VERSION 5.7 ;
  NOWIREEXTENSIONATPIN ON ;
  DIVIDERCHAR "/" ;
  BUSBITCHARS "[]" ;
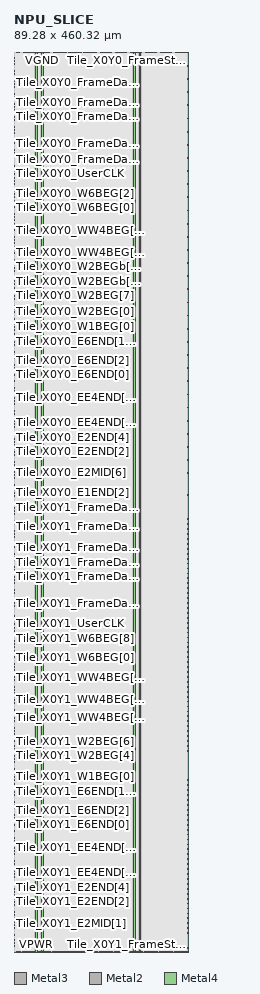
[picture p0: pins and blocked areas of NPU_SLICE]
MACRO NPU_SLICE
  CLASS BLOCK ;
  FOREIGN NPU_SLICE ;
  ORIGIN 0.000 0.000 ;
  SIZE 89.280 BY 460.320 ;
  PIN FAB_USER_CLK
    DIRECTION OUTPUT ;
    USE SIGNAL ;
    ANTENNADIFFAREA 2.724000 ;
    PORT
      LAYER Metal3 ;
        RECT 88.880 221.140 89.280 221.540 ;
    END
  END FAB_USER_CLK
  PIN NPU_ACT_ADDR0
    DIRECTION OUTPUT ;
    USE SIGNAL ;
    ANTENNADIFFAREA 2.647800 ;
    PORT
      LAYER Metal3 ;
        RECT 88.880 143.020 89.280 143.420 ;
    END
  END NPU_ACT_ADDR0
  PIN NPU_ACT_ADDR1
    DIRECTION OUTPUT ;
    USE SIGNAL ;
    ANTENNADIFFAREA 2.647800 ;
    PORT
      LAYER Metal3 ;
        RECT 88.880 145.540 89.280 145.940 ;
    END
  END NPU_ACT_ADDR1
  PIN NPU_ACT_ADDR2
    DIRECTION OUTPUT ;
    USE SIGNAL ;
    ANTENNADIFFAREA 2.647800 ;
    PORT
      LAYER Metal3 ;
        RECT 88.880 148.060 89.280 148.460 ;
    END
  END NPU_ACT_ADDR2
  PIN NPU_ACT_ADDR3
    DIRECTION OUTPUT ;
    USE SIGNAL ;
    ANTENNADIFFAREA 2.647800 ;
    PORT
      LAYER Metal3 ;
        RECT 88.880 150.580 89.280 150.980 ;
    END
  END NPU_ACT_ADDR3
  PIN NPU_ACT_ADDR4
    DIRECTION OUTPUT ;
    USE SIGNAL ;
    ANTENNADIFFAREA 2.647800 ;
    PORT
      LAYER Metal3 ;
        RECT 88.880 153.100 89.280 153.500 ;
    END
  END NPU_ACT_ADDR4
  PIN NPU_ACT_ADDR5
    DIRECTION OUTPUT ;
    USE SIGNAL ;
    ANTENNADIFFAREA 2.647800 ;
    PORT
      LAYER Metal3 ;
        RECT 88.880 155.620 89.280 156.020 ;
    END
  END NPU_ACT_ADDR5
  PIN NPU_ACT_ADDR6
    DIRECTION OUTPUT ;
    USE SIGNAL ;
    ANTENNADIFFAREA 2.647800 ;
    PORT
      LAYER Metal3 ;
        RECT 88.880 158.140 89.280 158.540 ;
    END
  END NPU_ACT_ADDR6
  PIN NPU_ACT_ADDR7
    DIRECTION OUTPUT ;
    USE SIGNAL ;
    ANTENNADIFFAREA 2.647800 ;
    PORT
      LAYER Metal3 ;
        RECT 88.880 160.660 89.280 161.060 ;
    END
  END NPU_ACT_ADDR7
  PIN NPU_ACT_ADDR8
    DIRECTION OUTPUT ;
    USE SIGNAL ;
    ANTENNADIFFAREA 2.647800 ;
    PORT
      LAYER Metal3 ;
        RECT 88.880 163.180 89.280 163.580 ;
    END
  END NPU_ACT_ADDR8
  PIN NPU_ACT_RDATA0
    DIRECTION INPUT ;
    USE SIGNAL ;
    ANTENNAGATEAREA 0.109200 ;
    ANTENNADIFFAREA 2.015400 ;
    PORT
      LAYER Metal3 ;
        RECT 88.880 102.700 89.280 103.100 ;
    END
  END NPU_ACT_RDATA0
  PIN NPU_ACT_RDATA1
    DIRECTION INPUT ;
    USE SIGNAL ;
    ANTENNAGATEAREA 0.109200 ;
    ANTENNADIFFAREA 2.015400 ;
    PORT
      LAYER Metal3 ;
        RECT 88.880 105.220 89.280 105.620 ;
    END
  END NPU_ACT_RDATA1
  PIN NPU_ACT_RDATA2
    DIRECTION INPUT ;
    USE SIGNAL ;
    ANTENNAGATEAREA 0.109200 ;
    ANTENNADIFFAREA 2.015400 ;
    PORT
      LAYER Metal3 ;
        RECT 88.880 107.740 89.280 108.140 ;
    END
  END NPU_ACT_RDATA2
  PIN NPU_ACT_RDATA3
    DIRECTION INPUT ;
    USE SIGNAL ;
    ANTENNAGATEAREA 0.109200 ;
    ANTENNADIFFAREA 2.015400 ;
    PORT
      LAYER Metal3 ;
        RECT 88.880 110.260 89.280 110.660 ;
    END
  END NPU_ACT_RDATA3
  PIN NPU_ACT_RDATA4
    DIRECTION INPUT ;
    USE SIGNAL ;
    ANTENNAGATEAREA 0.109200 ;
    ANTENNADIFFAREA 2.015400 ;
    PORT
      LAYER Metal3 ;
        RECT 88.880 112.780 89.280 113.180 ;
    END
  END NPU_ACT_RDATA4
  PIN NPU_ACT_RDATA5
    DIRECTION INPUT ;
    USE SIGNAL ;
    ANTENNAGATEAREA 0.109200 ;
    ANTENNADIFFAREA 2.015400 ;
    PORT
      LAYER Metal3 ;
        RECT 88.880 115.300 89.280 115.700 ;
    END
  END NPU_ACT_RDATA5
  PIN NPU_ACT_RDATA6
    DIRECTION INPUT ;
    USE SIGNAL ;
    ANTENNAGATEAREA 0.109200 ;
    ANTENNADIFFAREA 2.015400 ;
    PORT
      LAYER Metal3 ;
        RECT 88.880 117.820 89.280 118.220 ;
    END
  END NPU_ACT_RDATA6
  PIN NPU_ACT_RDATA7
    DIRECTION INPUT ;
    USE SIGNAL ;
    ANTENNAGATEAREA 0.109200 ;
    ANTENNADIFFAREA 2.015400 ;
    PORT
      LAYER Metal3 ;
        RECT 88.880 120.340 89.280 120.740 ;
    END
  END NPU_ACT_RDATA7
  PIN NPU_ACT_WDATA0
    DIRECTION OUTPUT ;
    USE SIGNAL ;
    ANTENNADIFFAREA 2.647800 ;
    PORT
      LAYER Metal3 ;
        RECT 88.880 165.700 89.280 166.100 ;
    END
  END NPU_ACT_WDATA0
  PIN NPU_ACT_WDATA1
    DIRECTION OUTPUT ;
    USE SIGNAL ;
    ANTENNADIFFAREA 2.647800 ;
    PORT
      LAYER Metal3 ;
        RECT 88.880 168.220 89.280 168.620 ;
    END
  END NPU_ACT_WDATA1
  PIN NPU_ACT_WDATA2
    DIRECTION OUTPUT ;
    USE SIGNAL ;
    ANTENNADIFFAREA 2.647800 ;
    PORT
      LAYER Metal3 ;
        RECT 88.880 170.740 89.280 171.140 ;
    END
  END NPU_ACT_WDATA2
  PIN NPU_ACT_WDATA3
    DIRECTION OUTPUT ;
    USE SIGNAL ;
    ANTENNADIFFAREA 2.647800 ;
    PORT
      LAYER Metal3 ;
        RECT 88.880 173.260 89.280 173.660 ;
    END
  END NPU_ACT_WDATA3
  PIN NPU_ACT_WDATA4
    DIRECTION OUTPUT ;
    USE SIGNAL ;
    ANTENNADIFFAREA 2.647800 ;
    PORT
      LAYER Metal3 ;
        RECT 88.880 175.780 89.280 176.180 ;
    END
  END NPU_ACT_WDATA4
  PIN NPU_ACT_WDATA5
    DIRECTION OUTPUT ;
    USE SIGNAL ;
    ANTENNADIFFAREA 2.647800 ;
    PORT
      LAYER Metal3 ;
        RECT 88.880 178.300 89.280 178.700 ;
    END
  END NPU_ACT_WDATA5
  PIN NPU_ACT_WDATA6
    DIRECTION OUTPUT ;
    USE SIGNAL ;
    ANTENNADIFFAREA 2.647800 ;
    PORT
      LAYER Metal3 ;
        RECT 88.880 180.820 89.280 181.220 ;
    END
  END NPU_ACT_WDATA6
  PIN NPU_ACT_WDATA7
    DIRECTION OUTPUT ;
    USE SIGNAL ;
    ANTENNADIFFAREA 2.647800 ;
    PORT
      LAYER Metal3 ;
        RECT 88.880 183.340 89.280 183.740 ;
    END
  END NPU_ACT_WDATA7
  PIN NPU_ACT_WE
    DIRECTION OUTPUT ;
    USE SIGNAL ;
    ANTENNADIFFAREA 2.647800 ;
    PORT
      LAYER Metal3 ;
        RECT 88.880 185.860 89.280 186.260 ;
    END
  END NPU_ACT_WE
  PIN NPU_OUT_ACT0
    DIRECTION INPUT ;
    USE SIGNAL ;
    ANTENNAGATEAREA 0.109200 ;
    ANTENNADIFFAREA 2.015400 ;
    PORT
      LAYER Metal3 ;
        RECT 88.880 122.860 89.280 123.260 ;
    END
  END NPU_OUT_ACT0
  PIN NPU_OUT_ACT1
    DIRECTION INPUT ;
    USE SIGNAL ;
    ANTENNAGATEAREA 0.109200 ;
    ANTENNADIFFAREA 2.015400 ;
    PORT
      LAYER Metal3 ;
        RECT 88.880 125.380 89.280 125.780 ;
    END
  END NPU_OUT_ACT1
  PIN NPU_OUT_ACT2
    DIRECTION INPUT ;
    USE SIGNAL ;
    ANTENNAGATEAREA 0.109200 ;
    ANTENNADIFFAREA 2.015400 ;
    PORT
      LAYER Metal3 ;
        RECT 88.880 127.900 89.280 128.300 ;
    END
  END NPU_OUT_ACT2
  PIN NPU_OUT_ACT3
    DIRECTION INPUT ;
    USE SIGNAL ;
    ANTENNAGATEAREA 0.109200 ;
    ANTENNADIFFAREA 2.015400 ;
    PORT
      LAYER Metal3 ;
        RECT 88.880 130.420 89.280 130.820 ;
    END
  END NPU_OUT_ACT3
  PIN NPU_OUT_ACT4
    DIRECTION INPUT ;
    USE SIGNAL ;
    ANTENNAGATEAREA 0.109200 ;
    ANTENNADIFFAREA 2.015400 ;
    PORT
      LAYER Metal3 ;
        RECT 88.880 132.940 89.280 133.340 ;
    END
  END NPU_OUT_ACT4
  PIN NPU_OUT_ACT5
    DIRECTION INPUT ;
    USE SIGNAL ;
    ANTENNAGATEAREA 0.109200 ;
    ANTENNADIFFAREA 2.015400 ;
    PORT
      LAYER Metal3 ;
        RECT 88.880 135.460 89.280 135.860 ;
    END
  END NPU_OUT_ACT5
  PIN NPU_OUT_ACT6
    DIRECTION INPUT ;
    USE SIGNAL ;
    ANTENNAGATEAREA 0.109200 ;
    ANTENNADIFFAREA 2.015400 ;
    PORT
      LAYER Metal3 ;
        RECT 88.880 137.980 89.280 138.380 ;
    END
  END NPU_OUT_ACT6
  PIN NPU_OUT_ACT7
    DIRECTION INPUT ;
    USE SIGNAL ;
    ANTENNAGATEAREA 0.109200 ;
    ANTENNADIFFAREA 2.015400 ;
    PORT
      LAYER Metal3 ;
        RECT 88.880 140.500 89.280 140.900 ;
    END
  END NPU_OUT_ACT7
  PIN NPU_WEIGHT_IN0
    DIRECTION OUTPUT ;
    USE SIGNAL ;
    ANTENNADIFFAREA 2.647800 ;
    PORT
      LAYER Metal3 ;
        RECT 88.880 188.380 89.280 188.780 ;
    END
  END NPU_WEIGHT_IN0
  PIN NPU_WEIGHT_IN1
    DIRECTION OUTPUT ;
    USE SIGNAL ;
    ANTENNADIFFAREA 2.647800 ;
    PORT
      LAYER Metal3 ;
        RECT 88.880 190.900 89.280 191.300 ;
    END
  END NPU_WEIGHT_IN1
  PIN NPU_WEIGHT_IN2
    DIRECTION OUTPUT ;
    USE SIGNAL ;
    ANTENNADIFFAREA 2.647800 ;
    PORT
      LAYER Metal3 ;
        RECT 88.880 193.420 89.280 193.820 ;
    END
  END NPU_WEIGHT_IN2
  PIN NPU_WEIGHT_IN3
    DIRECTION OUTPUT ;
    USE SIGNAL ;
    ANTENNADIFFAREA 2.647800 ;
    PORT
      LAYER Metal3 ;
        RECT 88.880 195.940 89.280 196.340 ;
    END
  END NPU_WEIGHT_IN3
  PIN NPU_WEIGHT_IN4
    DIRECTION OUTPUT ;
    USE SIGNAL ;
    ANTENNADIFFAREA 2.647800 ;
    PORT
      LAYER Metal3 ;
        RECT 88.880 198.460 89.280 198.860 ;
    END
  END NPU_WEIGHT_IN4
  PIN NPU_WEIGHT_IN5
    DIRECTION OUTPUT ;
    USE SIGNAL ;
    ANTENNADIFFAREA 2.647800 ;
    PORT
      LAYER Metal3 ;
        RECT 88.880 200.980 89.280 201.380 ;
    END
  END NPU_WEIGHT_IN5
  PIN NPU_WEIGHT_IN6
    DIRECTION OUTPUT ;
    USE SIGNAL ;
    ANTENNADIFFAREA 2.647800 ;
    PORT
      LAYER Metal3 ;
        RECT 88.880 203.500 89.280 203.900 ;
    END
  END NPU_WEIGHT_IN6
  PIN NPU_WEIGHT_IN7
    DIRECTION OUTPUT ;
    USE SIGNAL ;
    ANTENNADIFFAREA 2.647800 ;
    PORT
      LAYER Metal3 ;
        RECT 88.880 206.020 89.280 206.420 ;
    END
  END NPU_WEIGHT_IN7
  PIN NPU_WEIGHT_SHIFT_EN
    DIRECTION OUTPUT ;
    USE SIGNAL ;
    ANTENNADIFFAREA 2.647800 ;
    PORT
      LAYER Metal3 ;
        RECT 88.880 208.540 89.280 208.940 ;
    END
  END NPU_WEIGHT_SHIFT_EN
  PIN NPU_XBAR_SEL0
    DIRECTION OUTPUT ;
    USE SIGNAL ;
    ANTENNADIFFAREA 2.647800 ;
    PORT
      LAYER Metal3 ;
        RECT 88.880 211.060 89.280 211.460 ;
    END
  END NPU_XBAR_SEL0
  PIN NPU_XBAR_SEL1
    DIRECTION OUTPUT ;
    USE SIGNAL ;
    ANTENNADIFFAREA 2.647800 ;
    PORT
      LAYER Metal3 ;
        RECT 88.880 213.580 89.280 213.980 ;
    END
  END NPU_XBAR_SEL1
  PIN NPU_XBAR_SEL2
    DIRECTION OUTPUT ;
    USE SIGNAL ;
    ANTENNADIFFAREA 2.647800 ;
    PORT
      LAYER Metal3 ;
        RECT 88.880 216.100 89.280 216.500 ;
    END
  END NPU_XBAR_SEL2
  PIN NPU_XBAR_SEL3
    DIRECTION OUTPUT ;
    USE SIGNAL ;
    ANTENNADIFFAREA 2.647800 ;
    PORT
      LAYER Metal3 ;
        RECT 88.880 218.620 89.280 219.020 ;
    END
  END NPU_XBAR_SEL3
  PIN Tile_X0Y0_E1END[0]
    DIRECTION INPUT ;
    USE SIGNAL ;
    ANTENNAGATEAREA 1.279200 ;
    ANTENNADIFFAREA 12.092400 ;
    PORT
      LAYER Metal3 ;
        RECT 0.000 231.220 0.400 231.620 ;
    END
  END Tile_X0Y0_E1END[0]
  PIN Tile_X0Y0_E1END[1]
    DIRECTION INPUT ;
    USE SIGNAL ;
    ANTENNAGATEAREA 1.279200 ;
    ANTENNADIFFAREA 12.092400 ;
    PORT
      LAYER Metal3 ;
        RECT 0.000 232.900 0.400 233.300 ;
    END
  END Tile_X0Y0_E1END[1]
  PIN Tile_X0Y0_E1END[2]
    DIRECTION INPUT ;
    USE SIGNAL ;
    ANTENNAGATEAREA 1.279200 ;
    ANTENNADIFFAREA 12.092400 ;
    PORT
      LAYER Metal3 ;
        RECT 0.000 234.580 0.400 234.980 ;
    END
  END Tile_X0Y0_E1END[2]
  PIN Tile_X0Y0_E1END[3]
    DIRECTION INPUT ;
    USE SIGNAL ;
    ANTENNAGATEAREA 1.066000 ;
    ANTENNADIFFAREA 10.077000 ;
    PORT
      LAYER Metal3 ;
        RECT 0.000 236.260 0.400 236.660 ;
    END
  END Tile_X0Y0_E1END[3]
  PIN Tile_X0Y0_E2END[0]
    DIRECTION INPUT ;
    USE SIGNAL ;
    ANTENNAGATEAREA 0.639600 ;
    ANTENNADIFFAREA 6.046200 ;
    PORT
      LAYER Metal3 ;
        RECT 0.000 252.220 0.400 252.620 ;
    END
  END Tile_X0Y0_E2END[0]
  PIN Tile_X0Y0_E2END[1]
    DIRECTION INPUT ;
    USE SIGNAL ;
    ANTENNAGATEAREA 0.639600 ;
    ANTENNADIFFAREA 6.046200 ;
    PORT
      LAYER Metal3 ;
        RECT 0.000 253.900 0.400 254.300 ;
    END
  END Tile_X0Y0_E2END[1]
  PIN Tile_X0Y0_E2END[2]
    DIRECTION INPUT ;
    USE SIGNAL ;
    ANTENNAGATEAREA 0.639600 ;
    ANTENNADIFFAREA 6.046200 ;
    PORT
      LAYER Metal3 ;
        RECT 0.000 255.580 0.400 255.980 ;
    END
  END Tile_X0Y0_E2END[2]
  PIN Tile_X0Y0_E2END[3]
    DIRECTION INPUT ;
    USE SIGNAL ;
    ANTENNAGATEAREA 0.639600 ;
    ANTENNADIFFAREA 6.046200 ;
    PORT
      LAYER Metal3 ;
        RECT 0.000 257.260 0.400 257.660 ;
    END
  END Tile_X0Y0_E2END[3]
  PIN Tile_X0Y0_E2END[4]
    DIRECTION INPUT ;
    USE SIGNAL ;
    ANTENNAGATEAREA 0.639600 ;
    ANTENNADIFFAREA 6.046200 ;
    PORT
      LAYER Metal3 ;
        RECT 0.000 258.940 0.400 259.340 ;
    END
  END Tile_X0Y0_E2END[4]
  PIN Tile_X0Y0_E2END[5]
    DIRECTION INPUT ;
    USE SIGNAL ;
    ANTENNAGATEAREA 0.639600 ;
    ANTENNADIFFAREA 6.046200 ;
    PORT
      LAYER Metal3 ;
        RECT 0.000 260.620 0.400 261.020 ;
    END
  END Tile_X0Y0_E2END[5]
  PIN Tile_X0Y0_E2END[6]
    DIRECTION INPUT ;
    USE SIGNAL ;
    ANTENNAGATEAREA 0.639600 ;
    ANTENNADIFFAREA 6.046200 ;
    PORT
      LAYER Metal3 ;
        RECT 0.000 262.300 0.400 262.700 ;
    END
  END Tile_X0Y0_E2END[6]
  PIN Tile_X0Y0_E2END[7]
    DIRECTION INPUT ;
    USE SIGNAL ;
    ANTENNAGATEAREA 0.639600 ;
    ANTENNADIFFAREA 6.046200 ;
    PORT
      LAYER Metal3 ;
        RECT 0.000 263.980 0.400 264.380 ;
    END
  END Tile_X0Y0_E2END[7]
  PIN Tile_X0Y0_E2MID[0]
    DIRECTION INPUT ;
    USE SIGNAL ;
    ANTENNAGATEAREA 0.639600 ;
    ANTENNADIFFAREA 6.046200 ;
    PORT
      LAYER Metal3 ;
        RECT 0.000 238.780 0.400 239.180 ;
    END
  END Tile_X0Y0_E2MID[0]
  PIN Tile_X0Y0_E2MID[1]
    DIRECTION INPUT ;
    USE SIGNAL ;
    ANTENNAGATEAREA 0.639600 ;
    ANTENNADIFFAREA 6.046200 ;
    PORT
      LAYER Metal3 ;
        RECT 0.000 240.460 0.400 240.860 ;
    END
  END Tile_X0Y0_E2MID[1]
  PIN Tile_X0Y0_E2MID[2]
    DIRECTION INPUT ;
    USE SIGNAL ;
    ANTENNAGATEAREA 0.639600 ;
    ANTENNADIFFAREA 6.046200 ;
    PORT
      LAYER Metal3 ;
        RECT 0.000 242.140 0.400 242.540 ;
    END
  END Tile_X0Y0_E2MID[2]
  PIN Tile_X0Y0_E2MID[3]
    DIRECTION INPUT ;
    USE SIGNAL ;
    ANTENNAGATEAREA 0.639600 ;
    ANTENNADIFFAREA 6.046200 ;
    PORT
      LAYER Metal3 ;
        RECT 0.000 243.820 0.400 244.220 ;
    END
  END Tile_X0Y0_E2MID[3]
  PIN Tile_X0Y0_E2MID[4]
    DIRECTION INPUT ;
    USE SIGNAL ;
    ANTENNAGATEAREA 0.639600 ;
    ANTENNADIFFAREA 6.046200 ;
    PORT
      LAYER Metal3 ;
        RECT 0.000 245.500 0.400 245.900 ;
    END
  END Tile_X0Y0_E2MID[4]
  PIN Tile_X0Y0_E2MID[5]
    DIRECTION INPUT ;
    USE SIGNAL ;
    ANTENNAGATEAREA 0.639600 ;
    ANTENNADIFFAREA 6.046200 ;
    PORT
      LAYER Metal3 ;
        RECT 0.000 247.180 0.400 247.580 ;
    END
  END Tile_X0Y0_E2MID[5]
  PIN Tile_X0Y0_E2MID[6]
    DIRECTION INPUT ;
    USE SIGNAL ;
    ANTENNAGATEAREA 0.639600 ;
    ANTENNADIFFAREA 6.046200 ;
    PORT
      LAYER Metal3 ;
        RECT 0.000 248.860 0.400 249.260 ;
    END
  END Tile_X0Y0_E2MID[6]
  PIN Tile_X0Y0_E2MID[7]
    DIRECTION INPUT ;
    USE SIGNAL ;
    ANTENNAGATEAREA 0.639600 ;
    ANTENNADIFFAREA 6.046200 ;
    PORT
      LAYER Metal3 ;
        RECT 0.000 250.540 0.400 250.940 ;
    END
  END Tile_X0Y0_E2MID[7]
  PIN Tile_X0Y0_E6END[0]
    DIRECTION INPUT ;
    USE SIGNAL ;
    ANTENNAGATEAREA 0.852800 ;
    ANTENNADIFFAREA 8.061600 ;
    PORT
      LAYER Metal3 ;
        RECT 0.000 295.060 0.400 295.460 ;
    END
  END Tile_X0Y0_E6END[0]
  PIN Tile_X0Y0_E6END[10]
    DIRECTION INPUT ;
    USE SIGNAL ;
    ANTENNAGATEAREA 0.639600 ;
    ANTENNADIFFAREA 6.046200 ;
    PORT
      LAYER Metal3 ;
        RECT 0.000 311.860 0.400 312.260 ;
    END
  END Tile_X0Y0_E6END[10]
  PIN Tile_X0Y0_E6END[11]
    DIRECTION INPUT ;
    USE SIGNAL ;
    ANTENNAGATEAREA 0.639600 ;
    ANTENNADIFFAREA 6.046200 ;
    PORT
      LAYER Metal3 ;
        RECT 0.000 313.540 0.400 313.940 ;
    END
  END Tile_X0Y0_E6END[11]
  PIN Tile_X0Y0_E6END[1]
    DIRECTION INPUT ;
    USE SIGNAL ;
    ANTENNAGATEAREA 0.852800 ;
    ANTENNADIFFAREA 8.061600 ;
    PORT
      LAYER Metal3 ;
        RECT 0.000 296.740 0.400 297.140 ;
    END
  END Tile_X0Y0_E6END[1]
  PIN Tile_X0Y0_E6END[2]
    DIRECTION INPUT ;
    USE SIGNAL ;
    ANTENNAGATEAREA 0.852800 ;
    ANTENNADIFFAREA 8.061600 ;
    PORT
      LAYER Metal3 ;
        RECT 0.000 298.420 0.400 298.820 ;
    END
  END Tile_X0Y0_E6END[2]
  PIN Tile_X0Y0_E6END[3]
    DIRECTION INPUT ;
    USE SIGNAL ;
    ANTENNAGATEAREA 0.639600 ;
    ANTENNADIFFAREA 6.046200 ;
    PORT
      LAYER Metal3 ;
        RECT 0.000 300.100 0.400 300.500 ;
    END
  END Tile_X0Y0_E6END[3]
  PIN Tile_X0Y0_E6END[4]
    DIRECTION INPUT ;
    USE SIGNAL ;
    ANTENNAGATEAREA 0.639600 ;
    ANTENNADIFFAREA 6.046200 ;
    PORT
      LAYER Metal3 ;
        RECT 0.000 301.780 0.400 302.180 ;
    END
  END Tile_X0Y0_E6END[4]
  PIN Tile_X0Y0_E6END[5]
    DIRECTION INPUT ;
    USE SIGNAL ;
    ANTENNAGATEAREA 0.639600 ;
    ANTENNADIFFAREA 6.046200 ;
    PORT
      LAYER Metal3 ;
        RECT 0.000 303.460 0.400 303.860 ;
    END
  END Tile_X0Y0_E6END[5]
  PIN Tile_X0Y0_E6END[6]
    DIRECTION INPUT ;
    USE SIGNAL ;
    ANTENNAGATEAREA 0.639600 ;
    ANTENNADIFFAREA 6.046200 ;
    PORT
      LAYER Metal3 ;
        RECT 0.000 305.140 0.400 305.540 ;
    END
  END Tile_X0Y0_E6END[6]
  PIN Tile_X0Y0_E6END[7]
    DIRECTION INPUT ;
    USE SIGNAL ;
    ANTENNAGATEAREA 0.639600 ;
    ANTENNADIFFAREA 6.046200 ;
    PORT
      LAYER Metal3 ;
        RECT 0.000 306.820 0.400 307.220 ;
    END
  END Tile_X0Y0_E6END[7]
  PIN Tile_X0Y0_E6END[8]
    DIRECTION INPUT ;
    USE SIGNAL ;
    ANTENNAGATEAREA 0.639600 ;
    ANTENNADIFFAREA 6.046200 ;
    PORT
      LAYER Metal3 ;
        RECT 0.000 308.500 0.400 308.900 ;
    END
  END Tile_X0Y0_E6END[8]
  PIN Tile_X0Y0_E6END[9]
    DIRECTION INPUT ;
    USE SIGNAL ;
    ANTENNAGATEAREA 0.639600 ;
    ANTENNADIFFAREA 6.046200 ;
    PORT
      LAYER Metal3 ;
        RECT 0.000 310.180 0.400 310.580 ;
    END
  END Tile_X0Y0_E6END[9]
  PIN Tile_X0Y0_EE4END[0]
    DIRECTION INPUT ;
    USE SIGNAL ;
    ANTENNAGATEAREA 0.426400 ;
    ANTENNADIFFAREA 4.030800 ;
    PORT
      LAYER Metal3 ;
        RECT 0.000 266.500 0.400 266.900 ;
    END
  END Tile_X0Y0_EE4END[0]
  PIN Tile_X0Y0_EE4END[10]
    DIRECTION INPUT ;
    USE SIGNAL ;
    ANTENNAGATEAREA 0.426400 ;
    ANTENNADIFFAREA 4.030800 ;
    PORT
      LAYER Metal3 ;
        RECT 0.000 283.300 0.400 283.700 ;
    END
  END Tile_X0Y0_EE4END[10]
  PIN Tile_X0Y0_EE4END[11]
    DIRECTION INPUT ;
    USE SIGNAL ;
    ANTENNAGATEAREA 0.426400 ;
    ANTENNADIFFAREA 4.030800 ;
    PORT
      LAYER Metal3 ;
        RECT 0.000 284.980 0.400 285.380 ;
    END
  END Tile_X0Y0_EE4END[11]
  PIN Tile_X0Y0_EE4END[12]
    DIRECTION INPUT ;
    USE SIGNAL ;
    ANTENNAGATEAREA 0.426400 ;
    ANTENNADIFFAREA 4.030800 ;
    PORT
      LAYER Metal3 ;
        RECT 0.000 286.660 0.400 287.060 ;
    END
  END Tile_X0Y0_EE4END[12]
  PIN Tile_X0Y0_EE4END[13]
    DIRECTION INPUT ;
    USE SIGNAL ;
    ANTENNAGATEAREA 0.426400 ;
    ANTENNADIFFAREA 4.030800 ;
    PORT
      LAYER Metal3 ;
        RECT 0.000 288.340 0.400 288.740 ;
    END
  END Tile_X0Y0_EE4END[13]
  PIN Tile_X0Y0_EE4END[14]
    DIRECTION INPUT ;
    USE SIGNAL ;
    ANTENNAGATEAREA 0.426400 ;
    ANTENNADIFFAREA 4.030800 ;
    PORT
      LAYER Metal3 ;
        RECT 0.000 290.020 0.400 290.420 ;
    END
  END Tile_X0Y0_EE4END[14]
  PIN Tile_X0Y0_EE4END[15]
    DIRECTION INPUT ;
    USE SIGNAL ;
    ANTENNAGATEAREA 0.426400 ;
    ANTENNADIFFAREA 4.030800 ;
    PORT
      LAYER Metal3 ;
        RECT 0.000 291.700 0.400 292.100 ;
    END
  END Tile_X0Y0_EE4END[15]
  PIN Tile_X0Y0_EE4END[1]
    DIRECTION INPUT ;
    USE SIGNAL ;
    ANTENNAGATEAREA 0.426400 ;
    ANTENNADIFFAREA 4.030800 ;
    PORT
      LAYER Metal3 ;
        RECT 0.000 268.180 0.400 268.580 ;
    END
  END Tile_X0Y0_EE4END[1]
  PIN Tile_X0Y0_EE4END[2]
    DIRECTION INPUT ;
    USE SIGNAL ;
    ANTENNAGATEAREA 0.426400 ;
    ANTENNADIFFAREA 4.030800 ;
    PORT
      LAYER Metal3 ;
        RECT 0.000 269.860 0.400 270.260 ;
    END
  END Tile_X0Y0_EE4END[2]
  PIN Tile_X0Y0_EE4END[3]
    DIRECTION INPUT ;
    USE SIGNAL ;
    ANTENNAGATEAREA 0.426400 ;
    ANTENNADIFFAREA 4.030800 ;
    PORT
      LAYER Metal3 ;
        RECT 0.000 271.540 0.400 271.940 ;
    END
  END Tile_X0Y0_EE4END[3]
  PIN Tile_X0Y0_EE4END[4]
    DIRECTION INPUT ;
    USE SIGNAL ;
    ANTENNAGATEAREA 0.426400 ;
    ANTENNADIFFAREA 4.030800 ;
    PORT
      LAYER Metal3 ;
        RECT 0.000 273.220 0.400 273.620 ;
    END
  END Tile_X0Y0_EE4END[4]
  PIN Tile_X0Y0_EE4END[5]
    DIRECTION INPUT ;
    USE SIGNAL ;
    ANTENNAGATEAREA 0.426400 ;
    ANTENNADIFFAREA 4.030800 ;
    PORT
      LAYER Metal3 ;
        RECT 0.000 274.900 0.400 275.300 ;
    END
  END Tile_X0Y0_EE4END[5]
  PIN Tile_X0Y0_EE4END[6]
    DIRECTION INPUT ;
    USE SIGNAL ;
    ANTENNAGATEAREA 0.426400 ;
    ANTENNADIFFAREA 4.030800 ;
    PORT
      LAYER Metal3 ;
        RECT 0.000 276.580 0.400 276.980 ;
    END
  END Tile_X0Y0_EE4END[6]
  PIN Tile_X0Y0_EE4END[7]
    DIRECTION INPUT ;
    USE SIGNAL ;
    ANTENNAGATEAREA 0.426400 ;
    ANTENNADIFFAREA 4.030800 ;
    PORT
      LAYER Metal3 ;
        RECT 0.000 278.260 0.400 278.660 ;
    END
  END Tile_X0Y0_EE4END[7]
  PIN Tile_X0Y0_EE4END[8]
    DIRECTION INPUT ;
    USE SIGNAL ;
    ANTENNAGATEAREA 0.426400 ;
    ANTENNADIFFAREA 4.030800 ;
    PORT
      LAYER Metal3 ;
        RECT 0.000 279.940 0.400 280.340 ;
    END
  END Tile_X0Y0_EE4END[8]
  PIN Tile_X0Y0_EE4END[9]
    DIRECTION INPUT ;
    USE SIGNAL ;
    ANTENNAGATEAREA 0.426400 ;
    ANTENNADIFFAREA 4.030800 ;
    PORT
      LAYER Metal3 ;
        RECT 0.000 281.620 0.400 282.020 ;
    END
  END Tile_X0Y0_EE4END[9]
  PIN Tile_X0Y0_FrameData[0]
    DIRECTION INPUT ;
    USE SIGNAL ;
    ANTENNAGATEAREA 1.445600 ;
    ANTENNADIFFAREA 16.123199 ;
    PORT
      LAYER Metal3 ;
        RECT 0.000 405.100 0.400 405.500 ;
    END
  END Tile_X0Y0_FrameData[0]
  PIN Tile_X0Y0_FrameData[10]
    DIRECTION INPUT ;
    USE SIGNAL ;
    ANTENNAGATEAREA 1.626300 ;
    ANTENNADIFFAREA 18.138599 ;
    PORT
      LAYER Metal3 ;
        RECT 0.000 421.900 0.400 422.300 ;
    END
  END Tile_X0Y0_FrameData[10]
  PIN Tile_X0Y0_FrameData[11]
    DIRECTION INPUT ;
    USE SIGNAL ;
    ANTENNAGATEAREA 1.626300 ;
    ANTENNADIFFAREA 18.138599 ;
    PORT
      LAYER Metal3 ;
        RECT 0.000 423.580 0.400 423.980 ;
    END
  END Tile_X0Y0_FrameData[11]
  PIN Tile_X0Y0_FrameData[12]
    DIRECTION INPUT ;
    USE SIGNAL ;
    ANTENNAGATEAREA 1.626300 ;
    ANTENNADIFFAREA 18.138599 ;
    PORT
      LAYER Metal3 ;
        RECT 0.000 425.260 0.400 425.660 ;
    END
  END Tile_X0Y0_FrameData[12]
  PIN Tile_X0Y0_FrameData[13]
    DIRECTION INPUT ;
    USE SIGNAL ;
    ANTENNAGATEAREA 1.626300 ;
    ANTENNADIFFAREA 18.138599 ;
    PORT
      LAYER Metal3 ;
        RECT 0.000 426.940 0.400 427.340 ;
    END
  END Tile_X0Y0_FrameData[13]
  PIN Tile_X0Y0_FrameData[14]
    DIRECTION INPUT ;
    USE SIGNAL ;
    ANTENNAGATEAREA 1.626300 ;
    ANTENNADIFFAREA 18.138599 ;
    PORT
      LAYER Metal3 ;
        RECT 0.000 428.620 0.400 429.020 ;
    END
  END Tile_X0Y0_FrameData[14]
  PIN Tile_X0Y0_FrameData[15]
    DIRECTION INPUT ;
    USE SIGNAL ;
    ANTENNAGATEAREA 1.626300 ;
    ANTENNADIFFAREA 18.138599 ;
    PORT
      LAYER Metal3 ;
        RECT 0.000 430.300 0.400 430.700 ;
    END
  END Tile_X0Y0_FrameData[15]
  PIN Tile_X0Y0_FrameData[16]
    DIRECTION INPUT ;
    USE SIGNAL ;
    ANTENNAGATEAREA 1.626300 ;
    ANTENNADIFFAREA 18.138599 ;
    PORT
      LAYER Metal3 ;
        RECT 0.000 431.980 0.400 432.380 ;
    END
  END Tile_X0Y0_FrameData[16]
  PIN Tile_X0Y0_FrameData[17]
    DIRECTION INPUT ;
    USE SIGNAL ;
    ANTENNAGATEAREA 1.626300 ;
    ANTENNADIFFAREA 18.138599 ;
    PORT
      LAYER Metal3 ;
        RECT 0.000 433.660 0.400 434.060 ;
    END
  END Tile_X0Y0_FrameData[17]
  PIN Tile_X0Y0_FrameData[18]
    DIRECTION INPUT ;
    USE SIGNAL ;
    ANTENNAGATEAREA 1.626300 ;
    ANTENNADIFFAREA 18.138599 ;
    PORT
      LAYER Metal3 ;
        RECT 0.000 435.340 0.400 435.740 ;
    END
  END Tile_X0Y0_FrameData[18]
  PIN Tile_X0Y0_FrameData[19]
    DIRECTION INPUT ;
    USE SIGNAL ;
    ANTENNAGATEAREA 1.626300 ;
    ANTENNADIFFAREA 18.138599 ;
    PORT
      LAYER Metal3 ;
        RECT 0.000 437.020 0.400 437.420 ;
    END
  END Tile_X0Y0_FrameData[19]
  PIN Tile_X0Y0_FrameData[1]
    DIRECTION INPUT ;
    USE SIGNAL ;
    ANTENNAGATEAREA 1.445600 ;
    ANTENNADIFFAREA 16.123199 ;
    PORT
      LAYER Metal3 ;
        RECT 0.000 406.780 0.400 407.180 ;
    END
  END Tile_X0Y0_FrameData[1]
  PIN Tile_X0Y0_FrameData[20]
    DIRECTION INPUT ;
    USE SIGNAL ;
    ANTENNAGATEAREA 1.626300 ;
    ANTENNADIFFAREA 18.138599 ;
    PORT
      LAYER Metal3 ;
        RECT 0.000 438.700 0.400 439.100 ;
    END
  END Tile_X0Y0_FrameData[20]
  PIN Tile_X0Y0_FrameData[21]
    DIRECTION INPUT ;
    USE SIGNAL ;
    ANTENNAGATEAREA 1.626300 ;
    ANTENNADIFFAREA 18.138599 ;
    PORT
      LAYER Metal3 ;
        RECT 0.000 440.380 0.400 440.780 ;
    END
  END Tile_X0Y0_FrameData[21]
  PIN Tile_X0Y0_FrameData[22]
    DIRECTION INPUT ;
    USE SIGNAL ;
    ANTENNAGATEAREA 1.626300 ;
    ANTENNADIFFAREA 18.138599 ;
    PORT
      LAYER Metal3 ;
        RECT 0.000 442.060 0.400 442.460 ;
    END
  END Tile_X0Y0_FrameData[22]
  PIN Tile_X0Y0_FrameData[23]
    DIRECTION INPUT ;
    USE SIGNAL ;
    ANTENNAGATEAREA 1.626300 ;
    ANTENNADIFFAREA 18.138599 ;
    PORT
      LAYER Metal3 ;
        RECT 0.000 443.740 0.400 444.140 ;
    END
  END Tile_X0Y0_FrameData[23]
  PIN Tile_X0Y0_FrameData[24]
    DIRECTION INPUT ;
    USE SIGNAL ;
    ANTENNAGATEAREA 1.626300 ;
    ANTENNADIFFAREA 18.138599 ;
    PORT
      LAYER Metal3 ;
        RECT 0.000 445.420 0.400 445.820 ;
    END
  END Tile_X0Y0_FrameData[24]
  PIN Tile_X0Y0_FrameData[25]
    DIRECTION INPUT ;
    USE SIGNAL ;
    ANTENNAGATEAREA 1.626300 ;
    ANTENNADIFFAREA 18.138599 ;
    PORT
      LAYER Metal3 ;
        RECT 0.000 447.100 0.400 447.500 ;
    END
  END Tile_X0Y0_FrameData[25]
  PIN Tile_X0Y0_FrameData[26]
    DIRECTION INPUT ;
    USE SIGNAL ;
    ANTENNAGATEAREA 1.626300 ;
    ANTENNADIFFAREA 18.138599 ;
    PORT
      LAYER Metal3 ;
        RECT 0.000 448.780 0.400 449.180 ;
    END
  END Tile_X0Y0_FrameData[26]
  PIN Tile_X0Y0_FrameData[27]
    DIRECTION INPUT ;
    USE SIGNAL ;
    ANTENNAGATEAREA 1.626300 ;
    ANTENNADIFFAREA 18.138599 ;
    PORT
      LAYER Metal3 ;
        RECT 0.000 450.460 0.400 450.860 ;
    END
  END Tile_X0Y0_FrameData[27]
  PIN Tile_X0Y0_FrameData[28]
    DIRECTION INPUT ;
    USE SIGNAL ;
    ANTENNAGATEAREA 1.626300 ;
    ANTENNADIFFAREA 18.138599 ;
    PORT
      LAYER Metal3 ;
        RECT 0.000 452.140 0.400 452.540 ;
    END
  END Tile_X0Y0_FrameData[28]
  PIN Tile_X0Y0_FrameData[29]
    DIRECTION INPUT ;
    USE SIGNAL ;
    ANTENNAGATEAREA 1.626300 ;
    ANTENNADIFFAREA 18.138599 ;
    PORT
      LAYER Metal3 ;
        RECT 0.000 453.820 0.400 454.220 ;
    END
  END Tile_X0Y0_FrameData[29]
  PIN Tile_X0Y0_FrameData[2]
    DIRECTION INPUT ;
    USE SIGNAL ;
    ANTENNAGATEAREA 1.626300 ;
    ANTENNADIFFAREA 18.138599 ;
    PORT
      LAYER Metal3 ;
        RECT 0.000 408.460 0.400 408.860 ;
    END
  END Tile_X0Y0_FrameData[2]
  PIN Tile_X0Y0_FrameData[30]
    DIRECTION INPUT ;
    USE SIGNAL ;
    ANTENNAGATEAREA 1.626300 ;
    ANTENNADIFFAREA 18.138599 ;
    PORT
      LAYER Metal3 ;
        RECT 0.000 455.500 0.400 455.900 ;
    END
  END Tile_X0Y0_FrameData[30]
  PIN Tile_X0Y0_FrameData[31]
    DIRECTION INPUT ;
    USE SIGNAL ;
    ANTENNAGATEAREA 1.626300 ;
    ANTENNADIFFAREA 18.138599 ;
    PORT
      LAYER Metal3 ;
        RECT 0.000 457.180 0.400 457.580 ;
    END
  END Tile_X0Y0_FrameData[31]
  PIN Tile_X0Y0_FrameData[3]
    DIRECTION INPUT ;
    USE SIGNAL ;
    ANTENNAGATEAREA 1.626300 ;
    ANTENNADIFFAREA 18.138599 ;
    PORT
      LAYER Metal3 ;
        RECT 0.000 410.140 0.400 410.540 ;
    END
  END Tile_X0Y0_FrameData[3]
  PIN Tile_X0Y0_FrameData[4]
    DIRECTION INPUT ;
    USE SIGNAL ;
    ANTENNAGATEAREA 1.626300 ;
    ANTENNADIFFAREA 18.138599 ;
    PORT
      LAYER Metal3 ;
        RECT 0.000 411.820 0.400 412.220 ;
    END
  END Tile_X0Y0_FrameData[4]
  PIN Tile_X0Y0_FrameData[5]
    DIRECTION INPUT ;
    USE SIGNAL ;
    ANTENNAGATEAREA 1.626300 ;
    ANTENNADIFFAREA 18.138599 ;
    PORT
      LAYER Metal3 ;
        RECT 0.000 413.500 0.400 413.900 ;
    END
  END Tile_X0Y0_FrameData[5]
  PIN Tile_X0Y0_FrameData[6]
    DIRECTION INPUT ;
    USE SIGNAL ;
    ANTENNAGATEAREA 1.626300 ;
    ANTENNADIFFAREA 18.138599 ;
    PORT
      LAYER Metal3 ;
        RECT 0.000 415.180 0.400 415.580 ;
    END
  END Tile_X0Y0_FrameData[6]
  PIN Tile_X0Y0_FrameData[7]
    DIRECTION INPUT ;
    USE SIGNAL ;
    ANTENNAGATEAREA 1.626300 ;
    ANTENNADIFFAREA 18.138599 ;
    PORT
      LAYER Metal3 ;
        RECT 0.000 416.860 0.400 417.260 ;
    END
  END Tile_X0Y0_FrameData[7]
  PIN Tile_X0Y0_FrameData[8]
    DIRECTION INPUT ;
    USE SIGNAL ;
    ANTENNAGATEAREA 1.626300 ;
    ANTENNADIFFAREA 18.138599 ;
    PORT
      LAYER Metal3 ;
        RECT 0.000 418.540 0.400 418.940 ;
    END
  END Tile_X0Y0_FrameData[8]
  PIN Tile_X0Y0_FrameData[9]
    DIRECTION INPUT ;
    USE SIGNAL ;
    ANTENNAGATEAREA 1.626300 ;
    ANTENNADIFFAREA 18.138599 ;
    PORT
      LAYER Metal3 ;
        RECT 0.000 420.220 0.400 420.620 ;
    END
  END Tile_X0Y0_FrameData[9]
  PIN Tile_X0Y0_FrameData_O[0]
    DIRECTION OUTPUT ;
    USE SIGNAL ;
    ANTENNADIFFAREA 2.724000 ;
    PORT
      LAYER Metal3 ;
        RECT 88.880 244.660 89.280 245.060 ;
    END
  END Tile_X0Y0_FrameData_O[0]
  PIN Tile_X0Y0_FrameData_O[10]
    DIRECTION OUTPUT ;
    USE SIGNAL ;
    ANTENNADIFFAREA 2.724000 ;
    PORT
      LAYER Metal3 ;
        RECT 88.880 311.860 89.280 312.260 ;
    END
  END Tile_X0Y0_FrameData_O[10]
  PIN Tile_X0Y0_FrameData_O[11]
    DIRECTION OUTPUT ;
    USE SIGNAL ;
    ANTENNADIFFAREA 2.724000 ;
    PORT
      LAYER Metal3 ;
        RECT 88.880 318.580 89.280 318.980 ;
    END
  END Tile_X0Y0_FrameData_O[11]
  PIN Tile_X0Y0_FrameData_O[12]
    DIRECTION OUTPUT ;
    USE SIGNAL ;
    ANTENNADIFFAREA 2.724000 ;
    PORT
      LAYER Metal3 ;
        RECT 88.880 325.300 89.280 325.700 ;
    END
  END Tile_X0Y0_FrameData_O[12]
  PIN Tile_X0Y0_FrameData_O[13]
    DIRECTION OUTPUT ;
    USE SIGNAL ;
    ANTENNADIFFAREA 2.724000 ;
    PORT
      LAYER Metal3 ;
        RECT 88.880 332.020 89.280 332.420 ;
    END
  END Tile_X0Y0_FrameData_O[13]
  PIN Tile_X0Y0_FrameData_O[14]
    DIRECTION OUTPUT ;
    USE SIGNAL ;
    ANTENNADIFFAREA 2.724000 ;
    PORT
      LAYER Metal3 ;
        RECT 88.880 338.740 89.280 339.140 ;
    END
  END Tile_X0Y0_FrameData_O[14]
  PIN Tile_X0Y0_FrameData_O[15]
    DIRECTION OUTPUT ;
    USE SIGNAL ;
    ANTENNADIFFAREA 2.724000 ;
    PORT
      LAYER Metal3 ;
        RECT 88.880 345.460 89.280 345.860 ;
    END
  END Tile_X0Y0_FrameData_O[15]
  PIN Tile_X0Y0_FrameData_O[16]
    DIRECTION OUTPUT ;
    USE SIGNAL ;
    ANTENNADIFFAREA 2.724000 ;
    PORT
      LAYER Metal3 ;
        RECT 88.880 352.180 89.280 352.580 ;
    END
  END Tile_X0Y0_FrameData_O[16]
  PIN Tile_X0Y0_FrameData_O[17]
    DIRECTION OUTPUT ;
    USE SIGNAL ;
    ANTENNADIFFAREA 2.724000 ;
    PORT
      LAYER Metal3 ;
        RECT 88.880 358.900 89.280 359.300 ;
    END
  END Tile_X0Y0_FrameData_O[17]
  PIN Tile_X0Y0_FrameData_O[18]
    DIRECTION OUTPUT ;
    USE SIGNAL ;
    ANTENNADIFFAREA 2.724000 ;
    PORT
      LAYER Metal3 ;
        RECT 88.880 365.620 89.280 366.020 ;
    END
  END Tile_X0Y0_FrameData_O[18]
  PIN Tile_X0Y0_FrameData_O[19]
    DIRECTION OUTPUT ;
    USE SIGNAL ;
    ANTENNADIFFAREA 2.724000 ;
    PORT
      LAYER Metal3 ;
        RECT 88.880 372.340 89.280 372.740 ;
    END
  END Tile_X0Y0_FrameData_O[19]
  PIN Tile_X0Y0_FrameData_O[1]
    DIRECTION OUTPUT ;
    USE SIGNAL ;
    ANTENNADIFFAREA 2.724000 ;
    PORT
      LAYER Metal3 ;
        RECT 88.880 251.380 89.280 251.780 ;
    END
  END Tile_X0Y0_FrameData_O[1]
  PIN Tile_X0Y0_FrameData_O[20]
    DIRECTION OUTPUT ;
    USE SIGNAL ;
    ANTENNADIFFAREA 2.724000 ;
    PORT
      LAYER Metal3 ;
        RECT 88.880 379.060 89.280 379.460 ;
    END
  END Tile_X0Y0_FrameData_O[20]
  PIN Tile_X0Y0_FrameData_O[21]
    DIRECTION OUTPUT ;
    USE SIGNAL ;
    ANTENNADIFFAREA 2.724000 ;
    PORT
      LAYER Metal3 ;
        RECT 88.880 385.780 89.280 386.180 ;
    END
  END Tile_X0Y0_FrameData_O[21]
  PIN Tile_X0Y0_FrameData_O[22]
    DIRECTION OUTPUT ;
    USE SIGNAL ;
    ANTENNADIFFAREA 2.724000 ;
    PORT
      LAYER Metal3 ;
        RECT 88.880 392.500 89.280 392.900 ;
    END
  END Tile_X0Y0_FrameData_O[22]
  PIN Tile_X0Y0_FrameData_O[23]
    DIRECTION OUTPUT ;
    USE SIGNAL ;
    ANTENNADIFFAREA 2.724000 ;
    PORT
      LAYER Metal3 ;
        RECT 88.880 399.220 89.280 399.620 ;
    END
  END Tile_X0Y0_FrameData_O[23]
  PIN Tile_X0Y0_FrameData_O[24]
    DIRECTION OUTPUT ;
    USE SIGNAL ;
    ANTENNADIFFAREA 2.724000 ;
    PORT
      LAYER Metal3 ;
        RECT 88.880 405.940 89.280 406.340 ;
    END
  END Tile_X0Y0_FrameData_O[24]
  PIN Tile_X0Y0_FrameData_O[25]
    DIRECTION OUTPUT ;
    USE SIGNAL ;
    ANTENNADIFFAREA 2.724000 ;
    PORT
      LAYER Metal3 ;
        RECT 88.880 412.660 89.280 413.060 ;
    END
  END Tile_X0Y0_FrameData_O[25]
  PIN Tile_X0Y0_FrameData_O[26]
    DIRECTION OUTPUT ;
    USE SIGNAL ;
    ANTENNADIFFAREA 2.724000 ;
    PORT
      LAYER Metal3 ;
        RECT 88.880 419.380 89.280 419.780 ;
    END
  END Tile_X0Y0_FrameData_O[26]
  PIN Tile_X0Y0_FrameData_O[27]
    DIRECTION OUTPUT ;
    USE SIGNAL ;
    ANTENNADIFFAREA 2.724000 ;
    PORT
      LAYER Metal3 ;
        RECT 88.880 426.100 89.280 426.500 ;
    END
  END Tile_X0Y0_FrameData_O[27]
  PIN Tile_X0Y0_FrameData_O[28]
    DIRECTION OUTPUT ;
    USE SIGNAL ;
    ANTENNADIFFAREA 2.724000 ;
    PORT
      LAYER Metal3 ;
        RECT 88.880 432.820 89.280 433.220 ;
    END
  END Tile_X0Y0_FrameData_O[28]
  PIN Tile_X0Y0_FrameData_O[29]
    DIRECTION OUTPUT ;
    USE SIGNAL ;
    ANTENNADIFFAREA 2.724000 ;
    PORT
      LAYER Metal3 ;
        RECT 88.880 439.540 89.280 439.940 ;
    END
  END Tile_X0Y0_FrameData_O[29]
  PIN Tile_X0Y0_FrameData_O[2]
    DIRECTION OUTPUT ;
    USE SIGNAL ;
    ANTENNADIFFAREA 2.724000 ;
    PORT
      LAYER Metal3 ;
        RECT 88.880 258.100 89.280 258.500 ;
    END
  END Tile_X0Y0_FrameData_O[2]
  PIN Tile_X0Y0_FrameData_O[30]
    DIRECTION OUTPUT ;
    USE SIGNAL ;
    ANTENNADIFFAREA 2.724000 ;
    PORT
      LAYER Metal3 ;
        RECT 88.880 446.260 89.280 446.660 ;
    END
  END Tile_X0Y0_FrameData_O[30]
  PIN Tile_X0Y0_FrameData_O[31]
    DIRECTION OUTPUT ;
    USE SIGNAL ;
    ANTENNADIFFAREA 2.724000 ;
    PORT
      LAYER Metal3 ;
        RECT 88.880 452.980 89.280 453.380 ;
    END
  END Tile_X0Y0_FrameData_O[31]
  PIN Tile_X0Y0_FrameData_O[3]
    DIRECTION OUTPUT ;
    USE SIGNAL ;
    ANTENNADIFFAREA 2.724000 ;
    PORT
      LAYER Metal3 ;
        RECT 88.880 264.820 89.280 265.220 ;
    END
  END Tile_X0Y0_FrameData_O[3]
  PIN Tile_X0Y0_FrameData_O[4]
    DIRECTION OUTPUT ;
    USE SIGNAL ;
    ANTENNADIFFAREA 2.724000 ;
    PORT
      LAYER Metal3 ;
        RECT 88.880 271.540 89.280 271.940 ;
    END
  END Tile_X0Y0_FrameData_O[4]
  PIN Tile_X0Y0_FrameData_O[5]
    DIRECTION OUTPUT ;
    USE SIGNAL ;
    ANTENNADIFFAREA 2.724000 ;
    PORT
      LAYER Metal3 ;
        RECT 88.880 278.260 89.280 278.660 ;
    END
  END Tile_X0Y0_FrameData_O[5]
  PIN Tile_X0Y0_FrameData_O[6]
    DIRECTION OUTPUT ;
    USE SIGNAL ;
    ANTENNADIFFAREA 2.724000 ;
    PORT
      LAYER Metal3 ;
        RECT 88.880 284.980 89.280 285.380 ;
    END
  END Tile_X0Y0_FrameData_O[6]
  PIN Tile_X0Y0_FrameData_O[7]
    DIRECTION OUTPUT ;
    USE SIGNAL ;
    ANTENNADIFFAREA 2.724000 ;
    PORT
      LAYER Metal3 ;
        RECT 88.880 291.700 89.280 292.100 ;
    END
  END Tile_X0Y0_FrameData_O[7]
  PIN Tile_X0Y0_FrameData_O[8]
    DIRECTION OUTPUT ;
    USE SIGNAL ;
    ANTENNADIFFAREA 2.724000 ;
    PORT
      LAYER Metal3 ;
        RECT 88.880 298.420 89.280 298.820 ;
    END
  END Tile_X0Y0_FrameData_O[8]
  PIN Tile_X0Y0_FrameData_O[9]
    DIRECTION OUTPUT ;
    USE SIGNAL ;
    ANTENNADIFFAREA 2.724000 ;
    PORT
      LAYER Metal3 ;
        RECT 88.880 305.140 89.280 305.540 ;
    END
  END Tile_X0Y0_FrameData_O[9]
  PIN Tile_X0Y0_FrameStrobe_O[0]
    DIRECTION OUTPUT ;
    USE SIGNAL ;
    ANTENNADIFFAREA 2.724000 ;
    PORT
      LAYER Metal2 ;
        RECT 70.360 459.920 70.760 460.320 ;
    END
  END Tile_X0Y0_FrameStrobe_O[0]
  PIN Tile_X0Y0_FrameStrobe_O[10]
    DIRECTION OUTPUT ;
    USE SIGNAL ;
    ANTENNADIFFAREA 2.724000 ;
    PORT
      LAYER Metal2 ;
        RECT 79.960 459.920 80.360 460.320 ;
    END
  END Tile_X0Y0_FrameStrobe_O[10]
  PIN Tile_X0Y0_FrameStrobe_O[11]
    DIRECTION OUTPUT ;
    USE SIGNAL ;
    ANTENNADIFFAREA 2.724000 ;
    PORT
      LAYER Metal2 ;
        RECT 80.920 459.920 81.320 460.320 ;
    END
  END Tile_X0Y0_FrameStrobe_O[11]
  PIN Tile_X0Y0_FrameStrobe_O[12]
    DIRECTION OUTPUT ;
    USE SIGNAL ;
    ANTENNADIFFAREA 2.724000 ;
    PORT
      LAYER Metal2 ;
        RECT 81.880 459.920 82.280 460.320 ;
    END
  END Tile_X0Y0_FrameStrobe_O[12]
  PIN Tile_X0Y0_FrameStrobe_O[13]
    DIRECTION OUTPUT ;
    USE SIGNAL ;
    ANTENNADIFFAREA 2.724000 ;
    PORT
      LAYER Metal2 ;
        RECT 82.840 459.920 83.240 460.320 ;
    END
  END Tile_X0Y0_FrameStrobe_O[13]
  PIN Tile_X0Y0_FrameStrobe_O[14]
    DIRECTION OUTPUT ;
    USE SIGNAL ;
    ANTENNADIFFAREA 2.724000 ;
    PORT
      LAYER Metal2 ;
        RECT 83.800 459.920 84.200 460.320 ;
    END
  END Tile_X0Y0_FrameStrobe_O[14]
  PIN Tile_X0Y0_FrameStrobe_O[15]
    DIRECTION OUTPUT ;
    USE SIGNAL ;
    ANTENNADIFFAREA 2.724000 ;
    PORT
      LAYER Metal2 ;
        RECT 84.760 459.920 85.160 460.320 ;
    END
  END Tile_X0Y0_FrameStrobe_O[15]
  PIN Tile_X0Y0_FrameStrobe_O[16]
    DIRECTION OUTPUT ;
    USE SIGNAL ;
    ANTENNADIFFAREA 2.724000 ;
    PORT
      LAYER Metal2 ;
        RECT 85.720 459.920 86.120 460.320 ;
    END
  END Tile_X0Y0_FrameStrobe_O[16]
  PIN Tile_X0Y0_FrameStrobe_O[17]
    DIRECTION OUTPUT ;
    USE SIGNAL ;
    ANTENNADIFFAREA 2.724000 ;
    PORT
      LAYER Metal2 ;
        RECT 86.680 459.920 87.080 460.320 ;
    END
  END Tile_X0Y0_FrameStrobe_O[17]
  PIN Tile_X0Y0_FrameStrobe_O[18]
    DIRECTION OUTPUT ;
    USE SIGNAL ;
    ANTENNADIFFAREA 2.724000 ;
    PORT
      LAYER Metal2 ;
        RECT 87.640 459.920 88.040 460.320 ;
    END
  END Tile_X0Y0_FrameStrobe_O[18]
  PIN Tile_X0Y0_FrameStrobe_O[19]
    DIRECTION OUTPUT ;
    USE SIGNAL ;
    ANTENNADIFFAREA 2.724000 ;
    PORT
      LAYER Metal2 ;
        RECT 88.600 459.920 89.000 460.320 ;
    END
  END Tile_X0Y0_FrameStrobe_O[19]
  PIN Tile_X0Y0_FrameStrobe_O[1]
    DIRECTION OUTPUT ;
    USE SIGNAL ;
    ANTENNADIFFAREA 2.724000 ;
    PORT
      LAYER Metal2 ;
        RECT 71.320 459.920 71.720 460.320 ;
    END
  END Tile_X0Y0_FrameStrobe_O[1]
  PIN Tile_X0Y0_FrameStrobe_O[2]
    DIRECTION OUTPUT ;
    USE SIGNAL ;
    ANTENNADIFFAREA 2.724000 ;
    PORT
      LAYER Metal2 ;
        RECT 72.280 459.920 72.680 460.320 ;
    END
  END Tile_X0Y0_FrameStrobe_O[2]
  PIN Tile_X0Y0_FrameStrobe_O[3]
    DIRECTION OUTPUT ;
    USE SIGNAL ;
    ANTENNADIFFAREA 2.724000 ;
    PORT
      LAYER Metal2 ;
        RECT 73.240 459.920 73.640 460.320 ;
    END
  END Tile_X0Y0_FrameStrobe_O[3]
  PIN Tile_X0Y0_FrameStrobe_O[4]
    DIRECTION OUTPUT ;
    USE SIGNAL ;
    ANTENNADIFFAREA 2.724000 ;
    PORT
      LAYER Metal2 ;
        RECT 74.200 459.920 74.600 460.320 ;
    END
  END Tile_X0Y0_FrameStrobe_O[4]
  PIN Tile_X0Y0_FrameStrobe_O[5]
    DIRECTION OUTPUT ;
    USE SIGNAL ;
    ANTENNADIFFAREA 2.724000 ;
    PORT
      LAYER Metal2 ;
        RECT 75.160 459.920 75.560 460.320 ;
    END
  END Tile_X0Y0_FrameStrobe_O[5]
  PIN Tile_X0Y0_FrameStrobe_O[6]
    DIRECTION OUTPUT ;
    USE SIGNAL ;
    ANTENNADIFFAREA 2.724000 ;
    PORT
      LAYER Metal2 ;
        RECT 76.120 459.920 76.520 460.320 ;
    END
  END Tile_X0Y0_FrameStrobe_O[6]
  PIN Tile_X0Y0_FrameStrobe_O[7]
    DIRECTION OUTPUT ;
    USE SIGNAL ;
    ANTENNADIFFAREA 2.724000 ;
    PORT
      LAYER Metal2 ;
        RECT 77.080 459.920 77.480 460.320 ;
    END
  END Tile_X0Y0_FrameStrobe_O[7]
  PIN Tile_X0Y0_FrameStrobe_O[8]
    DIRECTION OUTPUT ;
    USE SIGNAL ;
    ANTENNADIFFAREA 2.724000 ;
    PORT
      LAYER Metal2 ;
        RECT 78.040 459.920 78.440 460.320 ;
    END
  END Tile_X0Y0_FrameStrobe_O[8]
  PIN Tile_X0Y0_FrameStrobe_O[9]
    DIRECTION OUTPUT ;
    USE SIGNAL ;
    ANTENNADIFFAREA 2.724000 ;
    PORT
      LAYER Metal2 ;
        RECT 79.000 459.920 79.400 460.320 ;
    END
  END Tile_X0Y0_FrameStrobe_O[9]
  PIN Tile_X0Y0_N1BEG[0]
    DIRECTION OUTPUT ;
    USE SIGNAL ;
    ANTENNADIFFAREA 2.724000 ;
    PORT
      LAYER Metal2 ;
        RECT 1.240 459.920 1.640 460.320 ;
    END
  END Tile_X0Y0_N1BEG[0]
  PIN Tile_X0Y0_N1BEG[1]
    DIRECTION OUTPUT ;
    USE SIGNAL ;
    ANTENNADIFFAREA 2.724000 ;
    PORT
      LAYER Metal2 ;
        RECT 2.200 459.920 2.600 460.320 ;
    END
  END Tile_X0Y0_N1BEG[1]
  PIN Tile_X0Y0_N1BEG[2]
    DIRECTION OUTPUT ;
    USE SIGNAL ;
    ANTENNADIFFAREA 2.724000 ;
    PORT
      LAYER Metal2 ;
        RECT 3.160 459.920 3.560 460.320 ;
    END
  END Tile_X0Y0_N1BEG[2]
  PIN Tile_X0Y0_N1BEG[3]
    DIRECTION OUTPUT ;
    USE SIGNAL ;
    ANTENNADIFFAREA 2.724000 ;
    PORT
      LAYER Metal2 ;
        RECT 4.120 459.920 4.520 460.320 ;
    END
  END Tile_X0Y0_N1BEG[3]
  PIN Tile_X0Y0_N2BEG[0]
    DIRECTION OUTPUT ;
    USE SIGNAL ;
    ANTENNADIFFAREA 2.724000 ;
    PORT
      LAYER Metal2 ;
        RECT 5.080 459.920 5.480 460.320 ;
    END
  END Tile_X0Y0_N2BEG[0]
  PIN Tile_X0Y0_N2BEG[1]
    DIRECTION OUTPUT ;
    USE SIGNAL ;
    ANTENNADIFFAREA 2.724000 ;
    PORT
      LAYER Metal2 ;
        RECT 6.040 459.920 6.440 460.320 ;
    END
  END Tile_X0Y0_N2BEG[1]
  PIN Tile_X0Y0_N2BEG[2]
    DIRECTION OUTPUT ;
    USE SIGNAL ;
    ANTENNADIFFAREA 2.724000 ;
    PORT
      LAYER Metal2 ;
        RECT 7.000 459.920 7.400 460.320 ;
    END
  END Tile_X0Y0_N2BEG[2]
  PIN Tile_X0Y0_N2BEG[3]
    DIRECTION OUTPUT ;
    USE SIGNAL ;
    ANTENNADIFFAREA 2.724000 ;
    PORT
      LAYER Metal2 ;
        RECT 7.960 459.920 8.360 460.320 ;
    END
  END Tile_X0Y0_N2BEG[3]
  PIN Tile_X0Y0_N2BEG[4]
    DIRECTION OUTPUT ;
    USE SIGNAL ;
    ANTENNADIFFAREA 2.724000 ;
    PORT
      LAYER Metal2 ;
        RECT 8.920 459.920 9.320 460.320 ;
    END
  END Tile_X0Y0_N2BEG[4]
  PIN Tile_X0Y0_N2BEG[5]
    DIRECTION OUTPUT ;
    USE SIGNAL ;
    ANTENNADIFFAREA 2.724000 ;
    PORT
      LAYER Metal2 ;
        RECT 9.880 459.920 10.280 460.320 ;
    END
  END Tile_X0Y0_N2BEG[5]
  PIN Tile_X0Y0_N2BEG[6]
    DIRECTION OUTPUT ;
    USE SIGNAL ;
    ANTENNADIFFAREA 2.724000 ;
    PORT
      LAYER Metal2 ;
        RECT 10.840 459.920 11.240 460.320 ;
    END
  END Tile_X0Y0_N2BEG[6]
  PIN Tile_X0Y0_N2BEG[7]
    DIRECTION OUTPUT ;
    USE SIGNAL ;
    ANTENNADIFFAREA 2.724000 ;
    PORT
      LAYER Metal2 ;
        RECT 11.800 459.920 12.200 460.320 ;
    END
  END Tile_X0Y0_N2BEG[7]
  PIN Tile_X0Y0_N2BEGb[0]
    DIRECTION OUTPUT ;
    USE SIGNAL ;
    ANTENNADIFFAREA 2.724000 ;
    PORT
      LAYER Metal2 ;
        RECT 12.760 459.920 13.160 460.320 ;
    END
  END Tile_X0Y0_N2BEGb[0]
  PIN Tile_X0Y0_N2BEGb[1]
    DIRECTION OUTPUT ;
    USE SIGNAL ;
    ANTENNADIFFAREA 2.724000 ;
    PORT
      LAYER Metal2 ;
        RECT 13.720 459.920 14.120 460.320 ;
    END
  END Tile_X0Y0_N2BEGb[1]
  PIN Tile_X0Y0_N2BEGb[2]
    DIRECTION OUTPUT ;
    USE SIGNAL ;
    ANTENNADIFFAREA 2.724000 ;
    PORT
      LAYER Metal2 ;
        RECT 14.680 459.920 15.080 460.320 ;
    END
  END Tile_X0Y0_N2BEGb[2]
  PIN Tile_X0Y0_N2BEGb[3]
    DIRECTION OUTPUT ;
    USE SIGNAL ;
    ANTENNADIFFAREA 2.724000 ;
    PORT
      LAYER Metal2 ;
        RECT 15.640 459.920 16.040 460.320 ;
    END
  END Tile_X0Y0_N2BEGb[3]
  PIN Tile_X0Y0_N2BEGb[4]
    DIRECTION OUTPUT ;
    USE SIGNAL ;
    ANTENNADIFFAREA 2.724000 ;
    PORT
      LAYER Metal2 ;
        RECT 16.600 459.920 17.000 460.320 ;
    END
  END Tile_X0Y0_N2BEGb[4]
  PIN Tile_X0Y0_N2BEGb[5]
    DIRECTION OUTPUT ;
    USE SIGNAL ;
    ANTENNADIFFAREA 2.724000 ;
    PORT
      LAYER Metal2 ;
        RECT 17.560 459.920 17.960 460.320 ;
    END
  END Tile_X0Y0_N2BEGb[5]
  PIN Tile_X0Y0_N2BEGb[6]
    DIRECTION OUTPUT ;
    USE SIGNAL ;
    ANTENNADIFFAREA 2.724000 ;
    PORT
      LAYER Metal2 ;
        RECT 18.520 459.920 18.920 460.320 ;
    END
  END Tile_X0Y0_N2BEGb[6]
  PIN Tile_X0Y0_N2BEGb[7]
    DIRECTION OUTPUT ;
    USE SIGNAL ;
    ANTENNADIFFAREA 2.724000 ;
    PORT
      LAYER Metal2 ;
        RECT 19.480 459.920 19.880 460.320 ;
    END
  END Tile_X0Y0_N2BEGb[7]
  PIN Tile_X0Y0_N4BEG[0]
    DIRECTION OUTPUT ;
    USE SIGNAL ;
    ANTENNADIFFAREA 2.724000 ;
    PORT
      LAYER Metal2 ;
        RECT 20.440 459.920 20.840 460.320 ;
    END
  END Tile_X0Y0_N4BEG[0]
  PIN Tile_X0Y0_N4BEG[10]
    DIRECTION OUTPUT ;
    USE SIGNAL ;
    ANTENNADIFFAREA 2.724000 ;
    PORT
      LAYER Metal2 ;
        RECT 30.040 459.920 30.440 460.320 ;
    END
  END Tile_X0Y0_N4BEG[10]
  PIN Tile_X0Y0_N4BEG[11]
    DIRECTION OUTPUT ;
    USE SIGNAL ;
    ANTENNADIFFAREA 2.724000 ;
    PORT
      LAYER Metal2 ;
        RECT 31.000 459.920 31.400 460.320 ;
    END
  END Tile_X0Y0_N4BEG[11]
  PIN Tile_X0Y0_N4BEG[12]
    DIRECTION OUTPUT ;
    USE SIGNAL ;
    ANTENNADIFFAREA 2.724000 ;
    PORT
      LAYER Metal2 ;
        RECT 31.960 459.920 32.360 460.320 ;
    END
  END Tile_X0Y0_N4BEG[12]
  PIN Tile_X0Y0_N4BEG[13]
    DIRECTION OUTPUT ;
    USE SIGNAL ;
    ANTENNADIFFAREA 2.724000 ;
    PORT
      LAYER Metal2 ;
        RECT 32.920 459.920 33.320 460.320 ;
    END
  END Tile_X0Y0_N4BEG[13]
  PIN Tile_X0Y0_N4BEG[14]
    DIRECTION OUTPUT ;
    USE SIGNAL ;
    ANTENNADIFFAREA 2.724000 ;
    PORT
      LAYER Metal2 ;
        RECT 33.880 459.920 34.280 460.320 ;
    END
  END Tile_X0Y0_N4BEG[14]
  PIN Tile_X0Y0_N4BEG[15]
    DIRECTION OUTPUT ;
    USE SIGNAL ;
    ANTENNADIFFAREA 2.724000 ;
    PORT
      LAYER Metal2 ;
        RECT 34.840 459.920 35.240 460.320 ;
    END
  END Tile_X0Y0_N4BEG[15]
  PIN Tile_X0Y0_N4BEG[1]
    DIRECTION OUTPUT ;
    USE SIGNAL ;
    ANTENNADIFFAREA 2.724000 ;
    PORT
      LAYER Metal2 ;
        RECT 21.400 459.920 21.800 460.320 ;
    END
  END Tile_X0Y0_N4BEG[1]
  PIN Tile_X0Y0_N4BEG[2]
    DIRECTION OUTPUT ;
    USE SIGNAL ;
    ANTENNADIFFAREA 2.724000 ;
    PORT
      LAYER Metal2 ;
        RECT 22.360 459.920 22.760 460.320 ;
    END
  END Tile_X0Y0_N4BEG[2]
  PIN Tile_X0Y0_N4BEG[3]
    DIRECTION OUTPUT ;
    USE SIGNAL ;
    ANTENNADIFFAREA 2.724000 ;
    PORT
      LAYER Metal2 ;
        RECT 23.320 459.920 23.720 460.320 ;
    END
  END Tile_X0Y0_N4BEG[3]
  PIN Tile_X0Y0_N4BEG[4]
    DIRECTION OUTPUT ;
    USE SIGNAL ;
    ANTENNADIFFAREA 2.724000 ;
    PORT
      LAYER Metal2 ;
        RECT 24.280 459.920 24.680 460.320 ;
    END
  END Tile_X0Y0_N4BEG[4]
  PIN Tile_X0Y0_N4BEG[5]
    DIRECTION OUTPUT ;
    USE SIGNAL ;
    ANTENNADIFFAREA 2.724000 ;
    PORT
      LAYER Metal2 ;
        RECT 25.240 459.920 25.640 460.320 ;
    END
  END Tile_X0Y0_N4BEG[5]
  PIN Tile_X0Y0_N4BEG[6]
    DIRECTION OUTPUT ;
    USE SIGNAL ;
    ANTENNADIFFAREA 2.724000 ;
    PORT
      LAYER Metal2 ;
        RECT 26.200 459.920 26.600 460.320 ;
    END
  END Tile_X0Y0_N4BEG[6]
  PIN Tile_X0Y0_N4BEG[7]
    DIRECTION OUTPUT ;
    USE SIGNAL ;
    ANTENNADIFFAREA 2.724000 ;
    PORT
      LAYER Metal2 ;
        RECT 27.160 459.920 27.560 460.320 ;
    END
  END Tile_X0Y0_N4BEG[7]
  PIN Tile_X0Y0_N4BEG[8]
    DIRECTION OUTPUT ;
    USE SIGNAL ;
    ANTENNADIFFAREA 2.724000 ;
    PORT
      LAYER Metal2 ;
        RECT 28.120 459.920 28.520 460.320 ;
    END
  END Tile_X0Y0_N4BEG[8]
  PIN Tile_X0Y0_N4BEG[9]
    DIRECTION OUTPUT ;
    USE SIGNAL ;
    ANTENNADIFFAREA 2.724000 ;
    PORT
      LAYER Metal2 ;
        RECT 29.080 459.920 29.480 460.320 ;
    END
  END Tile_X0Y0_N4BEG[9]
  PIN Tile_X0Y0_S1END[0]
    DIRECTION INPUT ;
    USE SIGNAL ;
    ANTENNAGATEAREA 1.279200 ;
    ANTENNADIFFAREA 12.092400 ;
    PORT
      LAYER Metal2 ;
        RECT 35.800 459.920 36.200 460.320 ;
    END
  END Tile_X0Y0_S1END[0]
  PIN Tile_X0Y0_S1END[1]
    DIRECTION INPUT ;
    USE SIGNAL ;
    ANTENNAGATEAREA 1.279200 ;
    ANTENNADIFFAREA 12.092400 ;
    PORT
      LAYER Metal2 ;
        RECT 36.760 459.920 37.160 460.320 ;
    END
  END Tile_X0Y0_S1END[1]
  PIN Tile_X0Y0_S1END[2]
    DIRECTION INPUT ;
    USE SIGNAL ;
    ANTENNAGATEAREA 1.279200 ;
    ANTENNADIFFAREA 12.092400 ;
    PORT
      LAYER Metal2 ;
        RECT 37.720 459.920 38.120 460.320 ;
    END
  END Tile_X0Y0_S1END[2]
  PIN Tile_X0Y0_S1END[3]
    DIRECTION INPUT ;
    USE SIGNAL ;
    ANTENNAGATEAREA 1.279200 ;
    ANTENNADIFFAREA 12.092400 ;
    PORT
      LAYER Metal2 ;
        RECT 38.680 459.920 39.080 460.320 ;
    END
  END Tile_X0Y0_S1END[3]
  PIN Tile_X0Y0_S2END[0]
    DIRECTION INPUT ;
    USE SIGNAL ;
    ANTENNAGATEAREA 0.213200 ;
    ANTENNADIFFAREA 2.015400 ;
    PORT
      LAYER Metal2 ;
        RECT 47.320 459.920 47.720 460.320 ;
    END
  END Tile_X0Y0_S2END[0]
  PIN Tile_X0Y0_S2END[1]
    DIRECTION INPUT ;
    USE SIGNAL ;
    ANTENNAGATEAREA 0.213200 ;
    ANTENNADIFFAREA 2.015400 ;
    PORT
      LAYER Metal2 ;
        RECT 48.280 459.920 48.680 460.320 ;
    END
  END Tile_X0Y0_S2END[1]
  PIN Tile_X0Y0_S2END[2]
    DIRECTION INPUT ;
    USE SIGNAL ;
    ANTENNAGATEAREA 0.213200 ;
    ANTENNADIFFAREA 2.015400 ;
    PORT
      LAYER Metal2 ;
        RECT 49.240 459.920 49.640 460.320 ;
    END
  END Tile_X0Y0_S2END[2]
  PIN Tile_X0Y0_S2END[3]
    DIRECTION INPUT ;
    USE SIGNAL ;
    ANTENNAGATEAREA 0.213200 ;
    ANTENNADIFFAREA 2.015400 ;
    PORT
      LAYER Metal2 ;
        RECT 50.200 459.920 50.600 460.320 ;
    END
  END Tile_X0Y0_S2END[3]
  PIN Tile_X0Y0_S2END[4]
    DIRECTION INPUT ;
    USE SIGNAL ;
    ANTENNAGATEAREA 0.213200 ;
    ANTENNADIFFAREA 2.015400 ;
    PORT
      LAYER Metal2 ;
        RECT 51.160 459.920 51.560 460.320 ;
    END
  END Tile_X0Y0_S2END[4]
  PIN Tile_X0Y0_S2END[5]
    DIRECTION INPUT ;
    USE SIGNAL ;
    ANTENNAGATEAREA 0.213200 ;
    ANTENNADIFFAREA 2.015400 ;
    PORT
      LAYER Metal2 ;
        RECT 52.120 459.920 52.520 460.320 ;
    END
  END Tile_X0Y0_S2END[5]
  PIN Tile_X0Y0_S2END[6]
    DIRECTION INPUT ;
    USE SIGNAL ;
    ANTENNAGATEAREA 0.213200 ;
    ANTENNADIFFAREA 2.015400 ;
    PORT
      LAYER Metal2 ;
        RECT 53.080 459.920 53.480 460.320 ;
    END
  END Tile_X0Y0_S2END[6]
  PIN Tile_X0Y0_S2END[7]
    DIRECTION INPUT ;
    USE SIGNAL ;
    ANTENNAGATEAREA 0.213200 ;
    ANTENNADIFFAREA 2.015400 ;
    PORT
      LAYER Metal2 ;
        RECT 54.040 459.920 54.440 460.320 ;
    END
  END Tile_X0Y0_S2END[7]
  PIN Tile_X0Y0_S2MID[0]
    DIRECTION INPUT ;
    USE SIGNAL ;
    ANTENNAGATEAREA 0.426400 ;
    ANTENNADIFFAREA 4.030800 ;
    PORT
      LAYER Metal2 ;
        RECT 39.640 459.920 40.040 460.320 ;
    END
  END Tile_X0Y0_S2MID[0]
  PIN Tile_X0Y0_S2MID[1]
    DIRECTION INPUT ;
    USE SIGNAL ;
    ANTENNAGATEAREA 0.426400 ;
    ANTENNADIFFAREA 4.030800 ;
    PORT
      LAYER Metal2 ;
        RECT 40.600 459.920 41.000 460.320 ;
    END
  END Tile_X0Y0_S2MID[1]
  PIN Tile_X0Y0_S2MID[2]
    DIRECTION INPUT ;
    USE SIGNAL ;
    ANTENNAGATEAREA 0.426400 ;
    ANTENNADIFFAREA 4.030800 ;
    PORT
      LAYER Metal2 ;
        RECT 41.560 459.920 41.960 460.320 ;
    END
  END Tile_X0Y0_S2MID[2]
  PIN Tile_X0Y0_S2MID[3]
    DIRECTION INPUT ;
    USE SIGNAL ;
    ANTENNAGATEAREA 0.426400 ;
    ANTENNADIFFAREA 4.030800 ;
    PORT
      LAYER Metal2 ;
        RECT 42.520 459.920 42.920 460.320 ;
    END
  END Tile_X0Y0_S2MID[3]
  PIN Tile_X0Y0_S2MID[4]
    DIRECTION INPUT ;
    USE SIGNAL ;
    ANTENNAGATEAREA 0.426400 ;
    ANTENNADIFFAREA 4.030800 ;
    PORT
      LAYER Metal2 ;
        RECT 43.480 459.920 43.880 460.320 ;
    END
  END Tile_X0Y0_S2MID[4]
  PIN Tile_X0Y0_S2MID[5]
    DIRECTION INPUT ;
    USE SIGNAL ;
    ANTENNAGATEAREA 0.426400 ;
    ANTENNADIFFAREA 4.030800 ;
    PORT
      LAYER Metal2 ;
        RECT 44.440 459.920 44.840 460.320 ;
    END
  END Tile_X0Y0_S2MID[5]
  PIN Tile_X0Y0_S2MID[6]
    DIRECTION INPUT ;
    USE SIGNAL ;
    ANTENNAGATEAREA 0.426400 ;
    ANTENNADIFFAREA 4.030800 ;
    PORT
      LAYER Metal2 ;
        RECT 45.400 459.920 45.800 460.320 ;
    END
  END Tile_X0Y0_S2MID[6]
  PIN Tile_X0Y0_S2MID[7]
    DIRECTION INPUT ;
    USE SIGNAL ;
    ANTENNAGATEAREA 0.426400 ;
    ANTENNADIFFAREA 4.030800 ;
    PORT
      LAYER Metal2 ;
        RECT 46.360 459.920 46.760 460.320 ;
    END
  END Tile_X0Y0_S2MID[7]
  PIN Tile_X0Y0_S4END[0]
    DIRECTION INPUT ;
    USE SIGNAL ;
    ANTENNAGATEAREA 1.066000 ;
    ANTENNADIFFAREA 10.077000 ;
    PORT
      LAYER Metal2 ;
        RECT 55.000 459.920 55.400 460.320 ;
    END
  END Tile_X0Y0_S4END[0]
  PIN Tile_X0Y0_S4END[10]
    DIRECTION INPUT ;
    USE SIGNAL ;
    ANTENNAGATEAREA 0.180700 ;
    ANTENNADIFFAREA 2.015400 ;
    PORT
      LAYER Metal2 ;
        RECT 64.600 459.920 65.000 460.320 ;
    END
  END Tile_X0Y0_S4END[10]
  PIN Tile_X0Y0_S4END[11]
    DIRECTION INPUT ;
    USE SIGNAL ;
    ANTENNAGATEAREA 0.180700 ;
    ANTENNADIFFAREA 2.015400 ;
    PORT
      LAYER Metal2 ;
        RECT 65.560 459.920 65.960 460.320 ;
    END
  END Tile_X0Y0_S4END[11]
  PIN Tile_X0Y0_S4END[12]
    DIRECTION INPUT ;
    USE SIGNAL ;
    ANTENNAGATEAREA 0.180700 ;
    ANTENNADIFFAREA 2.015400 ;
    PORT
      LAYER Metal2 ;
        RECT 66.520 459.920 66.920 460.320 ;
    END
  END Tile_X0Y0_S4END[12]
  PIN Tile_X0Y0_S4END[13]
    DIRECTION INPUT ;
    USE SIGNAL ;
    ANTENNAGATEAREA 0.180700 ;
    ANTENNADIFFAREA 2.015400 ;
    PORT
      LAYER Metal2 ;
        RECT 67.480 459.920 67.880 460.320 ;
    END
  END Tile_X0Y0_S4END[13]
  PIN Tile_X0Y0_S4END[14]
    DIRECTION INPUT ;
    USE SIGNAL ;
    ANTENNAGATEAREA 0.180700 ;
    ANTENNADIFFAREA 2.015400 ;
    PORT
      LAYER Metal2 ;
        RECT 68.440 459.920 68.840 460.320 ;
    END
  END Tile_X0Y0_S4END[14]
  PIN Tile_X0Y0_S4END[15]
    DIRECTION INPUT ;
    USE SIGNAL ;
    ANTENNAGATEAREA 0.180700 ;
    ANTENNADIFFAREA 2.015400 ;
    PORT
      LAYER Metal2 ;
        RECT 69.400 459.920 69.800 460.320 ;
    END
  END Tile_X0Y0_S4END[15]
  PIN Tile_X0Y0_S4END[1]
    DIRECTION INPUT ;
    USE SIGNAL ;
    ANTENNAGATEAREA 1.066000 ;
    ANTENNADIFFAREA 10.077000 ;
    PORT
      LAYER Metal2 ;
        RECT 55.960 459.920 56.360 460.320 ;
    END
  END Tile_X0Y0_S4END[1]
  PIN Tile_X0Y0_S4END[2]
    DIRECTION INPUT ;
    USE SIGNAL ;
    ANTENNAGATEAREA 1.066000 ;
    ANTENNADIFFAREA 10.077000 ;
    PORT
      LAYER Metal2 ;
        RECT 56.920 459.920 57.320 460.320 ;
    END
  END Tile_X0Y0_S4END[2]
  PIN Tile_X0Y0_S4END[3]
    DIRECTION INPUT ;
    USE SIGNAL ;
    ANTENNAGATEAREA 1.066000 ;
    ANTENNADIFFAREA 10.077000 ;
    PORT
      LAYER Metal2 ;
        RECT 57.880 459.920 58.280 460.320 ;
    END
  END Tile_X0Y0_S4END[3]
  PIN Tile_X0Y0_S4END[4]
    DIRECTION INPUT ;
    USE SIGNAL ;
    ANTENNAGATEAREA 1.066000 ;
    ANTENNADIFFAREA 10.077000 ;
    PORT
      LAYER Metal2 ;
        RECT 58.840 459.920 59.240 460.320 ;
    END
  END Tile_X0Y0_S4END[4]
  PIN Tile_X0Y0_S4END[5]
    DIRECTION INPUT ;
    USE SIGNAL ;
    ANTENNAGATEAREA 1.066000 ;
    ANTENNADIFFAREA 10.077000 ;
    PORT
      LAYER Metal2 ;
        RECT 59.800 459.920 60.200 460.320 ;
    END
  END Tile_X0Y0_S4END[5]
  PIN Tile_X0Y0_S4END[6]
    DIRECTION INPUT ;
    USE SIGNAL ;
    ANTENNAGATEAREA 1.066000 ;
    ANTENNADIFFAREA 10.077000 ;
    PORT
      LAYER Metal2 ;
        RECT 60.760 459.920 61.160 460.320 ;
    END
  END Tile_X0Y0_S4END[6]
  PIN Tile_X0Y0_S4END[7]
    DIRECTION INPUT ;
    USE SIGNAL ;
    ANTENNAGATEAREA 1.066000 ;
    ANTENNADIFFAREA 10.077000 ;
    PORT
      LAYER Metal2 ;
        RECT 61.720 459.920 62.120 460.320 ;
    END
  END Tile_X0Y0_S4END[7]
  PIN Tile_X0Y0_S4END[8]
    DIRECTION INPUT ;
    USE SIGNAL ;
    ANTENNAGATEAREA 0.180700 ;
    ANTENNADIFFAREA 2.015400 ;
    PORT
      LAYER Metal2 ;
        RECT 62.680 459.920 63.080 460.320 ;
    END
  END Tile_X0Y0_S4END[8]
  PIN Tile_X0Y0_S4END[9]
    DIRECTION INPUT ;
    USE SIGNAL ;
    ANTENNAGATEAREA 0.180700 ;
    ANTENNADIFFAREA 2.015400 ;
    PORT
      LAYER Metal2 ;
        RECT 63.640 459.920 64.040 460.320 ;
    END
  END Tile_X0Y0_S4END[9]
  PIN Tile_X0Y0_UserCLK
    DIRECTION INPUT ;
    USE SIGNAL ;
    ANTENNAGATEAREA 0.180700 ;
    ANTENNADIFFAREA 2.015400 ;
    PORT
      LAYER Metal3 ;
        RECT 0.000 401.740 0.400 402.140 ;
    END
  END Tile_X0Y0_UserCLK
  PIN Tile_X0Y0_UserCLKo
    DIRECTION OUTPUT ;
    USE SIGNAL ;
    ANTENNADIFFAREA 2.724000 ;
    PORT
      LAYER Metal3 ;
        RECT 88.880 233.740 89.280 234.140 ;
    END
  END Tile_X0Y0_UserCLKo
  PIN Tile_X0Y0_W1BEG[0]
    DIRECTION OUTPUT ;
    USE SIGNAL ;
    ANTENNADIFFAREA 2.724000 ;
    PORT
      LAYER Metal3 ;
        RECT 0.000 316.060 0.400 316.460 ;
    END
  END Tile_X0Y0_W1BEG[0]
  PIN Tile_X0Y0_W1BEG[1]
    DIRECTION OUTPUT ;
    USE SIGNAL ;
    ANTENNADIFFAREA 2.724000 ;
    PORT
      LAYER Metal3 ;
        RECT 0.000 317.740 0.400 318.140 ;
    END
  END Tile_X0Y0_W1BEG[1]
  PIN Tile_X0Y0_W1BEG[2]
    DIRECTION OUTPUT ;
    USE SIGNAL ;
    ANTENNADIFFAREA 2.724000 ;
    PORT
      LAYER Metal3 ;
        RECT 0.000 319.420 0.400 319.820 ;
    END
  END Tile_X0Y0_W1BEG[2]
  PIN Tile_X0Y0_W1BEG[3]
    DIRECTION OUTPUT ;
    USE SIGNAL ;
    ANTENNADIFFAREA 2.724000 ;
    PORT
      LAYER Metal3 ;
        RECT 0.000 321.100 0.400 321.500 ;
    END
  END Tile_X0Y0_W1BEG[3]
  PIN Tile_X0Y0_W2BEG[0]
    DIRECTION OUTPUT ;
    USE SIGNAL ;
    ANTENNADIFFAREA 2.724000 ;
    PORT
      LAYER Metal3 ;
        RECT 0.000 323.620 0.400 324.020 ;
    END
  END Tile_X0Y0_W2BEG[0]
  PIN Tile_X0Y0_W2BEG[1]
    DIRECTION OUTPUT ;
    USE SIGNAL ;
    ANTENNADIFFAREA 2.724000 ;
    PORT
      LAYER Metal3 ;
        RECT 0.000 325.300 0.400 325.700 ;
    END
  END Tile_X0Y0_W2BEG[1]
  PIN Tile_X0Y0_W2BEG[2]
    DIRECTION OUTPUT ;
    USE SIGNAL ;
    ANTENNADIFFAREA 2.724000 ;
    PORT
      LAYER Metal3 ;
        RECT 0.000 326.980 0.400 327.380 ;
    END
  END Tile_X0Y0_W2BEG[2]
  PIN Tile_X0Y0_W2BEG[3]
    DIRECTION OUTPUT ;
    USE SIGNAL ;
    ANTENNADIFFAREA 2.724000 ;
    PORT
      LAYER Metal3 ;
        RECT 0.000 328.660 0.400 329.060 ;
    END
  END Tile_X0Y0_W2BEG[3]
  PIN Tile_X0Y0_W2BEG[4]
    DIRECTION OUTPUT ;
    USE SIGNAL ;
    ANTENNADIFFAREA 2.724000 ;
    PORT
      LAYER Metal3 ;
        RECT 0.000 330.340 0.400 330.740 ;
    END
  END Tile_X0Y0_W2BEG[4]
  PIN Tile_X0Y0_W2BEG[5]
    DIRECTION OUTPUT ;
    USE SIGNAL ;
    ANTENNADIFFAREA 2.724000 ;
    PORT
      LAYER Metal3 ;
        RECT 0.000 332.020 0.400 332.420 ;
    END
  END Tile_X0Y0_W2BEG[5]
  PIN Tile_X0Y0_W2BEG[6]
    DIRECTION OUTPUT ;
    USE SIGNAL ;
    ANTENNADIFFAREA 2.724000 ;
    PORT
      LAYER Metal3 ;
        RECT 0.000 333.700 0.400 334.100 ;
    END
  END Tile_X0Y0_W2BEG[6]
  PIN Tile_X0Y0_W2BEG[7]
    DIRECTION OUTPUT ;
    USE SIGNAL ;
    ANTENNADIFFAREA 2.724000 ;
    PORT
      LAYER Metal3 ;
        RECT 0.000 335.380 0.400 335.780 ;
    END
  END Tile_X0Y0_W2BEG[7]
  PIN Tile_X0Y0_W2BEGb[0]
    DIRECTION OUTPUT ;
    USE SIGNAL ;
    ANTENNADIFFAREA 2.724000 ;
    PORT
      LAYER Metal3 ;
        RECT 0.000 337.900 0.400 338.300 ;
    END
  END Tile_X0Y0_W2BEGb[0]
  PIN Tile_X0Y0_W2BEGb[1]
    DIRECTION OUTPUT ;
    USE SIGNAL ;
    ANTENNADIFFAREA 2.724000 ;
    PORT
      LAYER Metal3 ;
        RECT 0.000 339.580 0.400 339.980 ;
    END
  END Tile_X0Y0_W2BEGb[1]
  PIN Tile_X0Y0_W2BEGb[2]
    DIRECTION OUTPUT ;
    USE SIGNAL ;
    ANTENNADIFFAREA 2.724000 ;
    PORT
      LAYER Metal3 ;
        RECT 0.000 341.260 0.400 341.660 ;
    END
  END Tile_X0Y0_W2BEGb[2]
  PIN Tile_X0Y0_W2BEGb[3]
    DIRECTION OUTPUT ;
    USE SIGNAL ;
    ANTENNADIFFAREA 2.724000 ;
    PORT
      LAYER Metal3 ;
        RECT 0.000 342.940 0.400 343.340 ;
    END
  END Tile_X0Y0_W2BEGb[3]
  PIN Tile_X0Y0_W2BEGb[4]
    DIRECTION OUTPUT ;
    USE SIGNAL ;
    ANTENNADIFFAREA 2.724000 ;
    PORT
      LAYER Metal3 ;
        RECT 0.000 344.620 0.400 345.020 ;
    END
  END Tile_X0Y0_W2BEGb[4]
  PIN Tile_X0Y0_W2BEGb[5]
    DIRECTION OUTPUT ;
    USE SIGNAL ;
    ANTENNADIFFAREA 2.724000 ;
    PORT
      LAYER Metal3 ;
        RECT 0.000 346.300 0.400 346.700 ;
    END
  END Tile_X0Y0_W2BEGb[5]
  PIN Tile_X0Y0_W2BEGb[6]
    DIRECTION OUTPUT ;
    USE SIGNAL ;
    ANTENNADIFFAREA 2.724000 ;
    PORT
      LAYER Metal3 ;
        RECT 0.000 347.980 0.400 348.380 ;
    END
  END Tile_X0Y0_W2BEGb[6]
  PIN Tile_X0Y0_W2BEGb[7]
    DIRECTION OUTPUT ;
    USE SIGNAL ;
    ANTENNADIFFAREA 2.724000 ;
    PORT
      LAYER Metal3 ;
        RECT 0.000 349.660 0.400 350.060 ;
    END
  END Tile_X0Y0_W2BEGb[7]
  PIN Tile_X0Y0_W6BEG[0]
    DIRECTION OUTPUT ;
    USE SIGNAL ;
    ANTENNADIFFAREA 2.724000 ;
    PORT
      LAYER Metal3 ;
        RECT 0.000 380.740 0.400 381.140 ;
    END
  END Tile_X0Y0_W6BEG[0]
  PIN Tile_X0Y0_W6BEG[10]
    DIRECTION OUTPUT ;
    USE SIGNAL ;
    ANTENNADIFFAREA 2.724000 ;
    PORT
      LAYER Metal3 ;
        RECT 0.000 397.540 0.400 397.940 ;
    END
  END Tile_X0Y0_W6BEG[10]
  PIN Tile_X0Y0_W6BEG[11]
    DIRECTION OUTPUT ;
    USE SIGNAL ;
    ANTENNADIFFAREA 2.724000 ;
    PORT
      LAYER Metal3 ;
        RECT 0.000 399.220 0.400 399.620 ;
    END
  END Tile_X0Y0_W6BEG[11]
  PIN Tile_X0Y0_W6BEG[1]
    DIRECTION OUTPUT ;
    USE SIGNAL ;
    ANTENNADIFFAREA 2.724000 ;
    PORT
      LAYER Metal3 ;
        RECT 0.000 382.420 0.400 382.820 ;
    END
  END Tile_X0Y0_W6BEG[1]
  PIN Tile_X0Y0_W6BEG[2]
    DIRECTION OUTPUT ;
    USE SIGNAL ;
    ANTENNADIFFAREA 2.724000 ;
    PORT
      LAYER Metal3 ;
        RECT 0.000 384.100 0.400 384.500 ;
    END
  END Tile_X0Y0_W6BEG[2]
  PIN Tile_X0Y0_W6BEG[3]
    DIRECTION OUTPUT ;
    USE SIGNAL ;
    ANTENNADIFFAREA 2.724000 ;
    PORT
      LAYER Metal3 ;
        RECT 0.000 385.780 0.400 386.180 ;
    END
  END Tile_X0Y0_W6BEG[3]
  PIN Tile_X0Y0_W6BEG[4]
    DIRECTION OUTPUT ;
    USE SIGNAL ;
    ANTENNADIFFAREA 2.724000 ;
    PORT
      LAYER Metal3 ;
        RECT 0.000 387.460 0.400 387.860 ;
    END
  END Tile_X0Y0_W6BEG[4]
  PIN Tile_X0Y0_W6BEG[5]
    DIRECTION OUTPUT ;
    USE SIGNAL ;
    ANTENNADIFFAREA 2.724000 ;
    PORT
      LAYER Metal3 ;
        RECT 0.000 389.140 0.400 389.540 ;
    END
  END Tile_X0Y0_W6BEG[5]
  PIN Tile_X0Y0_W6BEG[6]
    DIRECTION OUTPUT ;
    USE SIGNAL ;
    ANTENNADIFFAREA 2.724000 ;
    PORT
      LAYER Metal3 ;
        RECT 0.000 390.820 0.400 391.220 ;
    END
  END Tile_X0Y0_W6BEG[6]
  PIN Tile_X0Y0_W6BEG[7]
    DIRECTION OUTPUT ;
    USE SIGNAL ;
    ANTENNADIFFAREA 2.724000 ;
    PORT
      LAYER Metal3 ;
        RECT 0.000 392.500 0.400 392.900 ;
    END
  END Tile_X0Y0_W6BEG[7]
  PIN Tile_X0Y0_W6BEG[8]
    DIRECTION OUTPUT ;
    USE SIGNAL ;
    ANTENNADIFFAREA 2.724000 ;
    PORT
      LAYER Metal3 ;
        RECT 0.000 394.180 0.400 394.580 ;
    END
  END Tile_X0Y0_W6BEG[8]
  PIN Tile_X0Y0_W6BEG[9]
    DIRECTION OUTPUT ;
    USE SIGNAL ;
    ANTENNADIFFAREA 2.724000 ;
    PORT
      LAYER Metal3 ;
        RECT 0.000 395.860 0.400 396.260 ;
    END
  END Tile_X0Y0_W6BEG[9]
  PIN Tile_X0Y0_WW4BEG[0]
    DIRECTION OUTPUT ;
    USE SIGNAL ;
    ANTENNADIFFAREA 2.724000 ;
    PORT
      LAYER Metal3 ;
        RECT 0.000 352.180 0.400 352.580 ;
    END
  END Tile_X0Y0_WW4BEG[0]
  PIN Tile_X0Y0_WW4BEG[10]
    DIRECTION OUTPUT ;
    USE SIGNAL ;
    ANTENNADIFFAREA 2.724000 ;
    PORT
      LAYER Metal3 ;
        RECT 0.000 368.980 0.400 369.380 ;
    END
  END Tile_X0Y0_WW4BEG[10]
  PIN Tile_X0Y0_WW4BEG[11]
    DIRECTION OUTPUT ;
    USE SIGNAL ;
    ANTENNADIFFAREA 2.724000 ;
    PORT
      LAYER Metal3 ;
        RECT 0.000 370.660 0.400 371.060 ;
    END
  END Tile_X0Y0_WW4BEG[11]
  PIN Tile_X0Y0_WW4BEG[12]
    DIRECTION OUTPUT ;
    USE SIGNAL ;
    ANTENNADIFFAREA 2.724000 ;
    PORT
      LAYER Metal3 ;
        RECT 0.000 372.340 0.400 372.740 ;
    END
  END Tile_X0Y0_WW4BEG[12]
  PIN Tile_X0Y0_WW4BEG[13]
    DIRECTION OUTPUT ;
    USE SIGNAL ;
    ANTENNADIFFAREA 2.724000 ;
    PORT
      LAYER Metal3 ;
        RECT 0.000 374.020 0.400 374.420 ;
    END
  END Tile_X0Y0_WW4BEG[13]
  PIN Tile_X0Y0_WW4BEG[14]
    DIRECTION OUTPUT ;
    USE SIGNAL ;
    ANTENNADIFFAREA 2.724000 ;
    PORT
      LAYER Metal3 ;
        RECT 0.000 375.700 0.400 376.100 ;
    END
  END Tile_X0Y0_WW4BEG[14]
  PIN Tile_X0Y0_WW4BEG[15]
    DIRECTION OUTPUT ;
    USE SIGNAL ;
    ANTENNADIFFAREA 2.724000 ;
    PORT
      LAYER Metal3 ;
        RECT 0.000 377.380 0.400 377.780 ;
    END
  END Tile_X0Y0_WW4BEG[15]
  PIN Tile_X0Y0_WW4BEG[1]
    DIRECTION OUTPUT ;
    USE SIGNAL ;
    ANTENNADIFFAREA 2.724000 ;
    PORT
      LAYER Metal3 ;
        RECT 0.000 353.860 0.400 354.260 ;
    END
  END Tile_X0Y0_WW4BEG[1]
  PIN Tile_X0Y0_WW4BEG[2]
    DIRECTION OUTPUT ;
    USE SIGNAL ;
    ANTENNADIFFAREA 2.724000 ;
    PORT
      LAYER Metal3 ;
        RECT 0.000 355.540 0.400 355.940 ;
    END
  END Tile_X0Y0_WW4BEG[2]
  PIN Tile_X0Y0_WW4BEG[3]
    DIRECTION OUTPUT ;
    USE SIGNAL ;
    ANTENNADIFFAREA 2.724000 ;
    PORT
      LAYER Metal3 ;
        RECT 0.000 357.220 0.400 357.620 ;
    END
  END Tile_X0Y0_WW4BEG[3]
  PIN Tile_X0Y0_WW4BEG[4]
    DIRECTION OUTPUT ;
    USE SIGNAL ;
    ANTENNADIFFAREA 2.724000 ;
    PORT
      LAYER Metal3 ;
        RECT 0.000 358.900 0.400 359.300 ;
    END
  END Tile_X0Y0_WW4BEG[4]
  PIN Tile_X0Y0_WW4BEG[5]
    DIRECTION OUTPUT ;
    USE SIGNAL ;
    ANTENNADIFFAREA 2.724000 ;
    PORT
      LAYER Metal3 ;
        RECT 0.000 360.580 0.400 360.980 ;
    END
  END Tile_X0Y0_WW4BEG[5]
  PIN Tile_X0Y0_WW4BEG[6]
    DIRECTION OUTPUT ;
    USE SIGNAL ;
    ANTENNADIFFAREA 2.724000 ;
    PORT
      LAYER Metal3 ;
        RECT 0.000 362.260 0.400 362.660 ;
    END
  END Tile_X0Y0_WW4BEG[6]
  PIN Tile_X0Y0_WW4BEG[7]
    DIRECTION OUTPUT ;
    USE SIGNAL ;
    ANTENNADIFFAREA 2.724000 ;
    PORT
      LAYER Metal3 ;
        RECT 0.000 363.940 0.400 364.340 ;
    END
  END Tile_X0Y0_WW4BEG[7]
  PIN Tile_X0Y0_WW4BEG[8]
    DIRECTION OUTPUT ;
    USE SIGNAL ;
    ANTENNADIFFAREA 2.724000 ;
    PORT
      LAYER Metal3 ;
        RECT 0.000 365.620 0.400 366.020 ;
    END
  END Tile_X0Y0_WW4BEG[8]
  PIN Tile_X0Y0_WW4BEG[9]
    DIRECTION OUTPUT ;
    USE SIGNAL ;
    ANTENNADIFFAREA 2.724000 ;
    PORT
      LAYER Metal3 ;
        RECT 0.000 367.300 0.400 367.700 ;
    END
  END Tile_X0Y0_WW4BEG[9]
  PIN Tile_X0Y1_E1END[0]
    DIRECTION INPUT ;
    USE SIGNAL ;
    ANTENNAGATEAREA 1.279200 ;
    ANTENNADIFFAREA 12.092400 ;
    PORT
      LAYER Metal3 ;
        RECT 0.000 1.060 0.400 1.460 ;
    END
  END Tile_X0Y1_E1END[0]
  PIN Tile_X0Y1_E1END[1]
    DIRECTION INPUT ;
    USE SIGNAL ;
    ANTENNAGATEAREA 1.279200 ;
    ANTENNADIFFAREA 12.092400 ;
    PORT
      LAYER Metal3 ;
        RECT 0.000 2.740 0.400 3.140 ;
    END
  END Tile_X0Y1_E1END[1]
  PIN Tile_X0Y1_E1END[2]
    DIRECTION INPUT ;
    USE SIGNAL ;
    ANTENNAGATEAREA 1.279200 ;
    ANTENNADIFFAREA 12.092400 ;
    PORT
      LAYER Metal3 ;
        RECT 0.000 4.420 0.400 4.820 ;
    END
  END Tile_X0Y1_E1END[2]
  PIN Tile_X0Y1_E1END[3]
    DIRECTION INPUT ;
    USE SIGNAL ;
    ANTENNAGATEAREA 1.279200 ;
    ANTENNADIFFAREA 12.092400 ;
    PORT
      LAYER Metal3 ;
        RECT 0.000 6.100 0.400 6.500 ;
    END
  END Tile_X0Y1_E1END[3]
  PIN Tile_X0Y1_E2END[0]
    DIRECTION INPUT ;
    USE SIGNAL ;
    ANTENNAGATEAREA 0.426400 ;
    ANTENNADIFFAREA 4.030800 ;
    PORT
      LAYER Metal3 ;
        RECT 0.000 22.060 0.400 22.460 ;
    END
  END Tile_X0Y1_E2END[0]
  PIN Tile_X0Y1_E2END[1]
    DIRECTION INPUT ;
    USE SIGNAL ;
    ANTENNAGATEAREA 0.426400 ;
    ANTENNADIFFAREA 4.030800 ;
    PORT
      LAYER Metal3 ;
        RECT 0.000 23.740 0.400 24.140 ;
    END
  END Tile_X0Y1_E2END[1]
  PIN Tile_X0Y1_E2END[2]
    DIRECTION INPUT ;
    USE SIGNAL ;
    ANTENNAGATEAREA 0.639600 ;
    ANTENNADIFFAREA 6.046200 ;
    PORT
      LAYER Metal3 ;
        RECT 0.000 25.420 0.400 25.820 ;
    END
  END Tile_X0Y1_E2END[2]
  PIN Tile_X0Y1_E2END[3]
    DIRECTION INPUT ;
    USE SIGNAL ;
    ANTENNAGATEAREA 0.639600 ;
    ANTENNADIFFAREA 6.046200 ;
    PORT
      LAYER Metal3 ;
        RECT 0.000 27.100 0.400 27.500 ;
    END
  END Tile_X0Y1_E2END[3]
  PIN Tile_X0Y1_E2END[4]
    DIRECTION INPUT ;
    USE SIGNAL ;
    ANTENNAGATEAREA 0.426400 ;
    ANTENNADIFFAREA 4.030800 ;
    PORT
      LAYER Metal3 ;
        RECT 0.000 28.780 0.400 29.180 ;
    END
  END Tile_X0Y1_E2END[4]
  PIN Tile_X0Y1_E2END[5]
    DIRECTION INPUT ;
    USE SIGNAL ;
    ANTENNAGATEAREA 0.426400 ;
    ANTENNADIFFAREA 4.030800 ;
    PORT
      LAYER Metal3 ;
        RECT 0.000 30.460 0.400 30.860 ;
    END
  END Tile_X0Y1_E2END[5]
  PIN Tile_X0Y1_E2END[6]
    DIRECTION INPUT ;
    USE SIGNAL ;
    ANTENNAGATEAREA 0.426400 ;
    ANTENNADIFFAREA 4.030800 ;
    PORT
      LAYER Metal3 ;
        RECT 0.000 32.140 0.400 32.540 ;
    END
  END Tile_X0Y1_E2END[6]
  PIN Tile_X0Y1_E2END[7]
    DIRECTION INPUT ;
    USE SIGNAL ;
    ANTENNAGATEAREA 0.426400 ;
    ANTENNADIFFAREA 4.030800 ;
    PORT
      LAYER Metal3 ;
        RECT 0.000 33.820 0.400 34.220 ;
    END
  END Tile_X0Y1_E2END[7]
  PIN Tile_X0Y1_E2MID[0]
    DIRECTION INPUT ;
    USE SIGNAL ;
    ANTENNAGATEAREA 0.639600 ;
    ANTENNADIFFAREA 6.046200 ;
    PORT
      LAYER Metal3 ;
        RECT 0.000 8.620 0.400 9.020 ;
    END
  END Tile_X0Y1_E2MID[0]
  PIN Tile_X0Y1_E2MID[1]
    DIRECTION INPUT ;
    USE SIGNAL ;
    ANTENNAGATEAREA 0.639600 ;
    ANTENNADIFFAREA 6.046200 ;
    PORT
      LAYER Metal3 ;
        RECT 0.000 10.300 0.400 10.700 ;
    END
  END Tile_X0Y1_E2MID[1]
  PIN Tile_X0Y1_E2MID[2]
    DIRECTION INPUT ;
    USE SIGNAL ;
    ANTENNAGATEAREA 0.639600 ;
    ANTENNADIFFAREA 6.046200 ;
    PORT
      LAYER Metal3 ;
        RECT 0.000 11.980 0.400 12.380 ;
    END
  END Tile_X0Y1_E2MID[2]
  PIN Tile_X0Y1_E2MID[3]
    DIRECTION INPUT ;
    USE SIGNAL ;
    ANTENNAGATEAREA 0.639600 ;
    ANTENNADIFFAREA 6.046200 ;
    PORT
      LAYER Metal3 ;
        RECT 0.000 13.660 0.400 14.060 ;
    END
  END Tile_X0Y1_E2MID[3]
  PIN Tile_X0Y1_E2MID[4]
    DIRECTION INPUT ;
    USE SIGNAL ;
    ANTENNAGATEAREA 0.639600 ;
    ANTENNADIFFAREA 6.046200 ;
    PORT
      LAYER Metal3 ;
        RECT 0.000 15.340 0.400 15.740 ;
    END
  END Tile_X0Y1_E2MID[4]
  PIN Tile_X0Y1_E2MID[5]
    DIRECTION INPUT ;
    USE SIGNAL ;
    ANTENNAGATEAREA 0.639600 ;
    ANTENNADIFFAREA 6.046200 ;
    PORT
      LAYER Metal3 ;
        RECT 0.000 17.020 0.400 17.420 ;
    END
  END Tile_X0Y1_E2MID[5]
  PIN Tile_X0Y1_E2MID[6]
    DIRECTION INPUT ;
    USE SIGNAL ;
    ANTENNAGATEAREA 0.426400 ;
    ANTENNADIFFAREA 4.030800 ;
    PORT
      LAYER Metal3 ;
        RECT 0.000 18.700 0.400 19.100 ;
    END
  END Tile_X0Y1_E2MID[6]
  PIN Tile_X0Y1_E2MID[7]
    DIRECTION INPUT ;
    USE SIGNAL ;
    ANTENNAGATEAREA 0.426400 ;
    ANTENNADIFFAREA 4.030800 ;
    PORT
      LAYER Metal3 ;
        RECT 0.000 20.380 0.400 20.780 ;
    END
  END Tile_X0Y1_E2MID[7]
  PIN Tile_X0Y1_E6END[0]
    DIRECTION INPUT ;
    USE SIGNAL ;
    ANTENNAGATEAREA 0.639600 ;
    ANTENNADIFFAREA 6.046200 ;
    PORT
      LAYER Metal3 ;
        RECT 0.000 64.900 0.400 65.300 ;
    END
  END Tile_X0Y1_E6END[0]
  PIN Tile_X0Y1_E6END[10]
    DIRECTION INPUT ;
    USE SIGNAL ;
    ANTENNAGATEAREA 0.852800 ;
    ANTENNADIFFAREA 8.061600 ;
    PORT
      LAYER Metal3 ;
        RECT 0.000 81.700 0.400 82.100 ;
    END
  END Tile_X0Y1_E6END[10]
  PIN Tile_X0Y1_E6END[11]
    DIRECTION INPUT ;
    USE SIGNAL ;
    ANTENNAGATEAREA 0.852800 ;
    ANTENNADIFFAREA 8.061600 ;
    PORT
      LAYER Metal3 ;
        RECT 0.000 83.380 0.400 83.780 ;
    END
  END Tile_X0Y1_E6END[11]
  PIN Tile_X0Y1_E6END[1]
    DIRECTION INPUT ;
    USE SIGNAL ;
    ANTENNAGATEAREA 0.639600 ;
    ANTENNADIFFAREA 6.046200 ;
    PORT
      LAYER Metal3 ;
        RECT 0.000 66.580 0.400 66.980 ;
    END
  END Tile_X0Y1_E6END[1]
  PIN Tile_X0Y1_E6END[2]
    DIRECTION INPUT ;
    USE SIGNAL ;
    ANTENNAGATEAREA 0.639600 ;
    ANTENNADIFFAREA 6.046200 ;
    PORT
      LAYER Metal3 ;
        RECT 0.000 68.260 0.400 68.660 ;
    END
  END Tile_X0Y1_E6END[2]
  PIN Tile_X0Y1_E6END[3]
    DIRECTION INPUT ;
    USE SIGNAL ;
    ANTENNAGATEAREA 0.639600 ;
    ANTENNADIFFAREA 6.046200 ;
    PORT
      LAYER Metal3 ;
        RECT 0.000 69.940 0.400 70.340 ;
    END
  END Tile_X0Y1_E6END[3]
  PIN Tile_X0Y1_E6END[4]
    DIRECTION INPUT ;
    USE SIGNAL ;
    ANTENNAGATEAREA 0.852800 ;
    ANTENNADIFFAREA 8.061600 ;
    PORT
      LAYER Metal3 ;
        RECT 0.000 71.620 0.400 72.020 ;
    END
  END Tile_X0Y1_E6END[4]
  PIN Tile_X0Y1_E6END[5]
    DIRECTION INPUT ;
    USE SIGNAL ;
    ANTENNAGATEAREA 0.852800 ;
    ANTENNADIFFAREA 8.061600 ;
    PORT
      LAYER Metal3 ;
        RECT 0.000 73.300 0.400 73.700 ;
    END
  END Tile_X0Y1_E6END[5]
  PIN Tile_X0Y1_E6END[6]
    DIRECTION INPUT ;
    USE SIGNAL ;
    ANTENNAGATEAREA 0.852800 ;
    ANTENNADIFFAREA 8.061600 ;
    PORT
      LAYER Metal3 ;
        RECT 0.000 74.980 0.400 75.380 ;
    END
  END Tile_X0Y1_E6END[6]
  PIN Tile_X0Y1_E6END[7]
    DIRECTION INPUT ;
    USE SIGNAL ;
    ANTENNAGATEAREA 0.852800 ;
    ANTENNADIFFAREA 8.061600 ;
    PORT
      LAYER Metal3 ;
        RECT 0.000 76.660 0.400 77.060 ;
    END
  END Tile_X0Y1_E6END[7]
  PIN Tile_X0Y1_E6END[8]
    DIRECTION INPUT ;
    USE SIGNAL ;
    ANTENNAGATEAREA 0.852800 ;
    ANTENNADIFFAREA 8.061600 ;
    PORT
      LAYER Metal3 ;
        RECT 0.000 78.340 0.400 78.740 ;
    END
  END Tile_X0Y1_E6END[8]
  PIN Tile_X0Y1_E6END[9]
    DIRECTION INPUT ;
    USE SIGNAL ;
    ANTENNAGATEAREA 0.852800 ;
    ANTENNADIFFAREA 8.061600 ;
    PORT
      LAYER Metal3 ;
        RECT 0.000 80.020 0.400 80.420 ;
    END
  END Tile_X0Y1_E6END[9]
  PIN Tile_X0Y1_EE4END[0]
    DIRECTION INPUT ;
    USE SIGNAL ;
    ANTENNAGATEAREA 0.639600 ;
    ANTENNADIFFAREA 6.046200 ;
    PORT
      LAYER Metal3 ;
        RECT 0.000 36.340 0.400 36.740 ;
    END
  END Tile_X0Y1_EE4END[0]
  PIN Tile_X0Y1_EE4END[10]
    DIRECTION INPUT ;
    USE SIGNAL ;
    ANTENNAGATEAREA 0.426400 ;
    ANTENNADIFFAREA 4.030800 ;
    PORT
      LAYER Metal3 ;
        RECT 0.000 53.140 0.400 53.540 ;
    END
  END Tile_X0Y1_EE4END[10]
  PIN Tile_X0Y1_EE4END[11]
    DIRECTION INPUT ;
    USE SIGNAL ;
    ANTENNAGATEAREA 0.426400 ;
    ANTENNADIFFAREA 4.030800 ;
    PORT
      LAYER Metal3 ;
        RECT 0.000 54.820 0.400 55.220 ;
    END
  END Tile_X0Y1_EE4END[11]
  PIN Tile_X0Y1_EE4END[12]
    DIRECTION INPUT ;
    USE SIGNAL ;
    ANTENNAGATEAREA 0.639600 ;
    ANTENNADIFFAREA 6.046200 ;
    PORT
      LAYER Metal3 ;
        RECT 0.000 56.500 0.400 56.900 ;
    END
  END Tile_X0Y1_EE4END[12]
  PIN Tile_X0Y1_EE4END[13]
    DIRECTION INPUT ;
    USE SIGNAL ;
    ANTENNAGATEAREA 0.639600 ;
    ANTENNADIFFAREA 6.046200 ;
    PORT
      LAYER Metal3 ;
        RECT 0.000 58.180 0.400 58.580 ;
    END
  END Tile_X0Y1_EE4END[13]
  PIN Tile_X0Y1_EE4END[14]
    DIRECTION INPUT ;
    USE SIGNAL ;
    ANTENNAGATEAREA 0.639600 ;
    ANTENNADIFFAREA 6.046200 ;
    PORT
      LAYER Metal3 ;
        RECT 0.000 59.860 0.400 60.260 ;
    END
  END Tile_X0Y1_EE4END[14]
  PIN Tile_X0Y1_EE4END[15]
    DIRECTION INPUT ;
    USE SIGNAL ;
    ANTENNAGATEAREA 0.639600 ;
    ANTENNADIFFAREA 6.046200 ;
    PORT
      LAYER Metal3 ;
        RECT 0.000 61.540 0.400 61.940 ;
    END
  END Tile_X0Y1_EE4END[15]
  PIN Tile_X0Y1_EE4END[1]
    DIRECTION INPUT ;
    USE SIGNAL ;
    ANTENNAGATEAREA 0.639600 ;
    ANTENNADIFFAREA 6.046200 ;
    PORT
      LAYER Metal3 ;
        RECT 0.000 38.020 0.400 38.420 ;
    END
  END Tile_X0Y1_EE4END[1]
  PIN Tile_X0Y1_EE4END[2]
    DIRECTION INPUT ;
    USE SIGNAL ;
    ANTENNAGATEAREA 0.639600 ;
    ANTENNADIFFAREA 6.046200 ;
    PORT
      LAYER Metal3 ;
        RECT 0.000 39.700 0.400 40.100 ;
    END
  END Tile_X0Y1_EE4END[2]
  PIN Tile_X0Y1_EE4END[3]
    DIRECTION INPUT ;
    USE SIGNAL ;
    ANTENNAGATEAREA 0.639600 ;
    ANTENNADIFFAREA 6.046200 ;
    PORT
      LAYER Metal3 ;
        RECT 0.000 41.380 0.400 41.780 ;
    END
  END Tile_X0Y1_EE4END[3]
  PIN Tile_X0Y1_EE4END[4]
    DIRECTION INPUT ;
    USE SIGNAL ;
    ANTENNAGATEAREA 0.639600 ;
    ANTENNADIFFAREA 6.046200 ;
    PORT
      LAYER Metal3 ;
        RECT 0.000 43.060 0.400 43.460 ;
    END
  END Tile_X0Y1_EE4END[4]
  PIN Tile_X0Y1_EE4END[5]
    DIRECTION INPUT ;
    USE SIGNAL ;
    ANTENNAGATEAREA 0.639600 ;
    ANTENNADIFFAREA 6.046200 ;
    PORT
      LAYER Metal3 ;
        RECT 0.000 44.740 0.400 45.140 ;
    END
  END Tile_X0Y1_EE4END[5]
  PIN Tile_X0Y1_EE4END[6]
    DIRECTION INPUT ;
    USE SIGNAL ;
    ANTENNAGATEAREA 0.426400 ;
    ANTENNADIFFAREA 4.030800 ;
    PORT
      LAYER Metal3 ;
        RECT 0.000 46.420 0.400 46.820 ;
    END
  END Tile_X0Y1_EE4END[6]
  PIN Tile_X0Y1_EE4END[7]
    DIRECTION INPUT ;
    USE SIGNAL ;
    ANTENNAGATEAREA 0.426400 ;
    ANTENNADIFFAREA 4.030800 ;
    PORT
      LAYER Metal3 ;
        RECT 0.000 48.100 0.400 48.500 ;
    END
  END Tile_X0Y1_EE4END[7]
  PIN Tile_X0Y1_EE4END[8]
    DIRECTION INPUT ;
    USE SIGNAL ;
    ANTENNAGATEAREA 0.639600 ;
    ANTENNADIFFAREA 6.046200 ;
    PORT
      LAYER Metal3 ;
        RECT 0.000 49.780 0.400 50.180 ;
    END
  END Tile_X0Y1_EE4END[8]
  PIN Tile_X0Y1_EE4END[9]
    DIRECTION INPUT ;
    USE SIGNAL ;
    ANTENNAGATEAREA 0.639600 ;
    ANTENNADIFFAREA 6.046200 ;
    PORT
      LAYER Metal3 ;
        RECT 0.000 51.460 0.400 51.860 ;
    END
  END Tile_X0Y1_EE4END[9]
  PIN Tile_X0Y1_FrameData[0]
    DIRECTION INPUT ;
    USE SIGNAL ;
    ANTENNAGATEAREA 1.626300 ;
    ANTENNADIFFAREA 18.138599 ;
    PORT
      LAYER Metal3 ;
        RECT 0.000 174.940 0.400 175.340 ;
    END
  END Tile_X0Y1_FrameData[0]
  PIN Tile_X0Y1_FrameData[10]
    DIRECTION INPUT ;
    USE SIGNAL ;
    ANTENNAGATEAREA 1.626300 ;
    ANTENNADIFFAREA 18.138599 ;
    PORT
      LAYER Metal3 ;
        RECT 0.000 191.740 0.400 192.140 ;
    END
  END Tile_X0Y1_FrameData[10]
  PIN Tile_X0Y1_FrameData[11]
    DIRECTION INPUT ;
    USE SIGNAL ;
    ANTENNAGATEAREA 1.626300 ;
    ANTENNADIFFAREA 18.138599 ;
    PORT
      LAYER Metal3 ;
        RECT 0.000 193.420 0.400 193.820 ;
    END
  END Tile_X0Y1_FrameData[11]
  PIN Tile_X0Y1_FrameData[12]
    DIRECTION INPUT ;
    USE SIGNAL ;
    ANTENNAGATEAREA 1.626300 ;
    ANTENNADIFFAREA 18.138599 ;
    PORT
      LAYER Metal3 ;
        RECT 0.000 195.100 0.400 195.500 ;
    END
  END Tile_X0Y1_FrameData[12]
  PIN Tile_X0Y1_FrameData[13]
    DIRECTION INPUT ;
    USE SIGNAL ;
    ANTENNAGATEAREA 1.626300 ;
    ANTENNADIFFAREA 18.138599 ;
    PORT
      LAYER Metal3 ;
        RECT 0.000 196.780 0.400 197.180 ;
    END
  END Tile_X0Y1_FrameData[13]
  PIN Tile_X0Y1_FrameData[14]
    DIRECTION INPUT ;
    USE SIGNAL ;
    ANTENNAGATEAREA 1.626300 ;
    ANTENNADIFFAREA 18.138599 ;
    PORT
      LAYER Metal3 ;
        RECT 0.000 198.460 0.400 198.860 ;
    END
  END Tile_X0Y1_FrameData[14]
  PIN Tile_X0Y1_FrameData[15]
    DIRECTION INPUT ;
    USE SIGNAL ;
    ANTENNAGATEAREA 1.626300 ;
    ANTENNADIFFAREA 18.138599 ;
    PORT
      LAYER Metal3 ;
        RECT 0.000 200.140 0.400 200.540 ;
    END
  END Tile_X0Y1_FrameData[15]
  PIN Tile_X0Y1_FrameData[16]
    DIRECTION INPUT ;
    USE SIGNAL ;
    ANTENNAGATEAREA 1.626300 ;
    ANTENNADIFFAREA 18.138599 ;
    PORT
      LAYER Metal3 ;
        RECT 0.000 201.820 0.400 202.220 ;
    END
  END Tile_X0Y1_FrameData[16]
  PIN Tile_X0Y1_FrameData[17]
    DIRECTION INPUT ;
    USE SIGNAL ;
    ANTENNAGATEAREA 1.626300 ;
    ANTENNADIFFAREA 18.138599 ;
    PORT
      LAYER Metal3 ;
        RECT 0.000 203.500 0.400 203.900 ;
    END
  END Tile_X0Y1_FrameData[17]
  PIN Tile_X0Y1_FrameData[18]
    DIRECTION INPUT ;
    USE SIGNAL ;
    ANTENNAGATEAREA 1.626300 ;
    ANTENNADIFFAREA 18.138599 ;
    PORT
      LAYER Metal3 ;
        RECT 0.000 205.180 0.400 205.580 ;
    END
  END Tile_X0Y1_FrameData[18]
  PIN Tile_X0Y1_FrameData[19]
    DIRECTION INPUT ;
    USE SIGNAL ;
    ANTENNAGATEAREA 1.626300 ;
    ANTENNADIFFAREA 18.138599 ;
    PORT
      LAYER Metal3 ;
        RECT 0.000 206.860 0.400 207.260 ;
    END
  END Tile_X0Y1_FrameData[19]
  PIN Tile_X0Y1_FrameData[1]
    DIRECTION INPUT ;
    USE SIGNAL ;
    ANTENNAGATEAREA 1.626300 ;
    ANTENNADIFFAREA 18.138599 ;
    PORT
      LAYER Metal3 ;
        RECT 0.000 176.620 0.400 177.020 ;
    END
  END Tile_X0Y1_FrameData[1]
  PIN Tile_X0Y1_FrameData[20]
    DIRECTION INPUT ;
    USE SIGNAL ;
    ANTENNAGATEAREA 1.626300 ;
    ANTENNADIFFAREA 18.138599 ;
    PORT
      LAYER Metal3 ;
        RECT 0.000 208.540 0.400 208.940 ;
    END
  END Tile_X0Y1_FrameData[20]
  PIN Tile_X0Y1_FrameData[21]
    DIRECTION INPUT ;
    USE SIGNAL ;
    ANTENNAGATEAREA 1.626300 ;
    ANTENNADIFFAREA 18.138599 ;
    PORT
      LAYER Metal3 ;
        RECT 0.000 210.220 0.400 210.620 ;
    END
  END Tile_X0Y1_FrameData[21]
  PIN Tile_X0Y1_FrameData[22]
    DIRECTION INPUT ;
    USE SIGNAL ;
    ANTENNAGATEAREA 1.626300 ;
    ANTENNADIFFAREA 18.138599 ;
    PORT
      LAYER Metal3 ;
        RECT 0.000 211.900 0.400 212.300 ;
    END
  END Tile_X0Y1_FrameData[22]
  PIN Tile_X0Y1_FrameData[23]
    DIRECTION INPUT ;
    USE SIGNAL ;
    ANTENNAGATEAREA 1.626300 ;
    ANTENNADIFFAREA 18.138599 ;
    PORT
      LAYER Metal3 ;
        RECT 0.000 213.580 0.400 213.980 ;
    END
  END Tile_X0Y1_FrameData[23]
  PIN Tile_X0Y1_FrameData[24]
    DIRECTION INPUT ;
    USE SIGNAL ;
    ANTENNAGATEAREA 1.626300 ;
    ANTENNADIFFAREA 18.138599 ;
    PORT
      LAYER Metal3 ;
        RECT 0.000 215.260 0.400 215.660 ;
    END
  END Tile_X0Y1_FrameData[24]
  PIN Tile_X0Y1_FrameData[25]
    DIRECTION INPUT ;
    USE SIGNAL ;
    ANTENNAGATEAREA 1.626300 ;
    ANTENNADIFFAREA 18.138599 ;
    PORT
      LAYER Metal3 ;
        RECT 0.000 216.940 0.400 217.340 ;
    END
  END Tile_X0Y1_FrameData[25]
  PIN Tile_X0Y1_FrameData[26]
    DIRECTION INPUT ;
    USE SIGNAL ;
    ANTENNAGATEAREA 1.807000 ;
    ANTENNADIFFAREA 20.153999 ;
    PORT
      LAYER Metal3 ;
        RECT 0.000 218.620 0.400 219.020 ;
    END
  END Tile_X0Y1_FrameData[26]
  PIN Tile_X0Y1_FrameData[27]
    DIRECTION INPUT ;
    USE SIGNAL ;
    ANTENNAGATEAREA 1.807000 ;
    ANTENNADIFFAREA 20.153999 ;
    PORT
      LAYER Metal3 ;
        RECT 0.000 220.300 0.400 220.700 ;
    END
  END Tile_X0Y1_FrameData[27]
  PIN Tile_X0Y1_FrameData[28]
    DIRECTION INPUT ;
    USE SIGNAL ;
    ANTENNAGATEAREA 1.807000 ;
    ANTENNADIFFAREA 20.153999 ;
    PORT
      LAYER Metal3 ;
        RECT 0.000 221.980 0.400 222.380 ;
    END
  END Tile_X0Y1_FrameData[28]
  PIN Tile_X0Y1_FrameData[29]
    DIRECTION INPUT ;
    USE SIGNAL ;
    ANTENNAGATEAREA 1.807000 ;
    ANTENNADIFFAREA 20.153999 ;
    PORT
      LAYER Metal3 ;
        RECT 0.000 223.660 0.400 224.060 ;
    END
  END Tile_X0Y1_FrameData[29]
  PIN Tile_X0Y1_FrameData[2]
    DIRECTION INPUT ;
    USE SIGNAL ;
    ANTENNAGATEAREA 1.626300 ;
    ANTENNADIFFAREA 18.138599 ;
    PORT
      LAYER Metal3 ;
        RECT 0.000 178.300 0.400 178.700 ;
    END
  END Tile_X0Y1_FrameData[2]
  PIN Tile_X0Y1_FrameData[30]
    DIRECTION INPUT ;
    USE SIGNAL ;
    ANTENNAGATEAREA 1.807000 ;
    ANTENNADIFFAREA 20.153999 ;
    PORT
      LAYER Metal3 ;
        RECT 0.000 225.340 0.400 225.740 ;
    END
  END Tile_X0Y1_FrameData[30]
  PIN Tile_X0Y1_FrameData[31]
    DIRECTION INPUT ;
    USE SIGNAL ;
    ANTENNAGATEAREA 1.807000 ;
    ANTENNADIFFAREA 20.153999 ;
    PORT
      LAYER Metal3 ;
        RECT 0.000 227.020 0.400 227.420 ;
    END
  END Tile_X0Y1_FrameData[31]
  PIN Tile_X0Y1_FrameData[3]
    DIRECTION INPUT ;
    USE SIGNAL ;
    ANTENNAGATEAREA 1.626300 ;
    ANTENNADIFFAREA 18.138599 ;
    PORT
      LAYER Metal3 ;
        RECT 0.000 179.980 0.400 180.380 ;
    END
  END Tile_X0Y1_FrameData[3]
  PIN Tile_X0Y1_FrameData[4]
    DIRECTION INPUT ;
    USE SIGNAL ;
    ANTENNAGATEAREA 1.626300 ;
    ANTENNADIFFAREA 18.138599 ;
    PORT
      LAYER Metal3 ;
        RECT 0.000 181.660 0.400 182.060 ;
    END
  END Tile_X0Y1_FrameData[4]
  PIN Tile_X0Y1_FrameData[5]
    DIRECTION INPUT ;
    USE SIGNAL ;
    ANTENNAGATEAREA 1.626300 ;
    ANTENNADIFFAREA 18.138599 ;
    PORT
      LAYER Metal3 ;
        RECT 0.000 183.340 0.400 183.740 ;
    END
  END Tile_X0Y1_FrameData[5]
  PIN Tile_X0Y1_FrameData[6]
    DIRECTION INPUT ;
    USE SIGNAL ;
    ANTENNAGATEAREA 1.626300 ;
    ANTENNADIFFAREA 18.138599 ;
    PORT
      LAYER Metal3 ;
        RECT 0.000 185.020 0.400 185.420 ;
    END
  END Tile_X0Y1_FrameData[6]
  PIN Tile_X0Y1_FrameData[7]
    DIRECTION INPUT ;
    USE SIGNAL ;
    ANTENNAGATEAREA 1.626300 ;
    ANTENNADIFFAREA 18.138599 ;
    PORT
      LAYER Metal3 ;
        RECT 0.000 186.700 0.400 187.100 ;
    END
  END Tile_X0Y1_FrameData[7]
  PIN Tile_X0Y1_FrameData[8]
    DIRECTION INPUT ;
    USE SIGNAL ;
    ANTENNAGATEAREA 1.626300 ;
    ANTENNADIFFAREA 18.138599 ;
    PORT
      LAYER Metal3 ;
        RECT 0.000 188.380 0.400 188.780 ;
    END
  END Tile_X0Y1_FrameData[8]
  PIN Tile_X0Y1_FrameData[9]
    DIRECTION INPUT ;
    USE SIGNAL ;
    ANTENNAGATEAREA 1.626300 ;
    ANTENNADIFFAREA 18.138599 ;
    PORT
      LAYER Metal3 ;
        RECT 0.000 190.060 0.400 190.460 ;
    END
  END Tile_X0Y1_FrameData[9]
  PIN Tile_X0Y1_FrameData_O[0]
    DIRECTION OUTPUT ;
    USE SIGNAL ;
    ANTENNADIFFAREA 2.724000 ;
    PORT
      LAYER Metal3 ;
        RECT 88.880 9.460 89.280 9.860 ;
    END
  END Tile_X0Y1_FrameData_O[0]
  PIN Tile_X0Y1_FrameData_O[10]
    DIRECTION OUTPUT ;
    USE SIGNAL ;
    ANTENNADIFFAREA 2.724000 ;
    PORT
      LAYER Metal3 ;
        RECT 88.880 34.660 89.280 35.060 ;
    END
  END Tile_X0Y1_FrameData_O[10]
  PIN Tile_X0Y1_FrameData_O[11]
    DIRECTION OUTPUT ;
    USE SIGNAL ;
    ANTENNADIFFAREA 2.724000 ;
    PORT
      LAYER Metal3 ;
        RECT 88.880 37.180 89.280 37.580 ;
    END
  END Tile_X0Y1_FrameData_O[11]
  PIN Tile_X0Y1_FrameData_O[12]
    DIRECTION OUTPUT ;
    USE SIGNAL ;
    ANTENNADIFFAREA 2.724000 ;
    PORT
      LAYER Metal3 ;
        RECT 88.880 39.700 89.280 40.100 ;
    END
  END Tile_X0Y1_FrameData_O[12]
  PIN Tile_X0Y1_FrameData_O[13]
    DIRECTION OUTPUT ;
    USE SIGNAL ;
    ANTENNADIFFAREA 2.724000 ;
    PORT
      LAYER Metal3 ;
        RECT 88.880 42.220 89.280 42.620 ;
    END
  END Tile_X0Y1_FrameData_O[13]
  PIN Tile_X0Y1_FrameData_O[14]
    DIRECTION OUTPUT ;
    USE SIGNAL ;
    ANTENNADIFFAREA 2.724000 ;
    PORT
      LAYER Metal3 ;
        RECT 88.880 44.740 89.280 45.140 ;
    END
  END Tile_X0Y1_FrameData_O[14]
  PIN Tile_X0Y1_FrameData_O[15]
    DIRECTION OUTPUT ;
    USE SIGNAL ;
    ANTENNADIFFAREA 2.724000 ;
    PORT
      LAYER Metal3 ;
        RECT 88.880 47.260 89.280 47.660 ;
    END
  END Tile_X0Y1_FrameData_O[15]
  PIN Tile_X0Y1_FrameData_O[16]
    DIRECTION OUTPUT ;
    USE SIGNAL ;
    ANTENNADIFFAREA 2.724000 ;
    PORT
      LAYER Metal3 ;
        RECT 88.880 49.780 89.280 50.180 ;
    END
  END Tile_X0Y1_FrameData_O[16]
  PIN Tile_X0Y1_FrameData_O[17]
    DIRECTION OUTPUT ;
    USE SIGNAL ;
    ANTENNADIFFAREA 2.724000 ;
    PORT
      LAYER Metal3 ;
        RECT 88.880 52.300 89.280 52.700 ;
    END
  END Tile_X0Y1_FrameData_O[17]
  PIN Tile_X0Y1_FrameData_O[18]
    DIRECTION OUTPUT ;
    USE SIGNAL ;
    ANTENNADIFFAREA 2.724000 ;
    PORT
      LAYER Metal3 ;
        RECT 88.880 54.820 89.280 55.220 ;
    END
  END Tile_X0Y1_FrameData_O[18]
  PIN Tile_X0Y1_FrameData_O[19]
    DIRECTION OUTPUT ;
    USE SIGNAL ;
    ANTENNADIFFAREA 2.724000 ;
    PORT
      LAYER Metal3 ;
        RECT 88.880 57.340 89.280 57.740 ;
    END
  END Tile_X0Y1_FrameData_O[19]
  PIN Tile_X0Y1_FrameData_O[1]
    DIRECTION OUTPUT ;
    USE SIGNAL ;
    ANTENNADIFFAREA 2.724000 ;
    PORT
      LAYER Metal3 ;
        RECT 88.880 11.980 89.280 12.380 ;
    END
  END Tile_X0Y1_FrameData_O[1]
  PIN Tile_X0Y1_FrameData_O[20]
    DIRECTION OUTPUT ;
    USE SIGNAL ;
    ANTENNADIFFAREA 2.724000 ;
    PORT
      LAYER Metal3 ;
        RECT 88.880 59.860 89.280 60.260 ;
    END
  END Tile_X0Y1_FrameData_O[20]
  PIN Tile_X0Y1_FrameData_O[21]
    DIRECTION OUTPUT ;
    USE SIGNAL ;
    ANTENNADIFFAREA 2.724000 ;
    PORT
      LAYER Metal3 ;
        RECT 88.880 62.380 89.280 62.780 ;
    END
  END Tile_X0Y1_FrameData_O[21]
  PIN Tile_X0Y1_FrameData_O[22]
    DIRECTION OUTPUT ;
    USE SIGNAL ;
    ANTENNADIFFAREA 2.724000 ;
    PORT
      LAYER Metal3 ;
        RECT 88.880 64.900 89.280 65.300 ;
    END
  END Tile_X0Y1_FrameData_O[22]
  PIN Tile_X0Y1_FrameData_O[23]
    DIRECTION OUTPUT ;
    USE SIGNAL ;
    ANTENNADIFFAREA 2.724000 ;
    PORT
      LAYER Metal3 ;
        RECT 88.880 67.420 89.280 67.820 ;
    END
  END Tile_X0Y1_FrameData_O[23]
  PIN Tile_X0Y1_FrameData_O[24]
    DIRECTION OUTPUT ;
    USE SIGNAL ;
    ANTENNADIFFAREA 2.724000 ;
    PORT
      LAYER Metal3 ;
        RECT 88.880 69.940 89.280 70.340 ;
    END
  END Tile_X0Y1_FrameData_O[24]
  PIN Tile_X0Y1_FrameData_O[25]
    DIRECTION OUTPUT ;
    USE SIGNAL ;
    ANTENNADIFFAREA 2.724000 ;
    PORT
      LAYER Metal3 ;
        RECT 88.880 72.460 89.280 72.860 ;
    END
  END Tile_X0Y1_FrameData_O[25]
  PIN Tile_X0Y1_FrameData_O[26]
    DIRECTION OUTPUT ;
    USE SIGNAL ;
    ANTENNADIFFAREA 2.724000 ;
    PORT
      LAYER Metal3 ;
        RECT 88.880 74.980 89.280 75.380 ;
    END
  END Tile_X0Y1_FrameData_O[26]
  PIN Tile_X0Y1_FrameData_O[27]
    DIRECTION OUTPUT ;
    USE SIGNAL ;
    ANTENNADIFFAREA 2.724000 ;
    PORT
      LAYER Metal3 ;
        RECT 88.880 77.500 89.280 77.900 ;
    END
  END Tile_X0Y1_FrameData_O[27]
  PIN Tile_X0Y1_FrameData_O[28]
    DIRECTION OUTPUT ;
    USE SIGNAL ;
    ANTENNADIFFAREA 2.724000 ;
    PORT
      LAYER Metal3 ;
        RECT 88.880 80.020 89.280 80.420 ;
    END
  END Tile_X0Y1_FrameData_O[28]
  PIN Tile_X0Y1_FrameData_O[29]
    DIRECTION OUTPUT ;
    USE SIGNAL ;
    ANTENNADIFFAREA 2.724000 ;
    PORT
      LAYER Metal3 ;
        RECT 88.880 82.540 89.280 82.940 ;
    END
  END Tile_X0Y1_FrameData_O[29]
  PIN Tile_X0Y1_FrameData_O[2]
    DIRECTION OUTPUT ;
    USE SIGNAL ;
    ANTENNADIFFAREA 2.724000 ;
    PORT
      LAYER Metal3 ;
        RECT 88.880 14.500 89.280 14.900 ;
    END
  END Tile_X0Y1_FrameData_O[2]
  PIN Tile_X0Y1_FrameData_O[30]
    DIRECTION OUTPUT ;
    USE SIGNAL ;
    ANTENNADIFFAREA 2.724000 ;
    PORT
      LAYER Metal3 ;
        RECT 88.880 85.060 89.280 85.460 ;
    END
  END Tile_X0Y1_FrameData_O[30]
  PIN Tile_X0Y1_FrameData_O[31]
    DIRECTION OUTPUT ;
    USE SIGNAL ;
    ANTENNADIFFAREA 2.724000 ;
    PORT
      LAYER Metal3 ;
        RECT 88.880 87.580 89.280 87.980 ;
    END
  END Tile_X0Y1_FrameData_O[31]
  PIN Tile_X0Y1_FrameData_O[3]
    DIRECTION OUTPUT ;
    USE SIGNAL ;
    ANTENNADIFFAREA 2.724000 ;
    PORT
      LAYER Metal3 ;
        RECT 88.880 17.020 89.280 17.420 ;
    END
  END Tile_X0Y1_FrameData_O[3]
  PIN Tile_X0Y1_FrameData_O[4]
    DIRECTION OUTPUT ;
    USE SIGNAL ;
    ANTENNADIFFAREA 2.724000 ;
    PORT
      LAYER Metal3 ;
        RECT 88.880 19.540 89.280 19.940 ;
    END
  END Tile_X0Y1_FrameData_O[4]
  PIN Tile_X0Y1_FrameData_O[5]
    DIRECTION OUTPUT ;
    USE SIGNAL ;
    ANTENNADIFFAREA 2.724000 ;
    PORT
      LAYER Metal3 ;
        RECT 88.880 22.060 89.280 22.460 ;
    END
  END Tile_X0Y1_FrameData_O[5]
  PIN Tile_X0Y1_FrameData_O[6]
    DIRECTION OUTPUT ;
    USE SIGNAL ;
    ANTENNADIFFAREA 2.724000 ;
    PORT
      LAYER Metal3 ;
        RECT 88.880 24.580 89.280 24.980 ;
    END
  END Tile_X0Y1_FrameData_O[6]
  PIN Tile_X0Y1_FrameData_O[7]
    DIRECTION OUTPUT ;
    USE SIGNAL ;
    ANTENNADIFFAREA 2.724000 ;
    PORT
      LAYER Metal3 ;
        RECT 88.880 27.100 89.280 27.500 ;
    END
  END Tile_X0Y1_FrameData_O[7]
  PIN Tile_X0Y1_FrameData_O[8]
    DIRECTION OUTPUT ;
    USE SIGNAL ;
    ANTENNADIFFAREA 2.724000 ;
    PORT
      LAYER Metal3 ;
        RECT 88.880 29.620 89.280 30.020 ;
    END
  END Tile_X0Y1_FrameData_O[8]
  PIN Tile_X0Y1_FrameData_O[9]
    DIRECTION OUTPUT ;
    USE SIGNAL ;
    ANTENNADIFFAREA 2.724000 ;
    PORT
      LAYER Metal3 ;
        RECT 88.880 32.140 89.280 32.540 ;
    END
  END Tile_X0Y1_FrameData_O[9]
  PIN Tile_X0Y1_FrameStrobe[0]
    DIRECTION INPUT ;
    USE SIGNAL ;
    ANTENNAGATEAREA 23.310299 ;
    ANTENNADIFFAREA 131.000992 ;
    PORT
      LAYER Metal2 ;
        RECT 70.360 0.000 70.760 0.400 ;
    END
  END Tile_X0Y1_FrameStrobe[0]
  PIN Tile_X0Y1_FrameStrobe[10]
    DIRECTION INPUT ;
    USE SIGNAL ;
    ANTENNAGATEAREA 0.180700 ;
    ANTENNADIFFAREA 2.015400 ;
    PORT
      LAYER Metal2 ;
        RECT 79.960 0.000 80.360 0.400 ;
    END
  END Tile_X0Y1_FrameStrobe[10]
  PIN Tile_X0Y1_FrameStrobe[11]
    DIRECTION INPUT ;
    USE SIGNAL ;
    ANTENNAGATEAREA 0.180700 ;
    ANTENNADIFFAREA 4.030800 ;
    PORT
      LAYER Metal2 ;
        RECT 80.920 0.000 81.320 0.400 ;
    END
  END Tile_X0Y1_FrameStrobe[11]
  PIN Tile_X0Y1_FrameStrobe[12]
    DIRECTION INPUT ;
    USE SIGNAL ;
    ANTENNAGATEAREA 0.180700 ;
    ANTENNADIFFAREA 2.015400 ;
    PORT
      LAYER Metal2 ;
        RECT 81.880 0.000 82.280 0.400 ;
    END
  END Tile_X0Y1_FrameStrobe[12]
  PIN Tile_X0Y1_FrameStrobe[13]
    DIRECTION INPUT ;
    USE SIGNAL ;
    ANTENNAGATEAREA 0.180700 ;
    ANTENNADIFFAREA 2.015400 ;
    PORT
      LAYER Metal2 ;
        RECT 82.840 0.000 83.240 0.400 ;
    END
  END Tile_X0Y1_FrameStrobe[13]
  PIN Tile_X0Y1_FrameStrobe[14]
    DIRECTION INPUT ;
    USE SIGNAL ;
    ANTENNAGATEAREA 0.180700 ;
    ANTENNADIFFAREA 4.030800 ;
    PORT
      LAYER Metal2 ;
        RECT 83.800 0.000 84.200 0.400 ;
    END
  END Tile_X0Y1_FrameStrobe[14]
  PIN Tile_X0Y1_FrameStrobe[15]
    DIRECTION INPUT ;
    USE SIGNAL ;
    ANTENNAGATEAREA 0.180700 ;
    ANTENNADIFFAREA 2.015400 ;
    PORT
      LAYER Metal2 ;
        RECT 84.760 0.000 85.160 0.400 ;
    END
  END Tile_X0Y1_FrameStrobe[15]
  PIN Tile_X0Y1_FrameStrobe[16]
    DIRECTION INPUT ;
    USE SIGNAL ;
    ANTENNAGATEAREA 0.180700 ;
    ANTENNADIFFAREA 2.015400 ;
    PORT
      LAYER Metal2 ;
        RECT 85.720 0.000 86.120 0.400 ;
    END
  END Tile_X0Y1_FrameStrobe[16]
  PIN Tile_X0Y1_FrameStrobe[17]
    DIRECTION INPUT ;
    USE SIGNAL ;
    ANTENNAGATEAREA 0.180700 ;
    ANTENNADIFFAREA 2.015400 ;
    PORT
      LAYER Metal2 ;
        RECT 86.680 0.000 87.080 0.400 ;
    END
  END Tile_X0Y1_FrameStrobe[17]
  PIN Tile_X0Y1_FrameStrobe[18]
    DIRECTION INPUT ;
    USE SIGNAL ;
    ANTENNAGATEAREA 0.180700 ;
    ANTENNADIFFAREA 4.030800 ;
    PORT
      LAYER Metal2 ;
        RECT 87.640 0.000 88.040 0.400 ;
    END
  END Tile_X0Y1_FrameStrobe[18]
  PIN Tile_X0Y1_FrameStrobe[19]
    DIRECTION INPUT ;
    USE SIGNAL ;
    ANTENNAGATEAREA 0.180700 ;
    ANTENNADIFFAREA 2.015400 ;
    PORT
      LAYER Metal2 ;
        RECT 88.600 0.000 89.000 0.400 ;
    END
  END Tile_X0Y1_FrameStrobe[19]
  PIN Tile_X0Y1_FrameStrobe[1]
    DIRECTION INPUT ;
    USE SIGNAL ;
    ANTENNAGATEAREA 23.310299 ;
    ANTENNADIFFAREA 131.000992 ;
    PORT
      LAYER Metal2 ;
        RECT 71.320 0.000 71.720 0.400 ;
    END
  END Tile_X0Y1_FrameStrobe[1]
  PIN Tile_X0Y1_FrameStrobe[2]
    DIRECTION INPUT ;
    USE SIGNAL ;
    ANTENNAGATEAREA 23.310299 ;
    ANTENNADIFFAREA 131.000992 ;
    PORT
      LAYER Metal2 ;
        RECT 72.280 0.000 72.680 0.400 ;
    END
  END Tile_X0Y1_FrameStrobe[2]
  PIN Tile_X0Y1_FrameStrobe[3]
    DIRECTION INPUT ;
    USE SIGNAL ;
    ANTENNAGATEAREA 23.310299 ;
    ANTENNADIFFAREA 131.000992 ;
    PORT
      LAYER Metal2 ;
        RECT 73.240 0.000 73.640 0.400 ;
    END
  END Tile_X0Y1_FrameStrobe[3]
  PIN Tile_X0Y1_FrameStrobe[4]
    DIRECTION INPUT ;
    USE SIGNAL ;
    ANTENNAGATEAREA 23.310299 ;
    ANTENNADIFFAREA 131.000992 ;
    PORT
      LAYER Metal2 ;
        RECT 74.200 0.000 74.600 0.400 ;
    END
  END Tile_X0Y1_FrameStrobe[4]
  PIN Tile_X0Y1_FrameStrobe[5]
    DIRECTION INPUT ;
    USE SIGNAL ;
    ANTENNAGATEAREA 23.310299 ;
    ANTENNADIFFAREA 131.000992 ;
    PORT
      LAYER Metal2 ;
        RECT 75.160 0.000 75.560 0.400 ;
    END
  END Tile_X0Y1_FrameStrobe[5]
  PIN Tile_X0Y1_FrameStrobe[6]
    DIRECTION INPUT ;
    USE SIGNAL ;
    ANTENNAGATEAREA 23.310299 ;
    ANTENNADIFFAREA 131.000992 ;
    PORT
      LAYER Metal2 ;
        RECT 76.120 0.000 76.520 0.400 ;
    END
  END Tile_X0Y1_FrameStrobe[6]
  PIN Tile_X0Y1_FrameStrobe[7]
    DIRECTION INPUT ;
    USE SIGNAL ;
    ANTENNAGATEAREA 22.587500 ;
    ANTENNADIFFAREA 126.970200 ;
    PORT
      LAYER Metal2 ;
        RECT 77.080 0.000 77.480 0.400 ;
    END
  END Tile_X0Y1_FrameStrobe[7]
  PIN Tile_X0Y1_FrameStrobe[8]
    DIRECTION INPUT ;
    USE SIGNAL ;
    ANTENNAGATEAREA 2.349100 ;
    ANTENNADIFFAREA 14.107800 ;
    PORT
      LAYER Metal2 ;
        RECT 78.040 0.000 78.440 0.400 ;
    END
  END Tile_X0Y1_FrameStrobe[8]
  PIN Tile_X0Y1_FrameStrobe[9]
    DIRECTION INPUT ;
    USE SIGNAL ;
    ANTENNAGATEAREA 0.180700 ;
    ANTENNADIFFAREA 2.015400 ;
    PORT
      LAYER Metal2 ;
        RECT 79.000 0.000 79.400 0.400 ;
    END
  END Tile_X0Y1_FrameStrobe[9]
  PIN Tile_X0Y1_N1END[0]
    DIRECTION INPUT ;
    USE SIGNAL ;
    ANTENNAGATEAREA 1.279200 ;
    ANTENNADIFFAREA 12.092400 ;
    PORT
      LAYER Metal2 ;
        RECT 1.240 0.000 1.640 0.400 ;
    END
  END Tile_X0Y1_N1END[0]
  PIN Tile_X0Y1_N1END[1]
    DIRECTION INPUT ;
    USE SIGNAL ;
    ANTENNAGATEAREA 1.279200 ;
    ANTENNADIFFAREA 12.092400 ;
    PORT
      LAYER Metal2 ;
        RECT 2.200 0.000 2.600 0.400 ;
    END
  END Tile_X0Y1_N1END[1]
  PIN Tile_X0Y1_N1END[2]
    DIRECTION INPUT ;
    USE SIGNAL ;
    ANTENNAGATEAREA 1.279200 ;
    ANTENNADIFFAREA 12.092400 ;
    PORT
      LAYER Metal2 ;
        RECT 3.160 0.000 3.560 0.400 ;
    END
  END Tile_X0Y1_N1END[2]
  PIN Tile_X0Y1_N1END[3]
    DIRECTION INPUT ;
    USE SIGNAL ;
    ANTENNAGATEAREA 1.279200 ;
    ANTENNADIFFAREA 12.092400 ;
    PORT
      LAYER Metal2 ;
        RECT 4.120 0.000 4.520 0.400 ;
    END
  END Tile_X0Y1_N1END[3]
  PIN Tile_X0Y1_N2END[0]
    DIRECTION INPUT ;
    USE SIGNAL ;
    ANTENNAGATEAREA 0.213200 ;
    ANTENNADIFFAREA 2.015400 ;
    PORT
      LAYER Metal2 ;
        RECT 12.760 0.000 13.160 0.400 ;
    END
  END Tile_X0Y1_N2END[0]
  PIN Tile_X0Y1_N2END[1]
    DIRECTION INPUT ;
    USE SIGNAL ;
    ANTENNAGATEAREA 0.213200 ;
    ANTENNADIFFAREA 2.015400 ;
    PORT
      LAYER Metal2 ;
        RECT 13.720 0.000 14.120 0.400 ;
    END
  END Tile_X0Y1_N2END[1]
  PIN Tile_X0Y1_N2END[2]
    DIRECTION INPUT ;
    USE SIGNAL ;
    ANTENNAGATEAREA 0.213200 ;
    ANTENNADIFFAREA 2.015400 ;
    PORT
      LAYER Metal2 ;
        RECT 14.680 0.000 15.080 0.400 ;
    END
  END Tile_X0Y1_N2END[2]
  PIN Tile_X0Y1_N2END[3]
    DIRECTION INPUT ;
    USE SIGNAL ;
    ANTENNAGATEAREA 0.213200 ;
    ANTENNADIFFAREA 2.015400 ;
    PORT
      LAYER Metal2 ;
        RECT 15.640 0.000 16.040 0.400 ;
    END
  END Tile_X0Y1_N2END[3]
  PIN Tile_X0Y1_N2END[4]
    DIRECTION INPUT ;
    USE SIGNAL ;
    ANTENNAGATEAREA 0.213200 ;
    ANTENNADIFFAREA 2.015400 ;
    PORT
      LAYER Metal2 ;
        RECT 16.600 0.000 17.000 0.400 ;
    END
  END Tile_X0Y1_N2END[4]
  PIN Tile_X0Y1_N2END[5]
    DIRECTION INPUT ;
    USE SIGNAL ;
    ANTENNAGATEAREA 0.213200 ;
    ANTENNADIFFAREA 2.015400 ;
    PORT
      LAYER Metal2 ;
        RECT 17.560 0.000 17.960 0.400 ;
    END
  END Tile_X0Y1_N2END[5]
  PIN Tile_X0Y1_N2END[6]
    DIRECTION INPUT ;
    USE SIGNAL ;
    ANTENNAGATEAREA 0.213200 ;
    ANTENNADIFFAREA 2.015400 ;
    PORT
      LAYER Metal2 ;
        RECT 18.520 0.000 18.920 0.400 ;
    END
  END Tile_X0Y1_N2END[6]
  PIN Tile_X0Y1_N2END[7]
    DIRECTION INPUT ;
    USE SIGNAL ;
    ANTENNAGATEAREA 0.213200 ;
    ANTENNADIFFAREA 2.015400 ;
    PORT
      LAYER Metal2 ;
        RECT 19.480 0.000 19.880 0.400 ;
    END
  END Tile_X0Y1_N2END[7]
  PIN Tile_X0Y1_N2MID[0]
    DIRECTION INPUT ;
    USE SIGNAL ;
    ANTENNAGATEAREA 0.426400 ;
    ANTENNADIFFAREA 4.030800 ;
    PORT
      LAYER Metal2 ;
        RECT 5.080 0.000 5.480 0.400 ;
    END
  END Tile_X0Y1_N2MID[0]
  PIN Tile_X0Y1_N2MID[1]
    DIRECTION INPUT ;
    USE SIGNAL ;
    ANTENNAGATEAREA 0.426400 ;
    ANTENNADIFFAREA 4.030800 ;
    PORT
      LAYER Metal2 ;
        RECT 6.040 0.000 6.440 0.400 ;
    END
  END Tile_X0Y1_N2MID[1]
  PIN Tile_X0Y1_N2MID[2]
    DIRECTION INPUT ;
    USE SIGNAL ;
    ANTENNAGATEAREA 0.426400 ;
    ANTENNADIFFAREA 4.030800 ;
    PORT
      LAYER Metal2 ;
        RECT 7.000 0.000 7.400 0.400 ;
    END
  END Tile_X0Y1_N2MID[2]
  PIN Tile_X0Y1_N2MID[3]
    DIRECTION INPUT ;
    USE SIGNAL ;
    ANTENNAGATEAREA 0.426400 ;
    ANTENNADIFFAREA 4.030800 ;
    PORT
      LAYER Metal2 ;
        RECT 7.960 0.000 8.360 0.400 ;
    END
  END Tile_X0Y1_N2MID[3]
  PIN Tile_X0Y1_N2MID[4]
    DIRECTION INPUT ;
    USE SIGNAL ;
    ANTENNAGATEAREA 0.426400 ;
    ANTENNADIFFAREA 4.030800 ;
    PORT
      LAYER Metal2 ;
        RECT 8.920 0.000 9.320 0.400 ;
    END
  END Tile_X0Y1_N2MID[4]
  PIN Tile_X0Y1_N2MID[5]
    DIRECTION INPUT ;
    USE SIGNAL ;
    ANTENNAGATEAREA 0.426400 ;
    ANTENNADIFFAREA 4.030800 ;
    PORT
      LAYER Metal2 ;
        RECT 9.880 0.000 10.280 0.400 ;
    END
  END Tile_X0Y1_N2MID[5]
  PIN Tile_X0Y1_N2MID[6]
    DIRECTION INPUT ;
    USE SIGNAL ;
    ANTENNAGATEAREA 0.426400 ;
    ANTENNADIFFAREA 4.030800 ;
    PORT
      LAYER Metal2 ;
        RECT 10.840 0.000 11.240 0.400 ;
    END
  END Tile_X0Y1_N2MID[6]
  PIN Tile_X0Y1_N2MID[7]
    DIRECTION INPUT ;
    USE SIGNAL ;
    ANTENNAGATEAREA 0.426400 ;
    ANTENNADIFFAREA 4.030800 ;
    PORT
      LAYER Metal2 ;
        RECT 11.800 0.000 12.200 0.400 ;
    END
  END Tile_X0Y1_N2MID[7]
  PIN Tile_X0Y1_N4END[0]
    DIRECTION INPUT ;
    USE SIGNAL ;
    ANTENNAGATEAREA 1.066000 ;
    ANTENNADIFFAREA 10.077000 ;
    PORT
      LAYER Metal2 ;
        RECT 20.440 0.000 20.840 0.400 ;
    END
  END Tile_X0Y1_N4END[0]
  PIN Tile_X0Y1_N4END[10]
    DIRECTION INPUT ;
    USE SIGNAL ;
    ANTENNAGATEAREA 0.180700 ;
    ANTENNADIFFAREA 2.015400 ;
    PORT
      LAYER Metal2 ;
        RECT 30.040 0.000 30.440 0.400 ;
    END
  END Tile_X0Y1_N4END[10]
  PIN Tile_X0Y1_N4END[11]
    DIRECTION INPUT ;
    USE SIGNAL ;
    ANTENNAGATEAREA 0.180700 ;
    ANTENNADIFFAREA 2.015400 ;
    PORT
      LAYER Metal2 ;
        RECT 31.000 0.000 31.400 0.400 ;
    END
  END Tile_X0Y1_N4END[11]
  PIN Tile_X0Y1_N4END[12]
    DIRECTION INPUT ;
    USE SIGNAL ;
    ANTENNAGATEAREA 0.180700 ;
    ANTENNADIFFAREA 2.015400 ;
    PORT
      LAYER Metal2 ;
        RECT 31.960 0.000 32.360 0.400 ;
    END
  END Tile_X0Y1_N4END[12]
  PIN Tile_X0Y1_N4END[13]
    DIRECTION INPUT ;
    USE SIGNAL ;
    ANTENNAGATEAREA 0.180700 ;
    ANTENNADIFFAREA 2.015400 ;
    PORT
      LAYER Metal2 ;
        RECT 32.920 0.000 33.320 0.400 ;
    END
  END Tile_X0Y1_N4END[13]
  PIN Tile_X0Y1_N4END[14]
    DIRECTION INPUT ;
    USE SIGNAL ;
    ANTENNAGATEAREA 0.180700 ;
    ANTENNADIFFAREA 2.015400 ;
    PORT
      LAYER Metal2 ;
        RECT 33.880 0.000 34.280 0.400 ;
    END
  END Tile_X0Y1_N4END[14]
  PIN Tile_X0Y1_N4END[15]
    DIRECTION INPUT ;
    USE SIGNAL ;
    ANTENNAGATEAREA 0.180700 ;
    ANTENNADIFFAREA 2.015400 ;
    PORT
      LAYER Metal2 ;
        RECT 34.840 0.000 35.240 0.400 ;
    END
  END Tile_X0Y1_N4END[15]
  PIN Tile_X0Y1_N4END[1]
    DIRECTION INPUT ;
    USE SIGNAL ;
    ANTENNAGATEAREA 1.066000 ;
    ANTENNADIFFAREA 10.077000 ;
    PORT
      LAYER Metal2 ;
        RECT 21.400 0.000 21.800 0.400 ;
    END
  END Tile_X0Y1_N4END[1]
  PIN Tile_X0Y1_N4END[2]
    DIRECTION INPUT ;
    USE SIGNAL ;
    ANTENNAGATEAREA 1.066000 ;
    ANTENNADIFFAREA 10.077000 ;
    PORT
      LAYER Metal2 ;
        RECT 22.360 0.000 22.760 0.400 ;
    END
  END Tile_X0Y1_N4END[2]
  PIN Tile_X0Y1_N4END[3]
    DIRECTION INPUT ;
    USE SIGNAL ;
    ANTENNAGATEAREA 1.066000 ;
    ANTENNADIFFAREA 10.077000 ;
    PORT
      LAYER Metal2 ;
        RECT 23.320 0.000 23.720 0.400 ;
    END
  END Tile_X0Y1_N4END[3]
  PIN Tile_X0Y1_N4END[4]
    DIRECTION INPUT ;
    USE SIGNAL ;
    ANTENNAGATEAREA 1.066000 ;
    ANTENNADIFFAREA 10.077000 ;
    PORT
      LAYER Metal2 ;
        RECT 24.280 0.000 24.680 0.400 ;
    END
  END Tile_X0Y1_N4END[4]
  PIN Tile_X0Y1_N4END[5]
    DIRECTION INPUT ;
    USE SIGNAL ;
    ANTENNAGATEAREA 1.066000 ;
    ANTENNADIFFAREA 10.077000 ;
    PORT
      LAYER Metal2 ;
        RECT 25.240 0.000 25.640 0.400 ;
    END
  END Tile_X0Y1_N4END[5]
  PIN Tile_X0Y1_N4END[6]
    DIRECTION INPUT ;
    USE SIGNAL ;
    ANTENNAGATEAREA 1.066000 ;
    ANTENNADIFFAREA 10.077000 ;
    PORT
      LAYER Metal2 ;
        RECT 26.200 0.000 26.600 0.400 ;
    END
  END Tile_X0Y1_N4END[6]
  PIN Tile_X0Y1_N4END[7]
    DIRECTION INPUT ;
    USE SIGNAL ;
    ANTENNAGATEAREA 1.066000 ;
    ANTENNADIFFAREA 10.077000 ;
    PORT
      LAYER Metal2 ;
        RECT 27.160 0.000 27.560 0.400 ;
    END
  END Tile_X0Y1_N4END[7]
  PIN Tile_X0Y1_N4END[8]
    DIRECTION INPUT ;
    USE SIGNAL ;
    ANTENNAGATEAREA 0.180700 ;
    ANTENNADIFFAREA 2.015400 ;
    PORT
      LAYER Metal2 ;
        RECT 28.120 0.000 28.520 0.400 ;
    END
  END Tile_X0Y1_N4END[8]
  PIN Tile_X0Y1_N4END[9]
    DIRECTION INPUT ;
    USE SIGNAL ;
    ANTENNAGATEAREA 0.180700 ;
    ANTENNADIFFAREA 2.015400 ;
    PORT
      LAYER Metal2 ;
        RECT 29.080 0.000 29.480 0.400 ;
    END
  END Tile_X0Y1_N4END[9]
  PIN Tile_X0Y1_S1BEG[0]
    DIRECTION OUTPUT ;
    USE SIGNAL ;
    ANTENNADIFFAREA 2.724000 ;
    PORT
      LAYER Metal2 ;
        RECT 35.800 0.000 36.200 0.400 ;
    END
  END Tile_X0Y1_S1BEG[0]
  PIN Tile_X0Y1_S1BEG[1]
    DIRECTION OUTPUT ;
    USE SIGNAL ;
    ANTENNADIFFAREA 2.724000 ;
    PORT
      LAYER Metal2 ;
        RECT 36.760 0.000 37.160 0.400 ;
    END
  END Tile_X0Y1_S1BEG[1]
  PIN Tile_X0Y1_S1BEG[2]
    DIRECTION OUTPUT ;
    USE SIGNAL ;
    ANTENNADIFFAREA 2.724000 ;
    PORT
      LAYER Metal2 ;
        RECT 37.720 0.000 38.120 0.400 ;
    END
  END Tile_X0Y1_S1BEG[2]
  PIN Tile_X0Y1_S1BEG[3]
    DIRECTION OUTPUT ;
    USE SIGNAL ;
    ANTENNADIFFAREA 2.724000 ;
    PORT
      LAYER Metal2 ;
        RECT 38.680 0.000 39.080 0.400 ;
    END
  END Tile_X0Y1_S1BEG[3]
  PIN Tile_X0Y1_S2BEG[0]
    DIRECTION OUTPUT ;
    USE SIGNAL ;
    ANTENNADIFFAREA 2.724000 ;
    PORT
      LAYER Metal2 ;
        RECT 39.640 0.000 40.040 0.400 ;
    END
  END Tile_X0Y1_S2BEG[0]
  PIN Tile_X0Y1_S2BEG[1]
    DIRECTION OUTPUT ;
    USE SIGNAL ;
    ANTENNADIFFAREA 2.724000 ;
    PORT
      LAYER Metal2 ;
        RECT 40.600 0.000 41.000 0.400 ;
    END
  END Tile_X0Y1_S2BEG[1]
  PIN Tile_X0Y1_S2BEG[2]
    DIRECTION OUTPUT ;
    USE SIGNAL ;
    ANTENNADIFFAREA 2.724000 ;
    PORT
      LAYER Metal2 ;
        RECT 41.560 0.000 41.960 0.400 ;
    END
  END Tile_X0Y1_S2BEG[2]
  PIN Tile_X0Y1_S2BEG[3]
    DIRECTION OUTPUT ;
    USE SIGNAL ;
    ANTENNADIFFAREA 2.724000 ;
    PORT
      LAYER Metal2 ;
        RECT 42.520 0.000 42.920 0.400 ;
    END
  END Tile_X0Y1_S2BEG[3]
  PIN Tile_X0Y1_S2BEG[4]
    DIRECTION OUTPUT ;
    USE SIGNAL ;
    ANTENNADIFFAREA 2.724000 ;
    PORT
      LAYER Metal2 ;
        RECT 43.480 0.000 43.880 0.400 ;
    END
  END Tile_X0Y1_S2BEG[4]
  PIN Tile_X0Y1_S2BEG[5]
    DIRECTION OUTPUT ;
    USE SIGNAL ;
    ANTENNADIFFAREA 2.724000 ;
    PORT
      LAYER Metal2 ;
        RECT 44.440 0.000 44.840 0.400 ;
    END
  END Tile_X0Y1_S2BEG[5]
  PIN Tile_X0Y1_S2BEG[6]
    DIRECTION OUTPUT ;
    USE SIGNAL ;
    ANTENNADIFFAREA 2.724000 ;
    PORT
      LAYER Metal2 ;
        RECT 45.400 0.000 45.800 0.400 ;
    END
  END Tile_X0Y1_S2BEG[6]
  PIN Tile_X0Y1_S2BEG[7]
    DIRECTION OUTPUT ;
    USE SIGNAL ;
    ANTENNADIFFAREA 2.724000 ;
    PORT
      LAYER Metal2 ;
        RECT 46.360 0.000 46.760 0.400 ;
    END
  END Tile_X0Y1_S2BEG[7]
  PIN Tile_X0Y1_S2BEGb[0]
    DIRECTION OUTPUT ;
    USE SIGNAL ;
    ANTENNADIFFAREA 2.724000 ;
    PORT
      LAYER Metal2 ;
        RECT 47.320 0.000 47.720 0.400 ;
    END
  END Tile_X0Y1_S2BEGb[0]
  PIN Tile_X0Y1_S2BEGb[1]
    DIRECTION OUTPUT ;
    USE SIGNAL ;
    ANTENNADIFFAREA 2.724000 ;
    PORT
      LAYER Metal2 ;
        RECT 48.280 0.000 48.680 0.400 ;
    END
  END Tile_X0Y1_S2BEGb[1]
  PIN Tile_X0Y1_S2BEGb[2]
    DIRECTION OUTPUT ;
    USE SIGNAL ;
    ANTENNADIFFAREA 2.724000 ;
    PORT
      LAYER Metal2 ;
        RECT 49.240 0.000 49.640 0.400 ;
    END
  END Tile_X0Y1_S2BEGb[2]
  PIN Tile_X0Y1_S2BEGb[3]
    DIRECTION OUTPUT ;
    USE SIGNAL ;
    ANTENNADIFFAREA 2.724000 ;
    PORT
      LAYER Metal2 ;
        RECT 50.200 0.000 50.600 0.400 ;
    END
  END Tile_X0Y1_S2BEGb[3]
  PIN Tile_X0Y1_S2BEGb[4]
    DIRECTION OUTPUT ;
    USE SIGNAL ;
    ANTENNADIFFAREA 2.724000 ;
    PORT
      LAYER Metal2 ;
        RECT 51.160 0.000 51.560 0.400 ;
    END
  END Tile_X0Y1_S2BEGb[4]
  PIN Tile_X0Y1_S2BEGb[5]
    DIRECTION OUTPUT ;
    USE SIGNAL ;
    ANTENNADIFFAREA 2.724000 ;
    PORT
      LAYER Metal2 ;
        RECT 52.120 0.000 52.520 0.400 ;
    END
  END Tile_X0Y1_S2BEGb[5]
  PIN Tile_X0Y1_S2BEGb[6]
    DIRECTION OUTPUT ;
    USE SIGNAL ;
    ANTENNADIFFAREA 2.724000 ;
    PORT
      LAYER Metal2 ;
        RECT 53.080 0.000 53.480 0.400 ;
    END
  END Tile_X0Y1_S2BEGb[6]
  PIN Tile_X0Y1_S2BEGb[7]
    DIRECTION OUTPUT ;
    USE SIGNAL ;
    ANTENNADIFFAREA 2.724000 ;
    PORT
      LAYER Metal2 ;
        RECT 54.040 0.000 54.440 0.400 ;
    END
  END Tile_X0Y1_S2BEGb[7]
  PIN Tile_X0Y1_S4BEG[0]
    DIRECTION OUTPUT ;
    USE SIGNAL ;
    ANTENNADIFFAREA 2.724000 ;
    PORT
      LAYER Metal2 ;
        RECT 55.000 0.000 55.400 0.400 ;
    END
  END Tile_X0Y1_S4BEG[0]
  PIN Tile_X0Y1_S4BEG[10]
    DIRECTION OUTPUT ;
    USE SIGNAL ;
    ANTENNADIFFAREA 2.724000 ;
    PORT
      LAYER Metal2 ;
        RECT 64.600 0.000 65.000 0.400 ;
    END
  END Tile_X0Y1_S4BEG[10]
  PIN Tile_X0Y1_S4BEG[11]
    DIRECTION OUTPUT ;
    USE SIGNAL ;
    ANTENNADIFFAREA 2.724000 ;
    PORT
      LAYER Metal2 ;
        RECT 65.560 0.000 65.960 0.400 ;
    END
  END Tile_X0Y1_S4BEG[11]
  PIN Tile_X0Y1_S4BEG[12]
    DIRECTION OUTPUT ;
    USE SIGNAL ;
    ANTENNADIFFAREA 2.724000 ;
    PORT
      LAYER Metal2 ;
        RECT 66.520 0.000 66.920 0.400 ;
    END
  END Tile_X0Y1_S4BEG[12]
  PIN Tile_X0Y1_S4BEG[13]
    DIRECTION OUTPUT ;
    USE SIGNAL ;
    ANTENNADIFFAREA 2.724000 ;
    PORT
      LAYER Metal2 ;
        RECT 67.480 0.000 67.880 0.400 ;
    END
  END Tile_X0Y1_S4BEG[13]
  PIN Tile_X0Y1_S4BEG[14]
    DIRECTION OUTPUT ;
    USE SIGNAL ;
    ANTENNADIFFAREA 2.724000 ;
    PORT
      LAYER Metal2 ;
        RECT 68.440 0.000 68.840 0.400 ;
    END
  END Tile_X0Y1_S4BEG[14]
  PIN Tile_X0Y1_S4BEG[15]
    DIRECTION OUTPUT ;
    USE SIGNAL ;
    ANTENNADIFFAREA 2.724000 ;
    PORT
      LAYER Metal2 ;
        RECT 69.400 0.000 69.800 0.400 ;
    END
  END Tile_X0Y1_S4BEG[15]
  PIN Tile_X0Y1_S4BEG[1]
    DIRECTION OUTPUT ;
    USE SIGNAL ;
    ANTENNADIFFAREA 2.724000 ;
    PORT
      LAYER Metal2 ;
        RECT 55.960 0.000 56.360 0.400 ;
    END
  END Tile_X0Y1_S4BEG[1]
  PIN Tile_X0Y1_S4BEG[2]
    DIRECTION OUTPUT ;
    USE SIGNAL ;
    ANTENNADIFFAREA 2.724000 ;
    PORT
      LAYER Metal2 ;
        RECT 56.920 0.000 57.320 0.400 ;
    END
  END Tile_X0Y1_S4BEG[2]
  PIN Tile_X0Y1_S4BEG[3]
    DIRECTION OUTPUT ;
    USE SIGNAL ;
    ANTENNADIFFAREA 2.724000 ;
    PORT
      LAYER Metal2 ;
        RECT 57.880 0.000 58.280 0.400 ;
    END
  END Tile_X0Y1_S4BEG[3]
  PIN Tile_X0Y1_S4BEG[4]
    DIRECTION OUTPUT ;
    USE SIGNAL ;
    ANTENNADIFFAREA 2.724000 ;
    PORT
      LAYER Metal2 ;
        RECT 58.840 0.000 59.240 0.400 ;
    END
  END Tile_X0Y1_S4BEG[4]
  PIN Tile_X0Y1_S4BEG[5]
    DIRECTION OUTPUT ;
    USE SIGNAL ;
    ANTENNADIFFAREA 2.724000 ;
    PORT
      LAYER Metal2 ;
        RECT 59.800 0.000 60.200 0.400 ;
    END
  END Tile_X0Y1_S4BEG[5]
  PIN Tile_X0Y1_S4BEG[6]
    DIRECTION OUTPUT ;
    USE SIGNAL ;
    ANTENNADIFFAREA 2.724000 ;
    PORT
      LAYER Metal2 ;
        RECT 60.760 0.000 61.160 0.400 ;
    END
  END Tile_X0Y1_S4BEG[6]
  PIN Tile_X0Y1_S4BEG[7]
    DIRECTION OUTPUT ;
    USE SIGNAL ;
    ANTENNADIFFAREA 2.724000 ;
    PORT
      LAYER Metal2 ;
        RECT 61.720 0.000 62.120 0.400 ;
    END
  END Tile_X0Y1_S4BEG[7]
  PIN Tile_X0Y1_S4BEG[8]
    DIRECTION OUTPUT ;
    USE SIGNAL ;
    ANTENNADIFFAREA 2.724000 ;
    PORT
      LAYER Metal2 ;
        RECT 62.680 0.000 63.080 0.400 ;
    END
  END Tile_X0Y1_S4BEG[8]
  PIN Tile_X0Y1_S4BEG[9]
    DIRECTION OUTPUT ;
    USE SIGNAL ;
    ANTENNADIFFAREA 2.724000 ;
    PORT
      LAYER Metal2 ;
        RECT 63.640 0.000 64.040 0.400 ;
    END
  END Tile_X0Y1_S4BEG[9]
  PIN Tile_X0Y1_UserCLK
    DIRECTION INPUT ;
    USE SIGNAL ;
    ANTENNAGATEAREA 11.726000 ;
    ANTENNADIFFAREA 98.754601 ;
    PORT
      LAYER Metal3 ;
        RECT 0.000 171.580 0.400 171.980 ;
    END
  END Tile_X0Y1_UserCLK
  PIN Tile_X0Y1_UserCLKo
    DIRECTION OUTPUT ;
    USE SIGNAL ;
    ANTENNADIFFAREA 2.724000 ;
    PORT
      LAYER Metal3 ;
        RECT 88.880 1.900 89.280 2.300 ;
    END
  END Tile_X0Y1_UserCLKo
  PIN Tile_X0Y1_W1BEG[0]
    DIRECTION OUTPUT ;
    USE SIGNAL ;
    ANTENNADIFFAREA 2.724000 ;
    PORT
      LAYER Metal3 ;
        RECT 0.000 85.900 0.400 86.300 ;
    END
  END Tile_X0Y1_W1BEG[0]
  PIN Tile_X0Y1_W1BEG[1]
    DIRECTION OUTPUT ;
    USE SIGNAL ;
    ANTENNADIFFAREA 2.724000 ;
    PORT
      LAYER Metal3 ;
        RECT 0.000 87.580 0.400 87.980 ;
    END
  END Tile_X0Y1_W1BEG[1]
  PIN Tile_X0Y1_W1BEG[2]
    DIRECTION OUTPUT ;
    USE SIGNAL ;
    ANTENNADIFFAREA 2.724000 ;
    PORT
      LAYER Metal3 ;
        RECT 0.000 89.260 0.400 89.660 ;
    END
  END Tile_X0Y1_W1BEG[2]
  PIN Tile_X0Y1_W1BEG[3]
    DIRECTION OUTPUT ;
    USE SIGNAL ;
    ANTENNADIFFAREA 2.724000 ;
    PORT
      LAYER Metal3 ;
        RECT 0.000 90.940 0.400 91.340 ;
    END
  END Tile_X0Y1_W1BEG[3]
  PIN Tile_X0Y1_W2BEG[0]
    DIRECTION OUTPUT ;
    USE SIGNAL ;
    ANTENNADIFFAREA 2.724000 ;
    PORT
      LAYER Metal3 ;
        RECT 0.000 93.460 0.400 93.860 ;
    END
  END Tile_X0Y1_W2BEG[0]
  PIN Tile_X0Y1_W2BEG[1]
    DIRECTION OUTPUT ;
    USE SIGNAL ;
    ANTENNADIFFAREA 2.724000 ;
    PORT
      LAYER Metal3 ;
        RECT 0.000 95.140 0.400 95.540 ;
    END
  END Tile_X0Y1_W2BEG[1]
  PIN Tile_X0Y1_W2BEG[2]
    DIRECTION OUTPUT ;
    USE SIGNAL ;
    ANTENNADIFFAREA 2.724000 ;
    PORT
      LAYER Metal3 ;
        RECT 0.000 96.820 0.400 97.220 ;
    END
  END Tile_X0Y1_W2BEG[2]
  PIN Tile_X0Y1_W2BEG[3]
    DIRECTION OUTPUT ;
    USE SIGNAL ;
    ANTENNADIFFAREA 2.724000 ;
    PORT
      LAYER Metal3 ;
        RECT 0.000 98.500 0.400 98.900 ;
    END
  END Tile_X0Y1_W2BEG[3]
  PIN Tile_X0Y1_W2BEG[4]
    DIRECTION OUTPUT ;
    USE SIGNAL ;
    ANTENNADIFFAREA 2.724000 ;
    PORT
      LAYER Metal3 ;
        RECT 0.000 100.180 0.400 100.580 ;
    END
  END Tile_X0Y1_W2BEG[4]
  PIN Tile_X0Y1_W2BEG[5]
    DIRECTION OUTPUT ;
    USE SIGNAL ;
    ANTENNADIFFAREA 2.724000 ;
    PORT
      LAYER Metal3 ;
        RECT 0.000 101.860 0.400 102.260 ;
    END
  END Tile_X0Y1_W2BEG[5]
  PIN Tile_X0Y1_W2BEG[6]
    DIRECTION OUTPUT ;
    USE SIGNAL ;
    ANTENNADIFFAREA 2.724000 ;
    PORT
      LAYER Metal3 ;
        RECT 0.000 103.540 0.400 103.940 ;
    END
  END Tile_X0Y1_W2BEG[6]
  PIN Tile_X0Y1_W2BEG[7]
    DIRECTION OUTPUT ;
    USE SIGNAL ;
    ANTENNADIFFAREA 2.724000 ;
    PORT
      LAYER Metal3 ;
        RECT 0.000 105.220 0.400 105.620 ;
    END
  END Tile_X0Y1_W2BEG[7]
  PIN Tile_X0Y1_W2BEGb[0]
    DIRECTION OUTPUT ;
    USE SIGNAL ;
    ANTENNADIFFAREA 2.724000 ;
    PORT
      LAYER Metal3 ;
        RECT 0.000 107.740 0.400 108.140 ;
    END
  END Tile_X0Y1_W2BEGb[0]
  PIN Tile_X0Y1_W2BEGb[1]
    DIRECTION OUTPUT ;
    USE SIGNAL ;
    ANTENNADIFFAREA 2.724000 ;
    PORT
      LAYER Metal3 ;
        RECT 0.000 109.420 0.400 109.820 ;
    END
  END Tile_X0Y1_W2BEGb[1]
  PIN Tile_X0Y1_W2BEGb[2]
    DIRECTION OUTPUT ;
    USE SIGNAL ;
    ANTENNADIFFAREA 2.724000 ;
    PORT
      LAYER Metal3 ;
        RECT 0.000 111.100 0.400 111.500 ;
    END
  END Tile_X0Y1_W2BEGb[2]
  PIN Tile_X0Y1_W2BEGb[3]
    DIRECTION OUTPUT ;
    USE SIGNAL ;
    ANTENNADIFFAREA 2.724000 ;
    PORT
      LAYER Metal3 ;
        RECT 0.000 112.780 0.400 113.180 ;
    END
  END Tile_X0Y1_W2BEGb[3]
  PIN Tile_X0Y1_W2BEGb[4]
    DIRECTION OUTPUT ;
    USE SIGNAL ;
    ANTENNADIFFAREA 2.724000 ;
    PORT
      LAYER Metal3 ;
        RECT 0.000 114.460 0.400 114.860 ;
    END
  END Tile_X0Y1_W2BEGb[4]
  PIN Tile_X0Y1_W2BEGb[5]
    DIRECTION OUTPUT ;
    USE SIGNAL ;
    ANTENNADIFFAREA 2.724000 ;
    PORT
      LAYER Metal3 ;
        RECT 0.000 116.140 0.400 116.540 ;
    END
  END Tile_X0Y1_W2BEGb[5]
  PIN Tile_X0Y1_W2BEGb[6]
    DIRECTION OUTPUT ;
    USE SIGNAL ;
    ANTENNADIFFAREA 2.724000 ;
    PORT
      LAYER Metal3 ;
        RECT 0.000 117.820 0.400 118.220 ;
    END
  END Tile_X0Y1_W2BEGb[6]
  PIN Tile_X0Y1_W2BEGb[7]
    DIRECTION OUTPUT ;
    USE SIGNAL ;
    ANTENNADIFFAREA 2.724000 ;
    PORT
      LAYER Metal3 ;
        RECT 0.000 119.500 0.400 119.900 ;
    END
  END Tile_X0Y1_W2BEGb[7]
  PIN Tile_X0Y1_W6BEG[0]
    DIRECTION OUTPUT ;
    USE SIGNAL ;
    ANTENNADIFFAREA 2.724000 ;
    PORT
      LAYER Metal3 ;
        RECT 0.000 150.580 0.400 150.980 ;
    END
  END Tile_X0Y1_W6BEG[0]
  PIN Tile_X0Y1_W6BEG[10]
    DIRECTION OUTPUT ;
    USE SIGNAL ;
    ANTENNADIFFAREA 2.724000 ;
    PORT
      LAYER Metal3 ;
        RECT 0.000 167.380 0.400 167.780 ;
    END
  END Tile_X0Y1_W6BEG[10]
  PIN Tile_X0Y1_W6BEG[11]
    DIRECTION OUTPUT ;
    USE SIGNAL ;
    ANTENNADIFFAREA 2.724000 ;
    PORT
      LAYER Metal3 ;
        RECT 0.000 169.060 0.400 169.460 ;
    END
  END Tile_X0Y1_W6BEG[11]
  PIN Tile_X0Y1_W6BEG[1]
    DIRECTION OUTPUT ;
    USE SIGNAL ;
    ANTENNADIFFAREA 2.724000 ;
    PORT
      LAYER Metal3 ;
        RECT 0.000 152.260 0.400 152.660 ;
    END
  END Tile_X0Y1_W6BEG[1]
  PIN Tile_X0Y1_W6BEG[2]
    DIRECTION OUTPUT ;
    USE SIGNAL ;
    ANTENNADIFFAREA 2.724000 ;
    PORT
      LAYER Metal3 ;
        RECT 0.000 153.940 0.400 154.340 ;
    END
  END Tile_X0Y1_W6BEG[2]
  PIN Tile_X0Y1_W6BEG[3]
    DIRECTION OUTPUT ;
    USE SIGNAL ;
    ANTENNADIFFAREA 2.724000 ;
    PORT
      LAYER Metal3 ;
        RECT 0.000 155.620 0.400 156.020 ;
    END
  END Tile_X0Y1_W6BEG[3]
  PIN Tile_X0Y1_W6BEG[4]
    DIRECTION OUTPUT ;
    USE SIGNAL ;
    ANTENNADIFFAREA 2.724000 ;
    PORT
      LAYER Metal3 ;
        RECT 0.000 157.300 0.400 157.700 ;
    END
  END Tile_X0Y1_W6BEG[4]
  PIN Tile_X0Y1_W6BEG[5]
    DIRECTION OUTPUT ;
    USE SIGNAL ;
    ANTENNADIFFAREA 2.724000 ;
    PORT
      LAYER Metal3 ;
        RECT 0.000 158.980 0.400 159.380 ;
    END
  END Tile_X0Y1_W6BEG[5]
  PIN Tile_X0Y1_W6BEG[6]
    DIRECTION OUTPUT ;
    USE SIGNAL ;
    ANTENNADIFFAREA 2.724000 ;
    PORT
      LAYER Metal3 ;
        RECT 0.000 160.660 0.400 161.060 ;
    END
  END Tile_X0Y1_W6BEG[6]
  PIN Tile_X0Y1_W6BEG[7]
    DIRECTION OUTPUT ;
    USE SIGNAL ;
    ANTENNADIFFAREA 2.724000 ;
    PORT
      LAYER Metal3 ;
        RECT 0.000 162.340 0.400 162.740 ;
    END
  END Tile_X0Y1_W6BEG[7]
  PIN Tile_X0Y1_W6BEG[8]
    DIRECTION OUTPUT ;
    USE SIGNAL ;
    ANTENNADIFFAREA 2.724000 ;
    PORT
      LAYER Metal3 ;
        RECT 0.000 164.020 0.400 164.420 ;
    END
  END Tile_X0Y1_W6BEG[8]
  PIN Tile_X0Y1_W6BEG[9]
    DIRECTION OUTPUT ;
    USE SIGNAL ;
    ANTENNADIFFAREA 2.724000 ;
    PORT
      LAYER Metal3 ;
        RECT 0.000 165.700 0.400 166.100 ;
    END
  END Tile_X0Y1_W6BEG[9]
  PIN Tile_X0Y1_WW4BEG[0]
    DIRECTION OUTPUT ;
    USE SIGNAL ;
    ANTENNADIFFAREA 2.724000 ;
    PORT
      LAYER Metal3 ;
        RECT 0.000 122.020 0.400 122.420 ;
    END
  END Tile_X0Y1_WW4BEG[0]
  PIN Tile_X0Y1_WW4BEG[10]
    DIRECTION OUTPUT ;
    USE SIGNAL ;
    ANTENNADIFFAREA 2.724000 ;
    PORT
      LAYER Metal3 ;
        RECT 0.000 138.820 0.400 139.220 ;
    END
  END Tile_X0Y1_WW4BEG[10]
  PIN Tile_X0Y1_WW4BEG[11]
    DIRECTION OUTPUT ;
    USE SIGNAL ;
    ANTENNADIFFAREA 2.724000 ;
    PORT
      LAYER Metal3 ;
        RECT 0.000 140.500 0.400 140.900 ;
    END
  END Tile_X0Y1_WW4BEG[11]
  PIN Tile_X0Y1_WW4BEG[12]
    DIRECTION OUTPUT ;
    USE SIGNAL ;
    ANTENNADIFFAREA 2.724000 ;
    PORT
      LAYER Metal3 ;
        RECT 0.000 142.180 0.400 142.580 ;
    END
  END Tile_X0Y1_WW4BEG[12]
  PIN Tile_X0Y1_WW4BEG[13]
    DIRECTION OUTPUT ;
    USE SIGNAL ;
    ANTENNADIFFAREA 2.724000 ;
    PORT
      LAYER Metal3 ;
        RECT 0.000 143.860 0.400 144.260 ;
    END
  END Tile_X0Y1_WW4BEG[13]
  PIN Tile_X0Y1_WW4BEG[14]
    DIRECTION OUTPUT ;
    USE SIGNAL ;
    ANTENNADIFFAREA 2.724000 ;
    PORT
      LAYER Metal3 ;
        RECT 0.000 145.540 0.400 145.940 ;
    END
  END Tile_X0Y1_WW4BEG[14]
  PIN Tile_X0Y1_WW4BEG[15]
    DIRECTION OUTPUT ;
    USE SIGNAL ;
    ANTENNADIFFAREA 2.724000 ;
    PORT
      LAYER Metal3 ;
        RECT 0.000 147.220 0.400 147.620 ;
    END
  END Tile_X0Y1_WW4BEG[15]
  PIN Tile_X0Y1_WW4BEG[1]
    DIRECTION OUTPUT ;
    USE SIGNAL ;
    ANTENNADIFFAREA 2.724000 ;
    PORT
      LAYER Metal3 ;
        RECT 0.000 123.700 0.400 124.100 ;
    END
  END Tile_X0Y1_WW4BEG[1]
  PIN Tile_X0Y1_WW4BEG[2]
    DIRECTION OUTPUT ;
    USE SIGNAL ;
    ANTENNADIFFAREA 2.724000 ;
    PORT
      LAYER Metal3 ;
        RECT 0.000 125.380 0.400 125.780 ;
    END
  END Tile_X0Y1_WW4BEG[2]
  PIN Tile_X0Y1_WW4BEG[3]
    DIRECTION OUTPUT ;
    USE SIGNAL ;
    ANTENNADIFFAREA 2.724000 ;
    PORT
      LAYER Metal3 ;
        RECT 0.000 127.060 0.400 127.460 ;
    END
  END Tile_X0Y1_WW4BEG[3]
  PIN Tile_X0Y1_WW4BEG[4]
    DIRECTION OUTPUT ;
    USE SIGNAL ;
    ANTENNADIFFAREA 2.724000 ;
    PORT
      LAYER Metal3 ;
        RECT 0.000 128.740 0.400 129.140 ;
    END
  END Tile_X0Y1_WW4BEG[4]
  PIN Tile_X0Y1_WW4BEG[5]
    DIRECTION OUTPUT ;
    USE SIGNAL ;
    ANTENNADIFFAREA 2.724000 ;
    PORT
      LAYER Metal3 ;
        RECT 0.000 130.420 0.400 130.820 ;
    END
  END Tile_X0Y1_WW4BEG[5]
  PIN Tile_X0Y1_WW4BEG[6]
    DIRECTION OUTPUT ;
    USE SIGNAL ;
    ANTENNADIFFAREA 2.724000 ;
    PORT
      LAYER Metal3 ;
        RECT 0.000 132.100 0.400 132.500 ;
    END
  END Tile_X0Y1_WW4BEG[6]
  PIN Tile_X0Y1_WW4BEG[7]
    DIRECTION OUTPUT ;
    USE SIGNAL ;
    ANTENNADIFFAREA 2.724000 ;
    PORT
      LAYER Metal3 ;
        RECT 0.000 133.780 0.400 134.180 ;
    END
  END Tile_X0Y1_WW4BEG[7]
  PIN Tile_X0Y1_WW4BEG[8]
    DIRECTION OUTPUT ;
    USE SIGNAL ;
    ANTENNADIFFAREA 2.724000 ;
    PORT
      LAYER Metal3 ;
        RECT 0.000 135.460 0.400 135.860 ;
    END
  END Tile_X0Y1_WW4BEG[8]
  PIN Tile_X0Y1_WW4BEG[9]
    DIRECTION OUTPUT ;
    USE SIGNAL ;
    ANTENNADIFFAREA 2.724000 ;
    PORT
      LAYER Metal3 ;
        RECT 0.000 137.140 0.400 137.540 ;
    END
  END Tile_X0Y1_WW4BEG[9]
  PIN VGND
    DIRECTION INOUT ;
    USE GROUND ;
    PORT
      LAYER Metal4 ;
        RECT 13.940 0.000 14.940 460.320 ;
    END
    PORT
      LAYER Metal4 ;
        RECT 63.940 0.000 64.940 460.320 ;
    END
  END VGND
  PIN VPWR
    DIRECTION INOUT ;
    USE POWER ;
    PORT
      LAYER Metal4 ;
        RECT 10.940 0.000 11.940 460.320 ;
    END
    PORT
      LAYER Metal4 ;
        RECT 60.940 0.000 61.940 460.320 ;
    END
  END VPWR
  OBS
      LAYER GatPoly ;
        RECT 1.440 3.630 87.840 453.750 ;
      LAYER Metal1 ;
        RECT 1.440 3.560 87.840 453.820 ;
      LAYER Metal2 ;
        RECT 0.375 459.710 1.030 460.000 ;
        RECT 1.850 459.710 1.990 460.000 ;
        RECT 2.810 459.710 2.950 460.000 ;
        RECT 3.770 459.710 3.910 460.000 ;
        RECT 4.730 459.710 4.870 460.000 ;
        RECT 5.690 459.710 5.830 460.000 ;
        RECT 6.650 459.710 6.790 460.000 ;
        RECT 7.610 459.710 7.750 460.000 ;
        RECT 8.570 459.710 8.710 460.000 ;
        RECT 9.530 459.710 9.670 460.000 ;
        RECT 10.490 459.710 10.630 460.000 ;
        RECT 11.450 459.710 11.590 460.000 ;
        RECT 12.410 459.710 12.550 460.000 ;
        RECT 13.370 459.710 13.510 460.000 ;
        RECT 14.330 459.710 14.470 460.000 ;
        RECT 15.290 459.710 15.430 460.000 ;
        RECT 16.250 459.710 16.390 460.000 ;
        RECT 17.210 459.710 17.350 460.000 ;
        RECT 18.170 459.710 18.310 460.000 ;
        RECT 19.130 459.710 19.270 460.000 ;
        RECT 20.090 459.710 20.230 460.000 ;
        RECT 21.050 459.710 21.190 460.000 ;
        RECT 22.010 459.710 22.150 460.000 ;
        RECT 22.970 459.710 23.110 460.000 ;
        RECT 23.930 459.710 24.070 460.000 ;
        RECT 24.890 459.710 25.030 460.000 ;
        RECT 25.850 459.710 25.990 460.000 ;
        RECT 26.810 459.710 26.950 460.000 ;
        RECT 27.770 459.710 27.910 460.000 ;
        RECT 28.730 459.710 28.870 460.000 ;
        RECT 29.690 459.710 29.830 460.000 ;
        RECT 30.650 459.710 30.790 460.000 ;
        RECT 31.610 459.710 31.750 460.000 ;
        RECT 32.570 459.710 32.710 460.000 ;
        RECT 33.530 459.710 33.670 460.000 ;
        RECT 34.490 459.710 34.630 460.000 ;
        RECT 35.450 459.710 35.590 460.000 ;
        RECT 36.410 459.710 36.550 460.000 ;
        RECT 37.370 459.710 37.510 460.000 ;
        RECT 38.330 459.710 38.470 460.000 ;
        RECT 39.290 459.710 39.430 460.000 ;
        RECT 40.250 459.710 40.390 460.000 ;
        RECT 41.210 459.710 41.350 460.000 ;
        RECT 42.170 459.710 42.310 460.000 ;
        RECT 43.130 459.710 43.270 460.000 ;
        RECT 44.090 459.710 44.230 460.000 ;
        RECT 45.050 459.710 45.190 460.000 ;
        RECT 46.010 459.710 46.150 460.000 ;
        RECT 46.970 459.710 47.110 460.000 ;
        RECT 47.930 459.710 48.070 460.000 ;
        RECT 48.890 459.710 49.030 460.000 ;
        RECT 49.850 459.710 49.990 460.000 ;
        RECT 50.810 459.710 50.950 460.000 ;
        RECT 51.770 459.710 51.910 460.000 ;
        RECT 52.730 459.710 52.870 460.000 ;
        RECT 53.690 459.710 53.830 460.000 ;
        RECT 54.650 459.710 54.790 460.000 ;
        RECT 55.610 459.710 55.750 460.000 ;
        RECT 56.570 459.710 56.710 460.000 ;
        RECT 57.530 459.710 57.670 460.000 ;
        RECT 58.490 459.710 58.630 460.000 ;
        RECT 59.450 459.710 59.590 460.000 ;
        RECT 60.410 459.710 60.550 460.000 ;
        RECT 61.370 459.710 61.510 460.000 ;
        RECT 62.330 459.710 62.470 460.000 ;
        RECT 63.290 459.710 63.430 460.000 ;
        RECT 64.250 459.710 64.390 460.000 ;
        RECT 65.210 459.710 65.350 460.000 ;
        RECT 66.170 459.710 66.310 460.000 ;
        RECT 67.130 459.710 67.270 460.000 ;
        RECT 68.090 459.710 68.230 460.000 ;
        RECT 69.050 459.710 69.190 460.000 ;
        RECT 70.010 459.710 70.150 460.000 ;
        RECT 70.970 459.710 71.110 460.000 ;
        RECT 71.930 459.710 72.070 460.000 ;
        RECT 72.890 459.710 73.030 460.000 ;
        RECT 73.850 459.710 73.990 460.000 ;
        RECT 74.810 459.710 74.950 460.000 ;
        RECT 75.770 459.710 75.910 460.000 ;
        RECT 76.730 459.710 76.870 460.000 ;
        RECT 77.690 459.710 77.830 460.000 ;
        RECT 78.650 459.710 78.790 460.000 ;
        RECT 79.610 459.710 79.750 460.000 ;
        RECT 80.570 459.710 80.710 460.000 ;
        RECT 81.530 459.710 81.670 460.000 ;
        RECT 82.490 459.710 82.630 460.000 ;
        RECT 83.450 459.710 83.590 460.000 ;
        RECT 84.410 459.710 84.550 460.000 ;
        RECT 85.370 459.710 85.510 460.000 ;
        RECT 86.330 459.710 86.470 460.000 ;
        RECT 87.290 459.710 87.430 460.000 ;
        RECT 88.250 459.710 88.390 460.000 ;
        RECT 0.375 0.610 88.905 459.710 ;
        RECT 0.375 0.400 1.030 0.610 ;
        RECT 1.850 0.400 1.990 0.610 ;
        RECT 2.810 0.400 2.950 0.610 ;
        RECT 3.770 0.400 3.910 0.610 ;
        RECT 4.730 0.400 4.870 0.610 ;
        RECT 5.690 0.400 5.830 0.610 ;
        RECT 6.650 0.400 6.790 0.610 ;
        RECT 7.610 0.400 7.750 0.610 ;
        RECT 8.570 0.400 8.710 0.610 ;
        RECT 9.530 0.400 9.670 0.610 ;
        RECT 10.490 0.400 10.630 0.610 ;
        RECT 11.450 0.400 11.590 0.610 ;
        RECT 12.410 0.400 12.550 0.610 ;
        RECT 13.370 0.400 13.510 0.610 ;
        RECT 14.330 0.400 14.470 0.610 ;
        RECT 15.290 0.400 15.430 0.610 ;
        RECT 16.250 0.400 16.390 0.610 ;
        RECT 17.210 0.400 17.350 0.610 ;
        RECT 18.170 0.400 18.310 0.610 ;
        RECT 19.130 0.400 19.270 0.610 ;
        RECT 20.090 0.400 20.230 0.610 ;
        RECT 21.050 0.400 21.190 0.610 ;
        RECT 22.010 0.400 22.150 0.610 ;
        RECT 22.970 0.400 23.110 0.610 ;
        RECT 23.930 0.400 24.070 0.610 ;
        RECT 24.890 0.400 25.030 0.610 ;
        RECT 25.850 0.400 25.990 0.610 ;
        RECT 26.810 0.400 26.950 0.610 ;
        RECT 27.770 0.400 27.910 0.610 ;
        RECT 28.730 0.400 28.870 0.610 ;
        RECT 29.690 0.400 29.830 0.610 ;
        RECT 30.650 0.400 30.790 0.610 ;
        RECT 31.610 0.400 31.750 0.610 ;
        RECT 32.570 0.400 32.710 0.610 ;
        RECT 33.530 0.400 33.670 0.610 ;
        RECT 34.490 0.400 34.630 0.610 ;
        RECT 35.450 0.400 35.590 0.610 ;
        RECT 36.410 0.400 36.550 0.610 ;
        RECT 37.370 0.400 37.510 0.610 ;
        RECT 38.330 0.400 38.470 0.610 ;
        RECT 39.290 0.400 39.430 0.610 ;
        RECT 40.250 0.400 40.390 0.610 ;
        RECT 41.210 0.400 41.350 0.610 ;
        RECT 42.170 0.400 42.310 0.610 ;
        RECT 43.130 0.400 43.270 0.610 ;
        RECT 44.090 0.400 44.230 0.610 ;
        RECT 45.050 0.400 45.190 0.610 ;
        RECT 46.010 0.400 46.150 0.610 ;
        RECT 46.970 0.400 47.110 0.610 ;
        RECT 47.930 0.400 48.070 0.610 ;
        RECT 48.890 0.400 49.030 0.610 ;
        RECT 49.850 0.400 49.990 0.610 ;
        RECT 50.810 0.400 50.950 0.610 ;
        RECT 51.770 0.400 51.910 0.610 ;
        RECT 52.730 0.400 52.870 0.610 ;
        RECT 53.690 0.400 53.830 0.610 ;
        RECT 54.650 0.400 54.790 0.610 ;
        RECT 55.610 0.400 55.750 0.610 ;
        RECT 56.570 0.400 56.710 0.610 ;
        RECT 57.530 0.400 57.670 0.610 ;
        RECT 58.490 0.400 58.630 0.610 ;
        RECT 59.450 0.400 59.590 0.610 ;
        RECT 60.410 0.400 60.550 0.610 ;
        RECT 61.370 0.400 61.510 0.610 ;
        RECT 62.330 0.400 62.470 0.610 ;
        RECT 63.290 0.400 63.430 0.610 ;
        RECT 64.250 0.400 64.390 0.610 ;
        RECT 65.210 0.400 65.350 0.610 ;
        RECT 66.170 0.400 66.310 0.610 ;
        RECT 67.130 0.400 67.270 0.610 ;
        RECT 68.090 0.400 68.230 0.610 ;
        RECT 69.050 0.400 69.190 0.610 ;
        RECT 70.010 0.400 70.150 0.610 ;
        RECT 70.970 0.400 71.110 0.610 ;
        RECT 71.930 0.400 72.070 0.610 ;
        RECT 72.890 0.400 73.030 0.610 ;
        RECT 73.850 0.400 73.990 0.610 ;
        RECT 74.810 0.400 74.950 0.610 ;
        RECT 75.770 0.400 75.910 0.610 ;
        RECT 76.730 0.400 76.870 0.610 ;
        RECT 77.690 0.400 77.830 0.610 ;
        RECT 78.650 0.400 78.790 0.610 ;
        RECT 79.610 0.400 79.750 0.610 ;
        RECT 80.570 0.400 80.710 0.610 ;
        RECT 81.530 0.400 81.670 0.610 ;
        RECT 82.490 0.400 82.630 0.610 ;
        RECT 83.450 0.400 83.590 0.610 ;
        RECT 84.410 0.400 84.550 0.610 ;
        RECT 85.370 0.400 85.510 0.610 ;
        RECT 86.330 0.400 86.470 0.610 ;
        RECT 87.290 0.400 87.430 0.610 ;
        RECT 88.250 0.400 88.390 0.610 ;
      LAYER Metal3 ;
        RECT 0.335 457.790 88.945 460.005 ;
        RECT 0.610 456.970 88.945 457.790 ;
        RECT 0.335 456.110 88.945 456.970 ;
        RECT 0.610 455.290 88.945 456.110 ;
        RECT 0.335 454.430 88.945 455.290 ;
        RECT 0.610 453.610 88.945 454.430 ;
        RECT 0.335 453.590 88.945 453.610 ;
        RECT 0.335 452.770 88.670 453.590 ;
        RECT 0.335 452.750 88.945 452.770 ;
        RECT 0.610 451.930 88.945 452.750 ;
        RECT 0.335 451.070 88.945 451.930 ;
        RECT 0.610 450.250 88.945 451.070 ;
        RECT 0.335 449.390 88.945 450.250 ;
        RECT 0.610 448.570 88.945 449.390 ;
        RECT 0.335 447.710 88.945 448.570 ;
        RECT 0.610 446.890 88.945 447.710 ;
        RECT 0.335 446.870 88.945 446.890 ;
        RECT 0.335 446.050 88.670 446.870 ;
        RECT 0.335 446.030 88.945 446.050 ;
        RECT 0.610 445.210 88.945 446.030 ;
        RECT 0.335 444.350 88.945 445.210 ;
        RECT 0.610 443.530 88.945 444.350 ;
        RECT 0.335 442.670 88.945 443.530 ;
        RECT 0.610 441.850 88.945 442.670 ;
        RECT 0.335 440.990 88.945 441.850 ;
        RECT 0.610 440.170 88.945 440.990 ;
        RECT 0.335 440.150 88.945 440.170 ;
        RECT 0.335 439.330 88.670 440.150 ;
        RECT 0.335 439.310 88.945 439.330 ;
        RECT 0.610 438.490 88.945 439.310 ;
        RECT 0.335 437.630 88.945 438.490 ;
        RECT 0.610 436.810 88.945 437.630 ;
        RECT 0.335 435.950 88.945 436.810 ;
        RECT 0.610 435.130 88.945 435.950 ;
        RECT 0.335 434.270 88.945 435.130 ;
        RECT 0.610 433.450 88.945 434.270 ;
        RECT 0.335 433.430 88.945 433.450 ;
        RECT 0.335 432.610 88.670 433.430 ;
        RECT 0.335 432.590 88.945 432.610 ;
        RECT 0.610 431.770 88.945 432.590 ;
        RECT 0.335 430.910 88.945 431.770 ;
        RECT 0.610 430.090 88.945 430.910 ;
        RECT 0.335 429.230 88.945 430.090 ;
        RECT 0.610 428.410 88.945 429.230 ;
        RECT 0.335 427.550 88.945 428.410 ;
        RECT 0.610 426.730 88.945 427.550 ;
        RECT 0.335 426.710 88.945 426.730 ;
        RECT 0.335 425.890 88.670 426.710 ;
        RECT 0.335 425.870 88.945 425.890 ;
        RECT 0.610 425.050 88.945 425.870 ;
        RECT 0.335 424.190 88.945 425.050 ;
        RECT 0.610 423.370 88.945 424.190 ;
        RECT 0.335 422.510 88.945 423.370 ;
        RECT 0.610 421.690 88.945 422.510 ;
        RECT 0.335 420.830 88.945 421.690 ;
        RECT 0.610 420.010 88.945 420.830 ;
        RECT 0.335 419.990 88.945 420.010 ;
        RECT 0.335 419.170 88.670 419.990 ;
        RECT 0.335 419.150 88.945 419.170 ;
        RECT 0.610 418.330 88.945 419.150 ;
        RECT 0.335 417.470 88.945 418.330 ;
        RECT 0.610 416.650 88.945 417.470 ;
        RECT 0.335 415.790 88.945 416.650 ;
        RECT 0.610 414.970 88.945 415.790 ;
        RECT 0.335 414.110 88.945 414.970 ;
        RECT 0.610 413.290 88.945 414.110 ;
        RECT 0.335 413.270 88.945 413.290 ;
        RECT 0.335 412.450 88.670 413.270 ;
        RECT 0.335 412.430 88.945 412.450 ;
        RECT 0.610 411.610 88.945 412.430 ;
        RECT 0.335 410.750 88.945 411.610 ;
        RECT 0.610 409.930 88.945 410.750 ;
        RECT 0.335 409.070 88.945 409.930 ;
        RECT 0.610 408.250 88.945 409.070 ;
        RECT 0.335 407.390 88.945 408.250 ;
        RECT 0.610 406.570 88.945 407.390 ;
        RECT 0.335 406.550 88.945 406.570 ;
        RECT 0.335 405.730 88.670 406.550 ;
        RECT 0.335 405.710 88.945 405.730 ;
        RECT 0.610 404.890 88.945 405.710 ;
        RECT 0.335 402.350 88.945 404.890 ;
        RECT 0.610 401.530 88.945 402.350 ;
        RECT 0.335 399.830 88.945 401.530 ;
        RECT 0.610 399.010 88.670 399.830 ;
        RECT 0.335 398.150 88.945 399.010 ;
        RECT 0.610 397.330 88.945 398.150 ;
        RECT 0.335 396.470 88.945 397.330 ;
        RECT 0.610 395.650 88.945 396.470 ;
        RECT 0.335 394.790 88.945 395.650 ;
        RECT 0.610 393.970 88.945 394.790 ;
        RECT 0.335 393.110 88.945 393.970 ;
        RECT 0.610 392.290 88.670 393.110 ;
        RECT 0.335 391.430 88.945 392.290 ;
        RECT 0.610 390.610 88.945 391.430 ;
        RECT 0.335 389.750 88.945 390.610 ;
        RECT 0.610 388.930 88.945 389.750 ;
        RECT 0.335 388.070 88.945 388.930 ;
        RECT 0.610 387.250 88.945 388.070 ;
        RECT 0.335 386.390 88.945 387.250 ;
        RECT 0.610 385.570 88.670 386.390 ;
        RECT 0.335 384.710 88.945 385.570 ;
        RECT 0.610 383.890 88.945 384.710 ;
        RECT 0.335 383.030 88.945 383.890 ;
        RECT 0.610 382.210 88.945 383.030 ;
        RECT 0.335 381.350 88.945 382.210 ;
        RECT 0.610 380.530 88.945 381.350 ;
        RECT 0.335 379.670 88.945 380.530 ;
        RECT 0.335 378.850 88.670 379.670 ;
        RECT 0.335 377.990 88.945 378.850 ;
        RECT 0.610 377.170 88.945 377.990 ;
        RECT 0.335 376.310 88.945 377.170 ;
        RECT 0.610 375.490 88.945 376.310 ;
        RECT 0.335 374.630 88.945 375.490 ;
        RECT 0.610 373.810 88.945 374.630 ;
        RECT 0.335 372.950 88.945 373.810 ;
        RECT 0.610 372.130 88.670 372.950 ;
        RECT 0.335 371.270 88.945 372.130 ;
        RECT 0.610 370.450 88.945 371.270 ;
        RECT 0.335 369.590 88.945 370.450 ;
        RECT 0.610 368.770 88.945 369.590 ;
        RECT 0.335 367.910 88.945 368.770 ;
        RECT 0.610 367.090 88.945 367.910 ;
        RECT 0.335 366.230 88.945 367.090 ;
        RECT 0.610 365.410 88.670 366.230 ;
        RECT 0.335 364.550 88.945 365.410 ;
        RECT 0.610 363.730 88.945 364.550 ;
        RECT 0.335 362.870 88.945 363.730 ;
        RECT 0.610 362.050 88.945 362.870 ;
        RECT 0.335 361.190 88.945 362.050 ;
        RECT 0.610 360.370 88.945 361.190 ;
        RECT 0.335 359.510 88.945 360.370 ;
        RECT 0.610 358.690 88.670 359.510 ;
        RECT 0.335 357.830 88.945 358.690 ;
        RECT 0.610 357.010 88.945 357.830 ;
        RECT 0.335 356.150 88.945 357.010 ;
        RECT 0.610 355.330 88.945 356.150 ;
        RECT 0.335 354.470 88.945 355.330 ;
        RECT 0.610 353.650 88.945 354.470 ;
        RECT 0.335 352.790 88.945 353.650 ;
        RECT 0.610 351.970 88.670 352.790 ;
        RECT 0.335 350.270 88.945 351.970 ;
        RECT 0.610 349.450 88.945 350.270 ;
        RECT 0.335 348.590 88.945 349.450 ;
        RECT 0.610 347.770 88.945 348.590 ;
        RECT 0.335 346.910 88.945 347.770 ;
        RECT 0.610 346.090 88.945 346.910 ;
        RECT 0.335 346.070 88.945 346.090 ;
        RECT 0.335 345.250 88.670 346.070 ;
        RECT 0.335 345.230 88.945 345.250 ;
        RECT 0.610 344.410 88.945 345.230 ;
        RECT 0.335 343.550 88.945 344.410 ;
        RECT 0.610 342.730 88.945 343.550 ;
        RECT 0.335 341.870 88.945 342.730 ;
        RECT 0.610 341.050 88.945 341.870 ;
        RECT 0.335 340.190 88.945 341.050 ;
        RECT 0.610 339.370 88.945 340.190 ;
        RECT 0.335 339.350 88.945 339.370 ;
        RECT 0.335 338.530 88.670 339.350 ;
        RECT 0.335 338.510 88.945 338.530 ;
        RECT 0.610 337.690 88.945 338.510 ;
        RECT 0.335 335.990 88.945 337.690 ;
        RECT 0.610 335.170 88.945 335.990 ;
        RECT 0.335 334.310 88.945 335.170 ;
        RECT 0.610 333.490 88.945 334.310 ;
        RECT 0.335 332.630 88.945 333.490 ;
        RECT 0.610 331.810 88.670 332.630 ;
        RECT 0.335 330.950 88.945 331.810 ;
        RECT 0.610 330.130 88.945 330.950 ;
        RECT 0.335 329.270 88.945 330.130 ;
        RECT 0.610 328.450 88.945 329.270 ;
        RECT 0.335 327.590 88.945 328.450 ;
        RECT 0.610 326.770 88.945 327.590 ;
        RECT 0.335 325.910 88.945 326.770 ;
        RECT 0.610 325.090 88.670 325.910 ;
        RECT 0.335 324.230 88.945 325.090 ;
        RECT 0.610 323.410 88.945 324.230 ;
        RECT 0.335 321.710 88.945 323.410 ;
        RECT 0.610 320.890 88.945 321.710 ;
        RECT 0.335 320.030 88.945 320.890 ;
        RECT 0.610 319.210 88.945 320.030 ;
        RECT 0.335 319.190 88.945 319.210 ;
        RECT 0.335 318.370 88.670 319.190 ;
        RECT 0.335 318.350 88.945 318.370 ;
        RECT 0.610 317.530 88.945 318.350 ;
        RECT 0.335 316.670 88.945 317.530 ;
        RECT 0.610 315.850 88.945 316.670 ;
        RECT 0.335 314.150 88.945 315.850 ;
        RECT 0.610 313.330 88.945 314.150 ;
        RECT 0.335 312.470 88.945 313.330 ;
        RECT 0.610 311.650 88.670 312.470 ;
        RECT 0.335 310.790 88.945 311.650 ;
        RECT 0.610 309.970 88.945 310.790 ;
        RECT 0.335 309.110 88.945 309.970 ;
        RECT 0.610 308.290 88.945 309.110 ;
        RECT 0.335 307.430 88.945 308.290 ;
        RECT 0.610 306.610 88.945 307.430 ;
        RECT 0.335 305.750 88.945 306.610 ;
        RECT 0.610 304.930 88.670 305.750 ;
        RECT 0.335 304.070 88.945 304.930 ;
        RECT 0.610 303.250 88.945 304.070 ;
        RECT 0.335 302.390 88.945 303.250 ;
        RECT 0.610 301.570 88.945 302.390 ;
        RECT 0.335 300.710 88.945 301.570 ;
        RECT 0.610 299.890 88.945 300.710 ;
        RECT 0.335 299.030 88.945 299.890 ;
        RECT 0.610 298.210 88.670 299.030 ;
        RECT 0.335 297.350 88.945 298.210 ;
        RECT 0.610 296.530 88.945 297.350 ;
        RECT 0.335 295.670 88.945 296.530 ;
        RECT 0.610 294.850 88.945 295.670 ;
        RECT 0.335 292.310 88.945 294.850 ;
        RECT 0.610 291.490 88.670 292.310 ;
        RECT 0.335 290.630 88.945 291.490 ;
        RECT 0.610 289.810 88.945 290.630 ;
        RECT 0.335 288.950 88.945 289.810 ;
        RECT 0.610 288.130 88.945 288.950 ;
        RECT 0.335 287.270 88.945 288.130 ;
        RECT 0.610 286.450 88.945 287.270 ;
        RECT 0.335 285.590 88.945 286.450 ;
        RECT 0.610 284.770 88.670 285.590 ;
        RECT 0.335 283.910 88.945 284.770 ;
        RECT 0.610 283.090 88.945 283.910 ;
        RECT 0.335 282.230 88.945 283.090 ;
        RECT 0.610 281.410 88.945 282.230 ;
        RECT 0.335 280.550 88.945 281.410 ;
        RECT 0.610 279.730 88.945 280.550 ;
        RECT 0.335 278.870 88.945 279.730 ;
        RECT 0.610 278.050 88.670 278.870 ;
        RECT 0.335 277.190 88.945 278.050 ;
        RECT 0.610 276.370 88.945 277.190 ;
        RECT 0.335 275.510 88.945 276.370 ;
        RECT 0.610 274.690 88.945 275.510 ;
        RECT 0.335 273.830 88.945 274.690 ;
        RECT 0.610 273.010 88.945 273.830 ;
        RECT 0.335 272.150 88.945 273.010 ;
        RECT 0.610 271.330 88.670 272.150 ;
        RECT 0.335 270.470 88.945 271.330 ;
        RECT 0.610 269.650 88.945 270.470 ;
        RECT 0.335 268.790 88.945 269.650 ;
        RECT 0.610 267.970 88.945 268.790 ;
        RECT 0.335 267.110 88.945 267.970 ;
        RECT 0.610 266.290 88.945 267.110 ;
        RECT 0.335 265.430 88.945 266.290 ;
        RECT 0.335 264.610 88.670 265.430 ;
        RECT 0.335 264.590 88.945 264.610 ;
        RECT 0.610 263.770 88.945 264.590 ;
        RECT 0.335 262.910 88.945 263.770 ;
        RECT 0.610 262.090 88.945 262.910 ;
        RECT 0.335 261.230 88.945 262.090 ;
        RECT 0.610 260.410 88.945 261.230 ;
        RECT 0.335 259.550 88.945 260.410 ;
        RECT 0.610 258.730 88.945 259.550 ;
        RECT 0.335 258.710 88.945 258.730 ;
        RECT 0.335 257.890 88.670 258.710 ;
        RECT 0.335 257.870 88.945 257.890 ;
        RECT 0.610 257.050 88.945 257.870 ;
        RECT 0.335 256.190 88.945 257.050 ;
        RECT 0.610 255.370 88.945 256.190 ;
        RECT 0.335 254.510 88.945 255.370 ;
        RECT 0.610 253.690 88.945 254.510 ;
        RECT 0.335 252.830 88.945 253.690 ;
        RECT 0.610 252.010 88.945 252.830 ;
        RECT 0.335 251.990 88.945 252.010 ;
        RECT 0.335 251.170 88.670 251.990 ;
        RECT 0.335 251.150 88.945 251.170 ;
        RECT 0.610 250.330 88.945 251.150 ;
        RECT 0.335 249.470 88.945 250.330 ;
        RECT 0.610 248.650 88.945 249.470 ;
        RECT 0.335 247.790 88.945 248.650 ;
        RECT 0.610 246.970 88.945 247.790 ;
        RECT 0.335 246.110 88.945 246.970 ;
        RECT 0.610 245.290 88.945 246.110 ;
        RECT 0.335 245.270 88.945 245.290 ;
        RECT 0.335 244.450 88.670 245.270 ;
        RECT 0.335 244.430 88.945 244.450 ;
        RECT 0.610 243.610 88.945 244.430 ;
        RECT 0.335 242.750 88.945 243.610 ;
        RECT 0.610 241.930 88.945 242.750 ;
        RECT 0.335 241.070 88.945 241.930 ;
        RECT 0.610 240.250 88.945 241.070 ;
        RECT 0.335 239.390 88.945 240.250 ;
        RECT 0.610 238.570 88.945 239.390 ;
        RECT 0.335 236.870 88.945 238.570 ;
        RECT 0.610 236.050 88.945 236.870 ;
        RECT 0.335 235.190 88.945 236.050 ;
        RECT 0.610 234.370 88.945 235.190 ;
        RECT 0.335 234.350 88.945 234.370 ;
        RECT 0.335 233.530 88.670 234.350 ;
        RECT 0.335 233.510 88.945 233.530 ;
        RECT 0.610 232.690 88.945 233.510 ;
        RECT 0.335 231.830 88.945 232.690 ;
        RECT 0.610 231.010 88.945 231.830 ;
        RECT 0.335 227.630 88.945 231.010 ;
        RECT 0.610 226.810 88.945 227.630 ;
        RECT 0.335 225.950 88.945 226.810 ;
        RECT 0.610 225.130 88.945 225.950 ;
        RECT 0.335 224.270 88.945 225.130 ;
        RECT 0.610 223.450 88.945 224.270 ;
        RECT 0.335 222.590 88.945 223.450 ;
        RECT 0.610 221.770 88.945 222.590 ;
        RECT 0.335 221.750 88.945 221.770 ;
        RECT 0.335 220.930 88.670 221.750 ;
        RECT 0.335 220.910 88.945 220.930 ;
        RECT 0.610 220.090 88.945 220.910 ;
        RECT 0.335 219.230 88.945 220.090 ;
        RECT 0.610 218.410 88.670 219.230 ;
        RECT 0.335 217.550 88.945 218.410 ;
        RECT 0.610 216.730 88.945 217.550 ;
        RECT 0.335 216.710 88.945 216.730 ;
        RECT 0.335 215.890 88.670 216.710 ;
        RECT 0.335 215.870 88.945 215.890 ;
        RECT 0.610 215.050 88.945 215.870 ;
        RECT 0.335 214.190 88.945 215.050 ;
        RECT 0.610 213.370 88.670 214.190 ;
        RECT 0.335 212.510 88.945 213.370 ;
        RECT 0.610 211.690 88.945 212.510 ;
        RECT 0.335 211.670 88.945 211.690 ;
        RECT 0.335 210.850 88.670 211.670 ;
        RECT 0.335 210.830 88.945 210.850 ;
        RECT 0.610 210.010 88.945 210.830 ;
        RECT 0.335 209.150 88.945 210.010 ;
        RECT 0.610 208.330 88.670 209.150 ;
        RECT 0.335 207.470 88.945 208.330 ;
        RECT 0.610 206.650 88.945 207.470 ;
        RECT 0.335 206.630 88.945 206.650 ;
        RECT 0.335 205.810 88.670 206.630 ;
        RECT 0.335 205.790 88.945 205.810 ;
        RECT 0.610 204.970 88.945 205.790 ;
        RECT 0.335 204.110 88.945 204.970 ;
        RECT 0.610 203.290 88.670 204.110 ;
        RECT 0.335 202.430 88.945 203.290 ;
        RECT 0.610 201.610 88.945 202.430 ;
        RECT 0.335 201.590 88.945 201.610 ;
        RECT 0.335 200.770 88.670 201.590 ;
        RECT 0.335 200.750 88.945 200.770 ;
        RECT 0.610 199.930 88.945 200.750 ;
        RECT 0.335 199.070 88.945 199.930 ;
        RECT 0.610 198.250 88.670 199.070 ;
        RECT 0.335 197.390 88.945 198.250 ;
        RECT 0.610 196.570 88.945 197.390 ;
        RECT 0.335 196.550 88.945 196.570 ;
        RECT 0.335 195.730 88.670 196.550 ;
        RECT 0.335 195.710 88.945 195.730 ;
        RECT 0.610 194.890 88.945 195.710 ;
        RECT 0.335 194.030 88.945 194.890 ;
        RECT 0.610 193.210 88.670 194.030 ;
        RECT 0.335 192.350 88.945 193.210 ;
        RECT 0.610 191.530 88.945 192.350 ;
        RECT 0.335 191.510 88.945 191.530 ;
        RECT 0.335 190.690 88.670 191.510 ;
        RECT 0.335 190.670 88.945 190.690 ;
        RECT 0.610 189.850 88.945 190.670 ;
        RECT 0.335 188.990 88.945 189.850 ;
        RECT 0.610 188.170 88.670 188.990 ;
        RECT 0.335 187.310 88.945 188.170 ;
        RECT 0.610 186.490 88.945 187.310 ;
        RECT 0.335 186.470 88.945 186.490 ;
        RECT 0.335 185.650 88.670 186.470 ;
        RECT 0.335 185.630 88.945 185.650 ;
        RECT 0.610 184.810 88.945 185.630 ;
        RECT 0.335 183.950 88.945 184.810 ;
        RECT 0.610 183.130 88.670 183.950 ;
        RECT 0.335 182.270 88.945 183.130 ;
        RECT 0.610 181.450 88.945 182.270 ;
        RECT 0.335 181.430 88.945 181.450 ;
        RECT 0.335 180.610 88.670 181.430 ;
        RECT 0.335 180.590 88.945 180.610 ;
        RECT 0.610 179.770 88.945 180.590 ;
        RECT 0.335 178.910 88.945 179.770 ;
        RECT 0.610 178.090 88.670 178.910 ;
        RECT 0.335 177.230 88.945 178.090 ;
        RECT 0.610 176.410 88.945 177.230 ;
        RECT 0.335 176.390 88.945 176.410 ;
        RECT 0.335 175.570 88.670 176.390 ;
        RECT 0.335 175.550 88.945 175.570 ;
        RECT 0.610 174.730 88.945 175.550 ;
        RECT 0.335 173.870 88.945 174.730 ;
        RECT 0.335 173.050 88.670 173.870 ;
        RECT 0.335 172.190 88.945 173.050 ;
        RECT 0.610 171.370 88.945 172.190 ;
        RECT 0.335 171.350 88.945 171.370 ;
        RECT 0.335 170.530 88.670 171.350 ;
        RECT 0.335 169.670 88.945 170.530 ;
        RECT 0.610 168.850 88.945 169.670 ;
        RECT 0.335 168.830 88.945 168.850 ;
        RECT 0.335 168.010 88.670 168.830 ;
        RECT 0.335 167.990 88.945 168.010 ;
        RECT 0.610 167.170 88.945 167.990 ;
        RECT 0.335 166.310 88.945 167.170 ;
        RECT 0.610 165.490 88.670 166.310 ;
        RECT 0.335 164.630 88.945 165.490 ;
        RECT 0.610 163.810 88.945 164.630 ;
        RECT 0.335 163.790 88.945 163.810 ;
        RECT 0.335 162.970 88.670 163.790 ;
        RECT 0.335 162.950 88.945 162.970 ;
        RECT 0.610 162.130 88.945 162.950 ;
        RECT 0.335 161.270 88.945 162.130 ;
        RECT 0.610 160.450 88.670 161.270 ;
        RECT 0.335 159.590 88.945 160.450 ;
        RECT 0.610 158.770 88.945 159.590 ;
        RECT 0.335 158.750 88.945 158.770 ;
        RECT 0.335 157.930 88.670 158.750 ;
        RECT 0.335 157.910 88.945 157.930 ;
        RECT 0.610 157.090 88.945 157.910 ;
        RECT 0.335 156.230 88.945 157.090 ;
        RECT 0.610 155.410 88.670 156.230 ;
        RECT 0.335 154.550 88.945 155.410 ;
        RECT 0.610 153.730 88.945 154.550 ;
        RECT 0.335 153.710 88.945 153.730 ;
        RECT 0.335 152.890 88.670 153.710 ;
        RECT 0.335 152.870 88.945 152.890 ;
        RECT 0.610 152.050 88.945 152.870 ;
        RECT 0.335 151.190 88.945 152.050 ;
        RECT 0.610 150.370 88.670 151.190 ;
        RECT 0.335 148.670 88.945 150.370 ;
        RECT 0.335 147.850 88.670 148.670 ;
        RECT 0.335 147.830 88.945 147.850 ;
        RECT 0.610 147.010 88.945 147.830 ;
        RECT 0.335 146.150 88.945 147.010 ;
        RECT 0.610 145.330 88.670 146.150 ;
        RECT 0.335 144.470 88.945 145.330 ;
        RECT 0.610 143.650 88.945 144.470 ;
        RECT 0.335 143.630 88.945 143.650 ;
        RECT 0.335 142.810 88.670 143.630 ;
        RECT 0.335 142.790 88.945 142.810 ;
        RECT 0.610 141.970 88.945 142.790 ;
        RECT 0.335 141.110 88.945 141.970 ;
        RECT 0.610 140.290 88.670 141.110 ;
        RECT 0.335 139.430 88.945 140.290 ;
        RECT 0.610 138.610 88.945 139.430 ;
        RECT 0.335 138.590 88.945 138.610 ;
        RECT 0.335 137.770 88.670 138.590 ;
        RECT 0.335 137.750 88.945 137.770 ;
        RECT 0.610 136.930 88.945 137.750 ;
        RECT 0.335 136.070 88.945 136.930 ;
        RECT 0.610 135.250 88.670 136.070 ;
        RECT 0.335 134.390 88.945 135.250 ;
        RECT 0.610 133.570 88.945 134.390 ;
        RECT 0.335 133.550 88.945 133.570 ;
        RECT 0.335 132.730 88.670 133.550 ;
        RECT 0.335 132.710 88.945 132.730 ;
        RECT 0.610 131.890 88.945 132.710 ;
        RECT 0.335 131.030 88.945 131.890 ;
        RECT 0.610 130.210 88.670 131.030 ;
        RECT 0.335 129.350 88.945 130.210 ;
        RECT 0.610 128.530 88.945 129.350 ;
        RECT 0.335 128.510 88.945 128.530 ;
        RECT 0.335 127.690 88.670 128.510 ;
        RECT 0.335 127.670 88.945 127.690 ;
        RECT 0.610 126.850 88.945 127.670 ;
        RECT 0.335 125.990 88.945 126.850 ;
        RECT 0.610 125.170 88.670 125.990 ;
        RECT 0.335 124.310 88.945 125.170 ;
        RECT 0.610 123.490 88.945 124.310 ;
        RECT 0.335 123.470 88.945 123.490 ;
        RECT 0.335 122.650 88.670 123.470 ;
        RECT 0.335 122.630 88.945 122.650 ;
        RECT 0.610 121.810 88.945 122.630 ;
        RECT 0.335 120.950 88.945 121.810 ;
        RECT 0.335 120.130 88.670 120.950 ;
        RECT 0.335 120.110 88.945 120.130 ;
        RECT 0.610 119.290 88.945 120.110 ;
        RECT 0.335 118.430 88.945 119.290 ;
        RECT 0.610 117.610 88.670 118.430 ;
        RECT 0.335 116.750 88.945 117.610 ;
        RECT 0.610 115.930 88.945 116.750 ;
        RECT 0.335 115.910 88.945 115.930 ;
        RECT 0.335 115.090 88.670 115.910 ;
        RECT 0.335 115.070 88.945 115.090 ;
        RECT 0.610 114.250 88.945 115.070 ;
        RECT 0.335 113.390 88.945 114.250 ;
        RECT 0.610 112.570 88.670 113.390 ;
        RECT 0.335 111.710 88.945 112.570 ;
        RECT 0.610 110.890 88.945 111.710 ;
        RECT 0.335 110.870 88.945 110.890 ;
        RECT 0.335 110.050 88.670 110.870 ;
        RECT 0.335 110.030 88.945 110.050 ;
        RECT 0.610 109.210 88.945 110.030 ;
        RECT 0.335 108.350 88.945 109.210 ;
        RECT 0.610 107.530 88.670 108.350 ;
        RECT 0.335 105.830 88.945 107.530 ;
        RECT 0.610 105.010 88.670 105.830 ;
        RECT 0.335 104.150 88.945 105.010 ;
        RECT 0.610 103.330 88.945 104.150 ;
        RECT 0.335 103.310 88.945 103.330 ;
        RECT 0.335 102.490 88.670 103.310 ;
        RECT 0.335 102.470 88.945 102.490 ;
        RECT 0.610 101.650 88.945 102.470 ;
        RECT 0.335 100.790 88.945 101.650 ;
        RECT 0.610 99.970 88.945 100.790 ;
        RECT 0.335 99.110 88.945 99.970 ;
        RECT 0.610 98.290 88.945 99.110 ;
        RECT 0.335 97.430 88.945 98.290 ;
        RECT 0.610 96.610 88.945 97.430 ;
        RECT 0.335 95.750 88.945 96.610 ;
        RECT 0.610 94.930 88.945 95.750 ;
        RECT 0.335 94.070 88.945 94.930 ;
        RECT 0.610 93.250 88.945 94.070 ;
        RECT 0.335 91.550 88.945 93.250 ;
        RECT 0.610 90.730 88.945 91.550 ;
        RECT 0.335 89.870 88.945 90.730 ;
        RECT 0.610 89.050 88.945 89.870 ;
        RECT 0.335 88.190 88.945 89.050 ;
        RECT 0.610 87.370 88.670 88.190 ;
        RECT 0.335 86.510 88.945 87.370 ;
        RECT 0.610 85.690 88.945 86.510 ;
        RECT 0.335 85.670 88.945 85.690 ;
        RECT 0.335 84.850 88.670 85.670 ;
        RECT 0.335 83.990 88.945 84.850 ;
        RECT 0.610 83.170 88.945 83.990 ;
        RECT 0.335 83.150 88.945 83.170 ;
        RECT 0.335 82.330 88.670 83.150 ;
        RECT 0.335 82.310 88.945 82.330 ;
        RECT 0.610 81.490 88.945 82.310 ;
        RECT 0.335 80.630 88.945 81.490 ;
        RECT 0.610 79.810 88.670 80.630 ;
        RECT 0.335 78.950 88.945 79.810 ;
        RECT 0.610 78.130 88.945 78.950 ;
        RECT 0.335 78.110 88.945 78.130 ;
        RECT 0.335 77.290 88.670 78.110 ;
        RECT 0.335 77.270 88.945 77.290 ;
        RECT 0.610 76.450 88.945 77.270 ;
        RECT 0.335 75.590 88.945 76.450 ;
        RECT 0.610 74.770 88.670 75.590 ;
        RECT 0.335 73.910 88.945 74.770 ;
        RECT 0.610 73.090 88.945 73.910 ;
        RECT 0.335 73.070 88.945 73.090 ;
        RECT 0.335 72.250 88.670 73.070 ;
        RECT 0.335 72.230 88.945 72.250 ;
        RECT 0.610 71.410 88.945 72.230 ;
        RECT 0.335 70.550 88.945 71.410 ;
        RECT 0.610 69.730 88.670 70.550 ;
        RECT 0.335 68.870 88.945 69.730 ;
        RECT 0.610 68.050 88.945 68.870 ;
        RECT 0.335 68.030 88.945 68.050 ;
        RECT 0.335 67.210 88.670 68.030 ;
        RECT 0.335 67.190 88.945 67.210 ;
        RECT 0.610 66.370 88.945 67.190 ;
        RECT 0.335 65.510 88.945 66.370 ;
        RECT 0.610 64.690 88.670 65.510 ;
        RECT 0.335 62.990 88.945 64.690 ;
        RECT 0.335 62.170 88.670 62.990 ;
        RECT 0.335 62.150 88.945 62.170 ;
        RECT 0.610 61.330 88.945 62.150 ;
        RECT 0.335 60.470 88.945 61.330 ;
        RECT 0.610 59.650 88.670 60.470 ;
        RECT 0.335 58.790 88.945 59.650 ;
        RECT 0.610 57.970 88.945 58.790 ;
        RECT 0.335 57.950 88.945 57.970 ;
        RECT 0.335 57.130 88.670 57.950 ;
        RECT 0.335 57.110 88.945 57.130 ;
        RECT 0.610 56.290 88.945 57.110 ;
        RECT 0.335 55.430 88.945 56.290 ;
        RECT 0.610 54.610 88.670 55.430 ;
        RECT 0.335 53.750 88.945 54.610 ;
        RECT 0.610 52.930 88.945 53.750 ;
        RECT 0.335 52.910 88.945 52.930 ;
        RECT 0.335 52.090 88.670 52.910 ;
        RECT 0.335 52.070 88.945 52.090 ;
        RECT 0.610 51.250 88.945 52.070 ;
        RECT 0.335 50.390 88.945 51.250 ;
        RECT 0.610 49.570 88.670 50.390 ;
        RECT 0.335 48.710 88.945 49.570 ;
        RECT 0.610 47.890 88.945 48.710 ;
        RECT 0.335 47.870 88.945 47.890 ;
        RECT 0.335 47.050 88.670 47.870 ;
        RECT 0.335 47.030 88.945 47.050 ;
        RECT 0.610 46.210 88.945 47.030 ;
        RECT 0.335 45.350 88.945 46.210 ;
        RECT 0.610 44.530 88.670 45.350 ;
        RECT 0.335 43.670 88.945 44.530 ;
        RECT 0.610 42.850 88.945 43.670 ;
        RECT 0.335 42.830 88.945 42.850 ;
        RECT 0.335 42.010 88.670 42.830 ;
        RECT 0.335 41.990 88.945 42.010 ;
        RECT 0.610 41.170 88.945 41.990 ;
        RECT 0.335 40.310 88.945 41.170 ;
        RECT 0.610 39.490 88.670 40.310 ;
        RECT 0.335 38.630 88.945 39.490 ;
        RECT 0.610 37.810 88.945 38.630 ;
        RECT 0.335 37.790 88.945 37.810 ;
        RECT 0.335 36.970 88.670 37.790 ;
        RECT 0.335 36.950 88.945 36.970 ;
        RECT 0.610 36.130 88.945 36.950 ;
        RECT 0.335 35.270 88.945 36.130 ;
        RECT 0.335 34.450 88.670 35.270 ;
        RECT 0.335 34.430 88.945 34.450 ;
        RECT 0.610 33.610 88.945 34.430 ;
        RECT 0.335 32.750 88.945 33.610 ;
        RECT 0.610 31.930 88.670 32.750 ;
        RECT 0.335 31.070 88.945 31.930 ;
        RECT 0.610 30.250 88.945 31.070 ;
        RECT 0.335 30.230 88.945 30.250 ;
        RECT 0.335 29.410 88.670 30.230 ;
        RECT 0.335 29.390 88.945 29.410 ;
        RECT 0.610 28.570 88.945 29.390 ;
        RECT 0.335 27.710 88.945 28.570 ;
        RECT 0.610 26.890 88.670 27.710 ;
        RECT 0.335 26.030 88.945 26.890 ;
        RECT 0.610 25.210 88.945 26.030 ;
        RECT 0.335 25.190 88.945 25.210 ;
        RECT 0.335 24.370 88.670 25.190 ;
        RECT 0.335 24.350 88.945 24.370 ;
        RECT 0.610 23.530 88.945 24.350 ;
        RECT 0.335 22.670 88.945 23.530 ;
        RECT 0.610 21.850 88.670 22.670 ;
        RECT 0.335 20.990 88.945 21.850 ;
        RECT 0.610 20.170 88.945 20.990 ;
        RECT 0.335 20.150 88.945 20.170 ;
        RECT 0.335 19.330 88.670 20.150 ;
        RECT 0.335 19.310 88.945 19.330 ;
        RECT 0.610 18.490 88.945 19.310 ;
        RECT 0.335 17.630 88.945 18.490 ;
        RECT 0.610 16.810 88.670 17.630 ;
        RECT 0.335 15.950 88.945 16.810 ;
        RECT 0.610 15.130 88.945 15.950 ;
        RECT 0.335 15.110 88.945 15.130 ;
        RECT 0.335 14.290 88.670 15.110 ;
        RECT 0.335 14.270 88.945 14.290 ;
        RECT 0.610 13.450 88.945 14.270 ;
        RECT 0.335 12.590 88.945 13.450 ;
        RECT 0.610 11.770 88.670 12.590 ;
        RECT 0.335 10.910 88.945 11.770 ;
        RECT 0.610 10.090 88.945 10.910 ;
        RECT 0.335 10.070 88.945 10.090 ;
        RECT 0.335 9.250 88.670 10.070 ;
        RECT 0.335 9.230 88.945 9.250 ;
        RECT 0.610 8.410 88.945 9.230 ;
        RECT 0.335 6.710 88.945 8.410 ;
        RECT 0.610 5.890 88.945 6.710 ;
        RECT 0.335 5.030 88.945 5.890 ;
        RECT 0.610 4.210 88.945 5.030 ;
        RECT 0.335 3.350 88.945 4.210 ;
        RECT 0.610 2.530 88.945 3.350 ;
        RECT 0.335 2.510 88.945 2.530 ;
        RECT 0.335 1.690 88.670 2.510 ;
        RECT 0.335 1.670 88.945 1.690 ;
        RECT 0.610 0.850 88.945 1.670 ;
        RECT 0.335 0.315 88.945 0.850 ;
      LAYER Metal4 ;
        RECT 0.380 0.275 10.730 460.045 ;
        RECT 12.150 0.275 13.730 460.045 ;
        RECT 15.150 0.275 60.730 460.045 ;
        RECT 62.150 0.275 63.730 460.045 ;
        RECT 65.150 0.275 88.900 460.045 ;
  END
END NPU_SLICE
END LIBRARY

